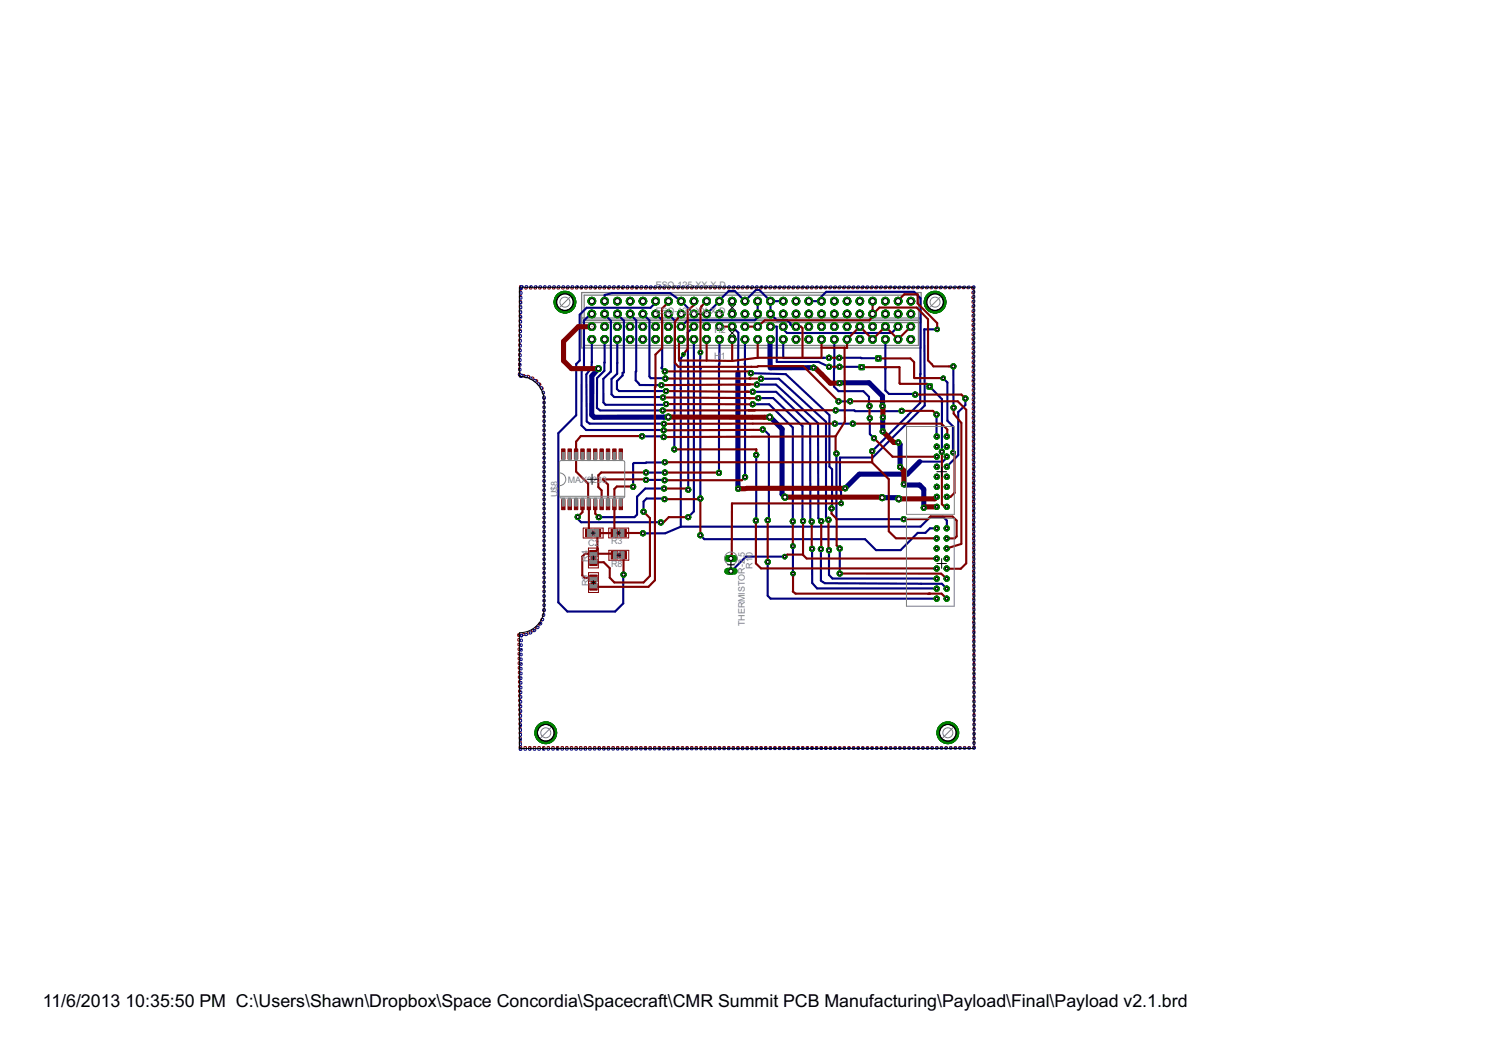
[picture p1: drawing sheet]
<svg xmlns="http://www.w3.org/2000/svg" width="297mm" height="210mm" viewBox="0 0 297 210" stroke-linecap="round" stroke-linejoin="round" font-family="sans-serif">
<defs><g id="words">
<g font-size="4">
<text x="8.5" y="200.4">11/6/2013</text>
<text x="25" y="200.4">10:35:50 PM C:\Users\Shawn\Dropbox\Space Concordia\Spacecraft\CMR Summit PCB Manufacturing\Payload\Final\Payload v2.1.brd</text>
</g>
<g font-size="2" fill="#808080">
<text x="130.5" y="57.4">ESQ-125-XX-X-D</text>
<text x="130.5" y="62.4">ESQ-125-X</text>
<text x="139.6" y="62.4">X-X-D</text>
<text x="142.1" y="71.3">H</text>
<text x="142.1" y="66.3">H2</text>
<text x="143.4" y="71.3">1</text>
<text x="110.9" y="98.9" transform="rotate(-90 110.9 98.9)">U$8</text>
<text x="113" y="96.1">MAX3</text>
<text x="117.8" y="96.1">233</text>
<text x="117" y="108.6">C2</text>
<text x="117" y="111.8" transform="rotate(-90 117 111.8)">R4</text>
<text x="121.6" y="108.3">R3</text>
<text x="121.6" y="112.8">R8</text>
<text x="149.7" y="113.1" transform="rotate(-90 149.7 113.1)">R10</text>
<text x="117.1" y="116.7" transform="rotate(-90 117.1 116.7)">R9</text>
<text x="148.2" y="124.6" transform="rotate(-90 148.2 124.6)">THERMISTOR-2,5</text>
</g>
</g></defs>
<path d="M115.7 58.2h67.6l-.1 11h-67.5zM116.2 58.7h66.6v5h-66.6zM115.7 64.2h67.6M115.7 63.3h67.5M116.2 63.8h66.5v4.9h-66.5z" fill="none" stroke="#808080" stroke-width=".25"/>
<g fill="none" stroke="#000080" stroke-width=".42">
<path d="M120.3 59.9v-1.2l1.5-.4h11.5l2.2 1.6 2.6 2.6h2.5l4.4-4.6h1.2l2 2 2.2-2.2h.7l2.2 2.2M130.5 59.9v.3l-1.1 1h-12.7l-1.4 1.4v9.1l-.7 .7v10.2l-3.5 3.6v33.6l1.8 1.9h9.5l1.6-1.6 .1-5.8M150.7 59.9v3.2l-.5 .6h-13.4l-1.3 1.3M153.3 59.9h2.5M153.3 59.9v2.6l1.3 1.3h2.1l1 1.2h.7M160.9 59.9h2.5v-.9l1-.9h17.5l1.2 1.2v20.8l-9.6 9.7M117.8 62.5h-.3l-1.3 1.3v9.4l-.5 .5v10.9l.9 1h15.4M117.8 67.5l-.1 5.7-1.1 1.3 .1 9.4 .6 .4h14.8M119.1 73.3l-.2 .1v.2M120.3 62.5l1.2 1.3v10.1l-1.5 1.5 .1 4.7 .4 .4h11.5l.5-.1M120.3 67.5l-.1 6.3-1.4 1.4v6l.6 .5h12.4M120.3 72.1h-.1"/>
<path d="M122.8 67.5v6.9l-1.1 1v3.1l.5 .5h9.8l-.1 .1M122.8 62.5l1.3 1.3v10.3l-.2 .1v.5l-1.2 1.1v1.6l.5 .4h9.3M125.4 62.5l1.2 1.3-.1 11.9 .8 .9h4.3M127.9 62.5l1.3 1.2v11.2l.3 .3 2.9 .1M130.5 62.5l1.2 1.2v9.3l-.1 .2 .7 .7M133 62.5l1.3 1.2-.1 25.7M136 70.5l-.6 .9v33.4M138 65l-1.2 1.1 .1 31.3M138 67.5v34.2l-1.1 1.2M138 72.5h.1M139.4 70.1l-.1 3 .1 .2-.1 25.9M143.1 67.5l-.1 26.6"/>
<path d="M145.7 65l1.2 1.2-.1 7.9M148.2 67.5v27.4M149.4 74.3l6.9 .1 8.7 8.2v10.2l.5 .6v7.6l-.1 .2M149.8 78h4.6l6.8 6.5v19.2l.3 .1M150.6 76.5h3.8l8.4 7.7v18.9l.6 .6M150.9 79.2h2.9l5.9 5.6v18.8l.1 .1M151.4 75.4h3.6l9.3 8.5v19l.5 .5M153.3 65h1.2v7h8.4l2.1 1M153.3 67.5l-.1 .1M155.8 65v.5l.8 .8h20.8l1.3-1.3M155.8 67.5v3.7h9.1M166 67.5l-.1 9.4 .9 .9h5l1.1 1.2v1.7l.1 .1"/>
<path d="M167 71.2l7.8 .1M167 73h4.4M167.2 76.2h-.2M169.1 79.8l-2.3 .1M176.1 67.5v10.2l.8 .7h5.1l.1 .1M183.9 65.5l.1 15.2-10.4 10.3h-6.5v6.5l.2 .2 .1 2.5M183.9 65.5v.1M183.9 65.5h2.6M185 76.9l2.4 2.5v10.5M187.7 75.3l.8 .8v7.6l1.1 1.1v5.2M189.7 72.9v8.2M192.1 79.3v1.3l-1.5 1.4v8.6l-2.2 2.3"/>
<path d="M127.7 86.8h4.4l-.1 .2M128.5 94h3.8M128.5 95.5h3.7M131.8 81.7h.1M132.1 97.2h-3.7l-1.7 1.6v3.6l-.5 .5h-7.1M132.2 99.3l-.1-.1h-3.5l-.6 .6v2M132.3 92l-6.2 .1-.1 .2v4.5M146.8 97.2h.1M149.8 80.4h3.2l4.7 4.7v18.6M150.5 90.5l-.1 13.1M151.7 85.4h.3l1 1.1v16.8l-.3 .2M153.1 83h.1"/>
<path d="M166.1 84.3h3.6M166.3 81.6h3.7l.1 .2 9.3-.1M166.4 90.2l.1 13.1h13.3M173.1 83.2v3.2l.8 .8M175.7 83l-.1 .1M178.6 99l.2 .3M179.8 96.4l.2 .1M186.3 82.5l.1 4.3M188.4 90.8v.3l-.8 .7h-4.6M114.9 102.8v.4l.7 .7h15.9M135.4 104.8l-3.1 1.3h-4.4M135.4 104.8h47.8l1.9-2h2.5l.8 .8v1.5"/>
<path d="M152.7 111.8v6.7l.6 .6h33.1M156.1 110.7h-7.7l-3 2.9M157.8 108.6v5.5M161.6 109.2v6.8l1 1.1h23.8M163.3 109.2v6.3l.8 .5 23.3 .1 .9 1M164.9 109.5v4.9l.7 .7h20.8M167.1 109.1v5M179.8 103.3h.1M186.4 105.1h-1.4l-.9 .9h-1.5l-3.4 3.5h-4.9l-2.2-2.2h-32l-.8-.8M188.4 105.1h-.1"/>
</g>
<path d="M118.9 73.6l-1.1 1.2-.1 7.7 .5 .5h14.7M118.9 73.4h.2M119.1 73.3v.1M146.8 74.1v23.1M153.2 67.6v5.6h8.7M167.2 76.2h5.7l2.7 2.6v2M153.2 83l2.4 2.3v13l.6 .6M175.5 99h3.1M175.6 83.1v2.7M178.7 88l.4 .4v4.5M180 96.5h3l.8 .8v3.7M183 91.8l-2.5 2.5h-9.5l-2.9 2.9" fill="none" stroke="#000080" stroke-width="1"/>
<circle cx="117.8" cy="62.5" r=".76" fill="#008000" stroke="#008000" stroke-width=".2"/>
<circle cx="117.8" cy="62.5" r=".51" fill="#fff" stroke="#000" stroke-width=".2"/>
<circle cx="117.8" cy="59.9" r=".76" fill="#008000" stroke="#008000" stroke-width=".2"/>
<circle cx="117.8" cy="59.9" r=".51" fill="#fff" stroke="#000" stroke-width=".2"/>
<circle cx="120.3" cy="62.5" r=".76" fill="#008000" stroke="#008000" stroke-width=".2"/>
<circle cx="120.3" cy="62.5" r=".51" fill="#fff" stroke="#000" stroke-width=".2"/>
<circle cx="120.3" cy="59.9" r=".76" fill="#008000" stroke="#008000" stroke-width=".2"/>
<circle cx="120.3" cy="59.9" r=".51" fill="#fff" stroke="#000" stroke-width=".2"/>
<circle cx="122.8" cy="62.5" r=".76" fill="#008000" stroke="#008000" stroke-width=".2"/>
<circle cx="122.8" cy="62.5" r=".51" fill="#fff" stroke="#000" stroke-width=".2"/>
<circle cx="122.8" cy="59.9" r=".76" fill="#008000" stroke="#008000" stroke-width=".2"/>
<circle cx="122.8" cy="59.9" r=".51" fill="#fff" stroke="#000" stroke-width=".2"/>
<circle cx="125.4" cy="62.5" r=".76" fill="#008000" stroke="#008000" stroke-width=".2"/>
<circle cx="125.4" cy="62.5" r=".51" fill="#fff" stroke="#000" stroke-width=".2"/>
<circle cx="125.4" cy="59.9" r=".76" fill="#008000" stroke="#008000" stroke-width=".2"/>
<circle cx="125.4" cy="59.9" r=".51" fill="#fff" stroke="#000" stroke-width=".2"/>
<circle cx="127.9" cy="62.5" r=".76" fill="#008000" stroke="#008000" stroke-width=".2"/>
<circle cx="127.9" cy="62.5" r=".51" fill="#fff" stroke="#000" stroke-width=".2"/>
<circle cx="127.9" cy="59.9" r=".76" fill="#008000" stroke="#008000" stroke-width=".2"/>
<circle cx="127.9" cy="59.9" r=".51" fill="#fff" stroke="#000" stroke-width=".2"/>
<circle cx="130.5" cy="62.5" r=".76" fill="#008000" stroke="#008000" stroke-width=".2"/>
<circle cx="130.5" cy="62.5" r=".51" fill="#fff" stroke="#000" stroke-width=".2"/>
<circle cx="130.5" cy="59.9" r=".76" fill="#008000" stroke="#008000" stroke-width=".2"/>
<circle cx="130.5" cy="59.9" r=".51" fill="#fff" stroke="#000" stroke-width=".2"/>
<circle cx="133" cy="62.5" r=".76" fill="#008000" stroke="#008000" stroke-width=".2"/>
<circle cx="133" cy="62.5" r=".51" fill="#fff" stroke="#000" stroke-width=".2"/>
<circle cx="133" cy="59.9" r=".76" fill="#008000" stroke="#008000" stroke-width=".2"/>
<circle cx="133" cy="59.9" r=".51" fill="#fff" stroke="#000" stroke-width=".2"/>
<circle cx="135.5" cy="62.5" r=".76" fill="#008000" stroke="#008000" stroke-width=".2"/>
<circle cx="135.5" cy="62.5" r=".51" fill="#fff" stroke="#000" stroke-width=".2"/>
<circle cx="135.5" cy="59.9" r=".76" fill="#008000" stroke="#008000" stroke-width=".2"/>
<circle cx="135.5" cy="59.9" r=".51" fill="#fff" stroke="#000" stroke-width=".2"/>
<circle cx="138.1" cy="62.5" r=".76" fill="#008000" stroke="#008000" stroke-width=".2"/>
<circle cx="138.1" cy="62.5" r=".51" fill="#fff" stroke="#000" stroke-width=".2"/>
<circle cx="138.1" cy="59.9" r=".76" fill="#008000" stroke="#008000" stroke-width=".2"/>
<circle cx="138.1" cy="59.9" r=".51" fill="#fff" stroke="#000" stroke-width=".2"/>
<circle cx="140.6" cy="62.5" r=".76" fill="#008000" stroke="#008000" stroke-width=".2"/>
<circle cx="140.6" cy="62.5" r=".51" fill="#fff" stroke="#000" stroke-width=".2"/>
<circle cx="140.6" cy="59.9" r=".76" fill="#008000" stroke="#008000" stroke-width=".2"/>
<circle cx="140.6" cy="59.9" r=".51" fill="#fff" stroke="#000" stroke-width=".2"/>
<circle cx="143.1" cy="62.5" r=".76" fill="#008000" stroke="#008000" stroke-width=".2"/>
<circle cx="143.1" cy="62.5" r=".51" fill="#fff" stroke="#000" stroke-width=".2"/>
<circle cx="143.1" cy="59.9" r=".76" fill="#008000" stroke="#008000" stroke-width=".2"/>
<circle cx="143.1" cy="59.9" r=".51" fill="#fff" stroke="#000" stroke-width=".2"/>
<circle cx="145.7" cy="62.5" r=".76" fill="#008000" stroke="#008000" stroke-width=".2"/>
<circle cx="145.7" cy="62.5" r=".51" fill="#fff" stroke="#000" stroke-width=".2"/>
<circle cx="145.7" cy="59.9" r=".76" fill="#008000" stroke="#008000" stroke-width=".2"/>
<circle cx="145.7" cy="59.9" r=".51" fill="#fff" stroke="#000" stroke-width=".2"/>
<circle cx="148.2" cy="62.5" r=".76" fill="#008000" stroke="#008000" stroke-width=".2"/>
<circle cx="148.2" cy="62.5" r=".51" fill="#fff" stroke="#000" stroke-width=".2"/>
<circle cx="148.2" cy="59.9" r=".76" fill="#008000" stroke="#008000" stroke-width=".2"/>
<circle cx="148.2" cy="59.9" r=".51" fill="#fff" stroke="#000" stroke-width=".2"/>
<circle cx="150.7" cy="62.5" r=".76" fill="#008000" stroke="#008000" stroke-width=".2"/>
<circle cx="150.7" cy="62.5" r=".51" fill="#fff" stroke="#000" stroke-width=".2"/>
<circle cx="150.7" cy="59.9" r=".76" fill="#008000" stroke="#008000" stroke-width=".2"/>
<circle cx="150.7" cy="59.9" r=".51" fill="#fff" stroke="#000" stroke-width=".2"/>
<circle cx="153.3" cy="62.5" r=".76" fill="#008000" stroke="#008000" stroke-width=".2"/>
<circle cx="153.3" cy="62.5" r=".51" fill="#fff" stroke="#000" stroke-width=".2"/>
<circle cx="153.3" cy="59.9" r=".76" fill="#008000" stroke="#008000" stroke-width=".2"/>
<circle cx="153.3" cy="59.9" r=".51" fill="#fff" stroke="#000" stroke-width=".2"/>
<circle cx="155.8" cy="62.5" r=".76" fill="#008000" stroke="#008000" stroke-width=".2"/>
<circle cx="155.8" cy="62.5" r=".51" fill="#fff" stroke="#000" stroke-width=".2"/>
<circle cx="155.8" cy="59.9" r=".76" fill="#008000" stroke="#008000" stroke-width=".2"/>
<circle cx="155.8" cy="59.9" r=".51" fill="#fff" stroke="#000" stroke-width=".2"/>
<circle cx="158.4" cy="62.5" r=".76" fill="#008000" stroke="#008000" stroke-width=".2"/>
<circle cx="158.4" cy="62.5" r=".51" fill="#fff" stroke="#000" stroke-width=".2"/>
<circle cx="158.4" cy="59.9" r=".76" fill="#008000" stroke="#008000" stroke-width=".2"/>
<circle cx="158.4" cy="59.9" r=".51" fill="#fff" stroke="#000" stroke-width=".2"/>
<circle cx="160.9" cy="62.5" r=".76" fill="#008000" stroke="#008000" stroke-width=".2"/>
<circle cx="160.9" cy="62.5" r=".51" fill="#fff" stroke="#000" stroke-width=".2"/>
<circle cx="160.9" cy="59.9" r=".76" fill="#008000" stroke="#008000" stroke-width=".2"/>
<circle cx="160.9" cy="59.9" r=".51" fill="#fff" stroke="#000" stroke-width=".2"/>
<circle cx="163.4" cy="62.5" r=".76" fill="#008000" stroke="#008000" stroke-width=".2"/>
<circle cx="163.4" cy="62.5" r=".51" fill="#fff" stroke="#000" stroke-width=".2"/>
<circle cx="163.4" cy="59.9" r=".76" fill="#008000" stroke="#008000" stroke-width=".2"/>
<circle cx="163.4" cy="59.9" r=".51" fill="#fff" stroke="#000" stroke-width=".2"/>
<circle cx="166" cy="62.5" r=".76" fill="#008000" stroke="#008000" stroke-width=".2"/>
<circle cx="166" cy="62.5" r=".51" fill="#fff" stroke="#000" stroke-width=".2"/>
<circle cx="166" cy="59.9" r=".76" fill="#008000" stroke="#008000" stroke-width=".2"/>
<circle cx="166" cy="59.9" r=".51" fill="#fff" stroke="#000" stroke-width=".2"/>
<circle cx="168.5" cy="62.5" r=".76" fill="#008000" stroke="#008000" stroke-width=".2"/>
<circle cx="168.5" cy="62.5" r=".51" fill="#fff" stroke="#000" stroke-width=".2"/>
<circle cx="168.5" cy="59.9" r=".76" fill="#008000" stroke="#008000" stroke-width=".2"/>
<circle cx="168.5" cy="59.9" r=".51" fill="#fff" stroke="#000" stroke-width=".2"/>
<circle cx="171.1" cy="62.5" r=".76" fill="#008000" stroke="#008000" stroke-width=".2"/>
<circle cx="171.1" cy="62.5" r=".51" fill="#fff" stroke="#000" stroke-width=".2"/>
<circle cx="171.1" cy="59.9" r=".76" fill="#008000" stroke="#008000" stroke-width=".2"/>
<circle cx="171.1" cy="59.9" r=".51" fill="#fff" stroke="#000" stroke-width=".2"/>
<circle cx="173.6" cy="62.5" r=".76" fill="#008000" stroke="#008000" stroke-width=".2"/>
<circle cx="173.6" cy="62.5" r=".51" fill="#fff" stroke="#000" stroke-width=".2"/>
<circle cx="173.6" cy="59.9" r=".76" fill="#008000" stroke="#008000" stroke-width=".2"/>
<circle cx="173.6" cy="59.9" r=".51" fill="#fff" stroke="#000" stroke-width=".2"/>
<circle cx="176.1" cy="62.5" r=".76" fill="#008000" stroke="#008000" stroke-width=".2"/>
<circle cx="176.1" cy="62.5" r=".51" fill="#fff" stroke="#000" stroke-width=".2"/>
<circle cx="176.1" cy="59.9" r=".76" fill="#008000" stroke="#008000" stroke-width=".2"/>
<circle cx="176.1" cy="59.9" r=".51" fill="#fff" stroke="#000" stroke-width=".2"/>
<circle cx="178.7" cy="62.5" r=".76" fill="#008000" stroke="#008000" stroke-width=".2"/>
<circle cx="178.7" cy="62.5" r=".51" fill="#fff" stroke="#000" stroke-width=".2"/>
<circle cx="178.7" cy="59.9" r=".76" fill="#008000" stroke="#008000" stroke-width=".2"/>
<circle cx="178.7" cy="59.9" r=".51" fill="#fff" stroke="#000" stroke-width=".2"/>
<circle cx="181.2" cy="62.5" r=".76" fill="#008000" stroke="#008000" stroke-width=".2"/>
<circle cx="181.2" cy="62.5" r=".51" fill="#fff" stroke="#000" stroke-width=".2"/>
<circle cx="181.2" cy="59.9" r=".76" fill="#008000" stroke="#008000" stroke-width=".2"/>
<circle cx="181.2" cy="59.9" r=".51" fill="#fff" stroke="#000" stroke-width=".2"/>
<circle cx="117.8" cy="67.5" r=".76" fill="#008000" stroke="#008000" stroke-width=".2"/>
<circle cx="117.8" cy="67.5" r=".51" fill="#fff" stroke="#000" stroke-width=".2"/>
<circle cx="117.8" cy="65" r=".76" fill="#008000" stroke="#008000" stroke-width=".2"/>
<circle cx="117.8" cy="65" r=".51" fill="#fff" stroke="#000" stroke-width=".2"/>
<circle cx="120.3" cy="67.5" r=".76" fill="#008000" stroke="#008000" stroke-width=".2"/>
<circle cx="120.3" cy="67.5" r=".51" fill="#fff" stroke="#000" stroke-width=".2"/>
<circle cx="120.3" cy="65" r=".76" fill="#008000" stroke="#008000" stroke-width=".2"/>
<circle cx="120.3" cy="65" r=".51" fill="#fff" stroke="#000" stroke-width=".2"/>
<circle cx="122.8" cy="67.5" r=".76" fill="#008000" stroke="#008000" stroke-width=".2"/>
<circle cx="122.8" cy="67.5" r=".51" fill="#fff" stroke="#000" stroke-width=".2"/>
<circle cx="122.8" cy="65" r=".76" fill="#008000" stroke="#008000" stroke-width=".2"/>
<circle cx="122.8" cy="65" r=".51" fill="#fff" stroke="#000" stroke-width=".2"/>
<circle cx="125.3" cy="67.5" r=".76" fill="#008000" stroke="#008000" stroke-width=".2"/>
<circle cx="125.3" cy="67.5" r=".51" fill="#fff" stroke="#000" stroke-width=".2"/>
<circle cx="125.3" cy="65" r=".76" fill="#008000" stroke="#008000" stroke-width=".2"/>
<circle cx="125.3" cy="65" r=".51" fill="#fff" stroke="#000" stroke-width=".2"/>
<circle cx="127.9" cy="67.5" r=".76" fill="#008000" stroke="#008000" stroke-width=".2"/>
<circle cx="127.9" cy="67.5" r=".51" fill="#fff" stroke="#000" stroke-width=".2"/>
<circle cx="127.9" cy="65" r=".76" fill="#008000" stroke="#008000" stroke-width=".2"/>
<circle cx="127.9" cy="65" r=".51" fill="#fff" stroke="#000" stroke-width=".2"/>
<circle cx="130.4" cy="67.5" r=".76" fill="#008000" stroke="#008000" stroke-width=".2"/>
<circle cx="130.4" cy="67.5" r=".51" fill="#fff" stroke="#000" stroke-width=".2"/>
<circle cx="130.4" cy="65" r=".76" fill="#008000" stroke="#008000" stroke-width=".2"/>
<circle cx="130.4" cy="65" r=".51" fill="#fff" stroke="#000" stroke-width=".2"/>
<circle cx="133" cy="67.5" r=".76" fill="#008000" stroke="#008000" stroke-width=".2"/>
<circle cx="133" cy="67.5" r=".51" fill="#fff" stroke="#000" stroke-width=".2"/>
<circle cx="133" cy="65" r=".76" fill="#008000" stroke="#008000" stroke-width=".2"/>
<circle cx="133" cy="65" r=".51" fill="#fff" stroke="#000" stroke-width=".2"/>
<circle cx="135.5" cy="67.5" r=".76" fill="#008000" stroke="#008000" stroke-width=".2"/>
<circle cx="135.5" cy="67.5" r=".51" fill="#fff" stroke="#000" stroke-width=".2"/>
<circle cx="135.5" cy="65" r=".76" fill="#008000" stroke="#008000" stroke-width=".2"/>
<circle cx="135.5" cy="65" r=".51" fill="#fff" stroke="#000" stroke-width=".2"/>
<circle cx="138" cy="67.5" r=".76" fill="#008000" stroke="#008000" stroke-width=".2"/>
<circle cx="138" cy="67.5" r=".51" fill="#fff" stroke="#000" stroke-width=".2"/>
<circle cx="138" cy="65" r=".76" fill="#008000" stroke="#008000" stroke-width=".2"/>
<circle cx="138" cy="65" r=".51" fill="#fff" stroke="#000" stroke-width=".2"/>
<circle cx="140.6" cy="67.5" r=".76" fill="#008000" stroke="#008000" stroke-width=".2"/>
<circle cx="140.6" cy="67.5" r=".51" fill="#fff" stroke="#000" stroke-width=".2"/>
<circle cx="140.6" cy="65" r=".76" fill="#008000" stroke="#008000" stroke-width=".2"/>
<circle cx="140.6" cy="65" r=".51" fill="#fff" stroke="#000" stroke-width=".2"/>
<circle cx="143.1" cy="67.5" r=".76" fill="#008000" stroke="#008000" stroke-width=".2"/>
<circle cx="143.1" cy="67.5" r=".51" fill="#fff" stroke="#000" stroke-width=".2"/>
<circle cx="143.1" cy="65" r=".76" fill="#008000" stroke="#008000" stroke-width=".2"/>
<circle cx="143.1" cy="65" r=".51" fill="#fff" stroke="#000" stroke-width=".2"/>
<circle cx="145.7" cy="67.5" r=".76" fill="#008000" stroke="#008000" stroke-width=".2"/>
<circle cx="145.7" cy="67.5" r=".51" fill="#fff" stroke="#000" stroke-width=".2"/>
<circle cx="145.7" cy="65" r=".76" fill="#008000" stroke="#008000" stroke-width=".2"/>
<circle cx="145.7" cy="65" r=".51" fill="#fff" stroke="#000" stroke-width=".2"/>
<circle cx="148.2" cy="67.5" r=".76" fill="#008000" stroke="#008000" stroke-width=".2"/>
<circle cx="148.2" cy="67.5" r=".51" fill="#fff" stroke="#000" stroke-width=".2"/>
<circle cx="148.2" cy="65" r=".76" fill="#008000" stroke="#008000" stroke-width=".2"/>
<circle cx="148.2" cy="65" r=".51" fill="#fff" stroke="#000" stroke-width=".2"/>
<circle cx="150.7" cy="67.5" r=".76" fill="#008000" stroke="#008000" stroke-width=".2"/>
<circle cx="150.7" cy="67.5" r=".51" fill="#fff" stroke="#000" stroke-width=".2"/>
<circle cx="150.7" cy="65" r=".76" fill="#008000" stroke="#008000" stroke-width=".2"/>
<circle cx="150.7" cy="65" r=".51" fill="#fff" stroke="#000" stroke-width=".2"/>
<circle cx="153.3" cy="67.5" r=".76" fill="#008000" stroke="#008000" stroke-width=".2"/>
<circle cx="153.3" cy="67.5" r=".51" fill="#fff" stroke="#000" stroke-width=".2"/>
<circle cx="153.3" cy="65" r=".76" fill="#008000" stroke="#008000" stroke-width=".2"/>
<circle cx="153.3" cy="65" r=".51" fill="#fff" stroke="#000" stroke-width=".2"/>
<circle cx="155.8" cy="67.5" r=".76" fill="#008000" stroke="#008000" stroke-width=".2"/>
<circle cx="155.8" cy="67.5" r=".51" fill="#fff" stroke="#000" stroke-width=".2"/>
<circle cx="155.8" cy="65" r=".76" fill="#008000" stroke="#008000" stroke-width=".2"/>
<circle cx="155.8" cy="65" r=".51" fill="#fff" stroke="#000" stroke-width=".2"/>
<circle cx="158.4" cy="67.5" r=".76" fill="#008000" stroke="#008000" stroke-width=".2"/>
<circle cx="158.4" cy="67.5" r=".51" fill="#fff" stroke="#000" stroke-width=".2"/>
<circle cx="158.4" cy="65" r=".76" fill="#008000" stroke="#008000" stroke-width=".2"/>
<circle cx="158.4" cy="65" r=".51" fill="#fff" stroke="#000" stroke-width=".2"/>
<circle cx="160.9" cy="67.5" r=".76" fill="#008000" stroke="#008000" stroke-width=".2"/>
<circle cx="160.9" cy="67.5" r=".51" fill="#fff" stroke="#000" stroke-width=".2"/>
<circle cx="160.9" cy="65" r=".76" fill="#008000" stroke="#008000" stroke-width=".2"/>
<circle cx="160.9" cy="65" r=".51" fill="#fff" stroke="#000" stroke-width=".2"/>
<circle cx="163.4" cy="67.5" r=".76" fill="#008000" stroke="#008000" stroke-width=".2"/>
<circle cx="163.4" cy="67.5" r=".51" fill="#fff" stroke="#000" stroke-width=".2"/>
<circle cx="163.4" cy="65" r=".76" fill="#008000" stroke="#008000" stroke-width=".2"/>
<circle cx="163.4" cy="65" r=".51" fill="#fff" stroke="#000" stroke-width=".2"/>
<circle cx="166" cy="67.5" r=".76" fill="#008000" stroke="#008000" stroke-width=".2"/>
<circle cx="166" cy="67.5" r=".51" fill="#fff" stroke="#000" stroke-width=".2"/>
<circle cx="166" cy="65" r=".76" fill="#008000" stroke="#008000" stroke-width=".2"/>
<circle cx="166" cy="65" r=".51" fill="#fff" stroke="#000" stroke-width=".2"/>
<circle cx="168.5" cy="67.5" r=".76" fill="#008000" stroke="#008000" stroke-width=".2"/>
<circle cx="168.5" cy="67.5" r=".51" fill="#fff" stroke="#000" stroke-width=".2"/>
<circle cx="168.5" cy="65" r=".76" fill="#008000" stroke="#008000" stroke-width=".2"/>
<circle cx="168.5" cy="65" r=".51" fill="#fff" stroke="#000" stroke-width=".2"/>
<circle cx="171.1" cy="67.5" r=".76" fill="#008000" stroke="#008000" stroke-width=".2"/>
<circle cx="171.1" cy="67.5" r=".51" fill="#fff" stroke="#000" stroke-width=".2"/>
<circle cx="171.1" cy="65" r=".76" fill="#008000" stroke="#008000" stroke-width=".2"/>
<circle cx="171.1" cy="65" r=".51" fill="#fff" stroke="#000" stroke-width=".2"/>
<circle cx="173.6" cy="67.5" r=".76" fill="#008000" stroke="#008000" stroke-width=".2"/>
<circle cx="173.6" cy="67.5" r=".51" fill="#fff" stroke="#000" stroke-width=".2"/>
<circle cx="173.6" cy="65" r=".76" fill="#008000" stroke="#008000" stroke-width=".2"/>
<circle cx="173.6" cy="65" r=".51" fill="#fff" stroke="#000" stroke-width=".2"/>
<circle cx="176.1" cy="67.5" r=".76" fill="#008000" stroke="#008000" stroke-width=".2"/>
<circle cx="176.1" cy="67.5" r=".51" fill="#fff" stroke="#000" stroke-width=".2"/>
<circle cx="176.1" cy="65" r=".76" fill="#008000" stroke="#008000" stroke-width=".2"/>
<circle cx="176.1" cy="65" r=".51" fill="#fff" stroke="#000" stroke-width=".2"/>
<circle cx="178.7" cy="67.5" r=".76" fill="#008000" stroke="#008000" stroke-width=".2"/>
<circle cx="178.7" cy="67.5" r=".51" fill="#fff" stroke="#000" stroke-width=".2"/>
<circle cx="178.7" cy="65" r=".76" fill="#008000" stroke="#008000" stroke-width=".2"/>
<circle cx="178.7" cy="65" r=".51" fill="#fff" stroke="#000" stroke-width=".2"/>
<circle cx="181.2" cy="67.5" r=".76" fill="#008000" stroke="#008000" stroke-width=".2"/>
<circle cx="181.2" cy="67.5" r=".51" fill="#fff" stroke="#000" stroke-width=".2"/>
<circle cx="181.2" cy="65" r=".76" fill="#008000" stroke="#008000" stroke-width=".2"/>
<circle cx="181.2" cy="65" r=".51" fill="#fff" stroke="#000" stroke-width=".2"/>
<circle cx="186.4" cy="100.8" r=".51" fill="#008000" stroke="#008000" stroke-width=".2"/>
<circle cx="186.4" cy="100.8" r=".25" fill="#fff" stroke="#000" stroke-width=".2"/>
<circle cx="188.4" cy="100.8" r=".51" fill="#008000" stroke="#008000" stroke-width=".2"/>
<circle cx="188.4" cy="100.8" r=".25" fill="#fff" stroke="#000" stroke-width=".2"/>
<circle cx="186.4" cy="98.8" r=".51" fill="#008000" stroke="#008000" stroke-width=".2"/>
<circle cx="186.4" cy="98.8" r=".25" fill="#fff" stroke="#000" stroke-width=".2"/>
<circle cx="188.4" cy="98.8" r=".51" fill="#008000" stroke="#008000" stroke-width=".2"/>
<circle cx="188.4" cy="98.8" r=".25" fill="#fff" stroke="#000" stroke-width=".2"/>
<circle cx="186.4" cy="96.9" r=".51" fill="#008000" stroke="#008000" stroke-width=".2"/>
<circle cx="186.4" cy="96.9" r=".25" fill="#fff" stroke="#000" stroke-width=".2"/>
<circle cx="188.4" cy="96.9" r=".51" fill="#008000" stroke="#008000" stroke-width=".2"/>
<circle cx="188.4" cy="96.9" r=".25" fill="#fff" stroke="#000" stroke-width=".2"/>
<circle cx="186.4" cy="94.8" r=".51" fill="#008000" stroke="#008000" stroke-width=".2"/>
<circle cx="186.4" cy="94.8" r=".25" fill="#fff" stroke="#000" stroke-width=".2"/>
<circle cx="188.4" cy="94.8" r=".51" fill="#008000" stroke="#008000" stroke-width=".2"/>
<circle cx="188.4" cy="94.8" r=".25" fill="#fff" stroke="#000" stroke-width=".2"/>
<circle cx="186.4" cy="92.9" r=".51" fill="#008000" stroke="#008000" stroke-width=".2"/>
<circle cx="186.4" cy="92.9" r=".25" fill="#fff" stroke="#000" stroke-width=".2"/>
<circle cx="188.4" cy="92.9" r=".51" fill="#008000" stroke="#008000" stroke-width=".2"/>
<circle cx="188.4" cy="92.9" r=".25" fill="#fff" stroke="#000" stroke-width=".2"/>
<circle cx="186.4" cy="90.8" r=".51" fill="#008000" stroke="#008000" stroke-width=".2"/>
<circle cx="186.4" cy="90.8" r=".25" fill="#fff" stroke="#000" stroke-width=".2"/>
<circle cx="188.4" cy="90.8" r=".51" fill="#008000" stroke="#008000" stroke-width=".2"/>
<circle cx="188.4" cy="90.8" r=".25" fill="#fff" stroke="#000" stroke-width=".2"/>
<circle cx="186.4" cy="88.9" r=".51" fill="#008000" stroke="#008000" stroke-width=".2"/>
<circle cx="186.4" cy="88.9" r=".25" fill="#fff" stroke="#000" stroke-width=".2"/>
<circle cx="188.4" cy="88.9" r=".51" fill="#008000" stroke="#008000" stroke-width=".2"/>
<circle cx="188.4" cy="88.9" r=".25" fill="#fff" stroke="#000" stroke-width=".2"/>
<circle cx="186.4" cy="86.8" r=".51" fill="#008000" stroke="#008000" stroke-width=".2"/>
<circle cx="186.4" cy="86.8" r=".25" fill="#fff" stroke="#000" stroke-width=".2"/>
<circle cx="188.4" cy="86.8" r=".51" fill="#008000" stroke="#008000" stroke-width=".2"/>
<circle cx="188.4" cy="86.8" r=".25" fill="#fff" stroke="#000" stroke-width=".2"/>
<circle cx="186.4" cy="119.1" r=".51" fill="#008000" stroke="#008000" stroke-width=".2"/>
<circle cx="186.4" cy="119.1" r=".25" fill="#fff" stroke="#000" stroke-width=".2"/>
<circle cx="188.3" cy="119.1" r=".51" fill="#008000" stroke="#008000" stroke-width=".2"/>
<circle cx="188.3" cy="119.1" r=".25" fill="#fff" stroke="#000" stroke-width=".2"/>
<circle cx="186.4" cy="117.1" r=".51" fill="#008000" stroke="#008000" stroke-width=".2"/>
<circle cx="186.4" cy="117.1" r=".25" fill="#fff" stroke="#000" stroke-width=".2"/>
<circle cx="188.3" cy="117.1" r=".51" fill="#008000" stroke="#008000" stroke-width=".2"/>
<circle cx="188.3" cy="117.1" r=".25" fill="#fff" stroke="#000" stroke-width=".2"/>
<circle cx="186.4" cy="115.1" r=".51" fill="#008000" stroke="#008000" stroke-width=".2"/>
<circle cx="186.4" cy="115.1" r=".25" fill="#fff" stroke="#000" stroke-width=".2"/>
<circle cx="188.3" cy="115.1" r=".51" fill="#008000" stroke="#008000" stroke-width=".2"/>
<circle cx="188.3" cy="115.1" r=".25" fill="#fff" stroke="#000" stroke-width=".2"/>
<circle cx="186.4" cy="113.1" r=".51" fill="#008000" stroke="#008000" stroke-width=".2"/>
<circle cx="186.4" cy="113.1" r=".25" fill="#fff" stroke="#000" stroke-width=".2"/>
<circle cx="188.3" cy="113.1" r=".51" fill="#008000" stroke="#008000" stroke-width=".2"/>
<circle cx="188.3" cy="113.1" r=".25" fill="#fff" stroke="#000" stroke-width=".2"/>
<circle cx="186.4" cy="111.1" r=".51" fill="#008000" stroke="#008000" stroke-width=".2"/>
<circle cx="186.4" cy="111.1" r=".25" fill="#fff" stroke="#000" stroke-width=".2"/>
<circle cx="188.3" cy="111.1" r=".51" fill="#008000" stroke="#008000" stroke-width=".2"/>
<circle cx="188.3" cy="111.1" r=".25" fill="#fff" stroke="#000" stroke-width=".2"/>
<circle cx="186.4" cy="109.1" r=".51" fill="#008000" stroke="#008000" stroke-width=".2"/>
<circle cx="186.4" cy="109.1" r=".25" fill="#fff" stroke="#000" stroke-width=".2"/>
<circle cx="188.3" cy="109.1" r=".51" fill="#008000" stroke="#008000" stroke-width=".2"/>
<circle cx="188.3" cy="109.1" r=".25" fill="#fff" stroke="#000" stroke-width=".2"/>
<circle cx="186.4" cy="107.1" r=".51" fill="#008000" stroke="#008000" stroke-width=".2"/>
<circle cx="186.4" cy="107.1" r=".25" fill="#fff" stroke="#000" stroke-width=".2"/>
<circle cx="188.3" cy="107.1" r=".51" fill="#008000" stroke="#008000" stroke-width=".2"/>
<circle cx="188.3" cy="107.1" r=".25" fill="#fff" stroke="#000" stroke-width=".2"/>
<circle cx="186.4" cy="105.1" r=".51" fill="#008000" stroke="#008000" stroke-width=".2"/>
<circle cx="186.4" cy="105.1" r=".25" fill="#fff" stroke="#000" stroke-width=".2"/>
<circle cx="188.3" cy="105.1" r=".51" fill="#008000" stroke="#008000" stroke-width=".2"/>
<circle cx="188.3" cy="105.1" r=".25" fill="#fff" stroke="#000" stroke-width=".2"/>
<path d="M144.8 111.1h1.3" fill="none" stroke="#008000" stroke-width="1.3"/>
<circle cx="145.4" cy="111.1" r=".4" fill="#fff" stroke="#000" stroke-width=".2"/>
<path d="M144.8 113.6h1.3" fill="none" stroke="#008000" stroke-width="1.3"/>
<circle cx="145.4" cy="113.6" r=".4" fill="#fff" stroke="#000" stroke-width=".2"/>
<circle cx="127.7" cy="86.8" r=".51" fill="#008000" stroke="#008000" stroke-width=".2"/>
<circle cx="127.7" cy="86.8" r=".3" fill="#fff" stroke="#000" stroke-width=".2"/>
<circle cx="132" cy="87" r=".51" fill="#008000" stroke="#008000" stroke-width=".2"/>
<circle cx="132" cy="87" r=".3" fill="#fff" stroke="#000" stroke-width=".2"/>
<circle cx="166.4" cy="90.2" r=".51" fill="#008000" stroke="#008000" stroke-width=".2"/>
<circle cx="166.4" cy="90.2" r=".3" fill="#fff" stroke="#000" stroke-width=".2"/>
<circle cx="179.8" cy="103.3" r=".51" fill="#008000" stroke="#008000" stroke-width=".2"/>
<circle cx="179.8" cy="103.3" r=".3" fill="#fff" stroke="#000" stroke-width=".2"/>
<circle cx="132.4" cy="75.3" r=".51" fill="#008000" stroke="#008000" stroke-width=".2"/>
<circle cx="132.4" cy="75.3" r=".3" fill="#fff" stroke="#000" stroke-width=".2"/>
<circle cx="151.4" cy="75.4" r=".51" fill="#008000" stroke="#008000" stroke-width=".2"/>
<circle cx="151.4" cy="75.4" r=".3" fill="#fff" stroke="#000" stroke-width=".2"/>
<circle cx="164.8" cy="103.4" r=".51" fill="#008000" stroke="#008000" stroke-width=".2"/>
<circle cx="164.8" cy="103.4" r=".3" fill="#fff" stroke="#000" stroke-width=".2"/>
<circle cx="164.9" cy="109.5" r=".51" fill="#008000" stroke="#008000" stroke-width=".2"/>
<circle cx="164.9" cy="109.5" r=".3" fill="#fff" stroke="#000" stroke-width=".2"/>
<circle cx="132.3" cy="73.9" r=".51" fill="#008000" stroke="#008000" stroke-width=".2"/>
<circle cx="132.3" cy="73.9" r=".3" fill="#fff" stroke="#000" stroke-width=".2"/>
<circle cx="149.4" cy="74.3" r=".51" fill="#008000" stroke="#008000" stroke-width=".2"/>
<circle cx="149.4" cy="74.3" r=".3" fill="#fff" stroke="#000" stroke-width=".2"/>
<circle cx="165.4" cy="101.2" r=".51" fill="#008000" stroke="#008000" stroke-width=".2"/>
<circle cx="165.4" cy="101.2" r=".3" fill="#fff" stroke="#000" stroke-width=".2"/>
<circle cx="167.1" cy="109.1" r=".51" fill="#008000" stroke="#008000" stroke-width=".2"/>
<circle cx="167.1" cy="109.1" r=".3" fill="#fff" stroke="#000" stroke-width=".2"/>
<circle cx="167.1" cy="114.1" r=".51" fill="#008000" stroke="#008000" stroke-width=".2"/>
<circle cx="167.1" cy="114.1" r=".3" fill="#fff" stroke="#000" stroke-width=".2"/>
<circle cx="166.8" cy="79.9" r=".51" fill="#008000" stroke="#008000" stroke-width=".2"/>
<circle cx="166.8" cy="79.9" r=".3" fill="#fff" stroke="#000" stroke-width=".2"/>
<circle cx="169.1" cy="79.8" r=".51" fill="#008000" stroke="#008000" stroke-width=".2"/>
<circle cx="169.1" cy="79.8" r=".3" fill="#fff" stroke="#000" stroke-width=".2"/>
<circle cx="167.4" cy="100.2" r=".44" fill="#008000" stroke="#008000" stroke-width=".2"/>
<circle cx="167.4" cy="100.2" r=".25" fill="#fff" stroke="#000" stroke-width=".2"/>
<circle cx="186.5" cy="65.5" r=".44" fill="#008000" stroke="#008000" stroke-width=".2"/>
<circle cx="186.5" cy="65.5" r=".25" fill="#fff" stroke="#000" stroke-width=".2"/>
<circle cx="124.1" cy="114.3" r=".51" fill="#008000" stroke="#008000" stroke-width=".2"/>
<circle cx="124.1" cy="114.3" r=".3" fill="#fff" stroke="#000" stroke-width=".2"/>
<circle cx="132.5" cy="80.4" r=".51" fill="#008000" stroke="#008000" stroke-width=".2"/>
<circle cx="132.5" cy="80.4" r=".3" fill="#fff" stroke="#000" stroke-width=".2"/>
<circle cx="149.8" cy="80.4" r=".51" fill="#008000" stroke="#008000" stroke-width=".2"/>
<circle cx="149.8" cy="80.4" r=".3" fill="#fff" stroke="#000" stroke-width=".2"/>
<circle cx="157.7" cy="103.7" r=".51" fill="#008000" stroke="#008000" stroke-width=".2"/>
<circle cx="157.7" cy="103.7" r=".3" fill="#fff" stroke="#000" stroke-width=".2"/>
<circle cx="157.8" cy="114.1" r=".44" fill="#008000" stroke="#008000" stroke-width=".2"/>
<circle cx="157.8" cy="114.1" r=".25" fill="#fff" stroke="#000" stroke-width=".2"/>
<circle cx="157.8" cy="108.6" r=".44" fill="#008000" stroke="#008000" stroke-width=".2"/>
<circle cx="157.8" cy="108.6" r=".25" fill="#fff" stroke="#000" stroke-width=".2"/>
<circle cx="131.6" cy="76.6" r=".51" fill="#008000" stroke="#008000" stroke-width=".2"/>
<circle cx="131.6" cy="76.6" r=".3" fill="#fff" stroke="#000" stroke-width=".2"/>
<circle cx="150.6" cy="76.5" r=".51" fill="#008000" stroke="#008000" stroke-width=".2"/>
<circle cx="150.6" cy="76.5" r=".3" fill="#fff" stroke="#000" stroke-width=".2"/>
<circle cx="163.4" cy="103.7" r=".51" fill="#008000" stroke="#008000" stroke-width=".2"/>
<circle cx="163.4" cy="103.7" r=".3" fill="#fff" stroke="#000" stroke-width=".2"/>
<circle cx="163.3" cy="109.2" r=".51" fill="#008000" stroke="#008000" stroke-width=".2"/>
<circle cx="163.3" cy="109.2" r=".3" fill="#fff" stroke="#000" stroke-width=".2"/>
<circle cx="132.5" cy="77.8" r=".51" fill="#008000" stroke="#008000" stroke-width=".2"/>
<circle cx="132.5" cy="77.8" r=".3" fill="#fff" stroke="#000" stroke-width=".2"/>
<circle cx="149.8" cy="78" r=".51" fill="#008000" stroke="#008000" stroke-width=".2"/>
<circle cx="149.8" cy="78" r=".3" fill="#fff" stroke="#000" stroke-width=".2"/>
<circle cx="161.5" cy="103.8" r=".51" fill="#008000" stroke="#008000" stroke-width=".2"/>
<circle cx="161.5" cy="103.8" r=".3" fill="#fff" stroke="#000" stroke-width=".2"/>
<circle cx="161.6" cy="109.2" r=".51" fill="#008000" stroke="#008000" stroke-width=".2"/>
<circle cx="161.6" cy="109.2" r=".3" fill="#fff" stroke="#000" stroke-width=".2"/>
<circle cx="132" cy="85.6" r=".51" fill="#008000" stroke="#008000" stroke-width=".2"/>
<circle cx="132" cy="85.6" r=".3" fill="#fff" stroke="#000" stroke-width=".2"/>
<circle cx="151.7" cy="85.4" r=".51" fill="#008000" stroke="#008000" stroke-width=".2"/>
<circle cx="151.7" cy="85.4" r=".3" fill="#fff" stroke="#000" stroke-width=".2"/>
<circle cx="152.7" cy="103.5" r=".51" fill="#008000" stroke="#008000" stroke-width=".2"/>
<circle cx="152.7" cy="103.5" r=".3" fill="#fff" stroke="#000" stroke-width=".2"/>
<circle cx="152.7" cy="111.8" r=".51" fill="#008000" stroke="#008000" stroke-width=".2"/>
<circle cx="152.7" cy="111.8" r=".3" fill="#fff" stroke="#000" stroke-width=".2"/>
<circle cx="134.2" cy="89.4" r=".51" fill="#008000" stroke="#008000" stroke-width=".2"/>
<circle cx="134.2" cy="89.4" r=".3" fill="#fff" stroke="#000" stroke-width=".2"/>
<circle cx="150.5" cy="90.5" r=".51" fill="#008000" stroke="#008000" stroke-width=".2"/>
<circle cx="150.5" cy="90.5" r=".3" fill="#fff" stroke="#000" stroke-width=".2"/>
<circle cx="150.4" cy="103.6" r=".51" fill="#008000" stroke="#008000" stroke-width=".2"/>
<circle cx="150.4" cy="103.6" r=".3" fill="#fff" stroke="#000" stroke-width=".2"/>
<circle cx="126" cy="96.8" r=".51" fill="#008000" stroke="#008000" stroke-width=".2"/>
<circle cx="126" cy="96.8" r=".3" fill="#fff" stroke="#000" stroke-width=".2"/>
<circle cx="132.3" cy="92" r=".51" fill="#008000" stroke="#008000" stroke-width=".2"/>
<circle cx="132.3" cy="92" r=".3" fill="#fff" stroke="#000" stroke-width=".2"/>
<circle cx="173.5" cy="89.8" r=".51" fill="#008000" stroke="#008000" stroke-width=".2"/>
<circle cx="173.5" cy="89.8" r=".3" fill="#fff" stroke="#000" stroke-width=".2"/>
<circle cx="189.7" cy="72.9" r=".51" fill="#008000" stroke="#008000" stroke-width=".2"/>
<circle cx="189.7" cy="72.9" r=".3" fill="#fff" stroke="#000" stroke-width=".2"/>
<circle cx="189.7" cy="81.1" r=".51" fill="#008000" stroke="#008000" stroke-width=".2"/>
<circle cx="189.7" cy="81.1" r=".3" fill="#fff" stroke="#000" stroke-width=".2"/>
<circle cx="173" cy="80.8" r=".51" fill="#008000" stroke="#008000" stroke-width=".2"/>
<circle cx="173" cy="80.8" r=".3" fill="#fff" stroke="#000" stroke-width=".2"/>
<circle cx="173.1" cy="83.2" r=".51" fill="#008000" stroke="#008000" stroke-width=".2"/>
<circle cx="173.1" cy="83.2" r=".3" fill="#fff" stroke="#000" stroke-width=".2"/>
<circle cx="173.9" cy="87.2" r=".51" fill="#008000" stroke="#008000" stroke-width=".2"/>
<circle cx="173.9" cy="87.2" r=".3" fill="#fff" stroke="#000" stroke-width=".2"/>
<circle cx="182.1" cy="78.5" r=".51" fill="#008000" stroke="#008000" stroke-width=".2"/>
<circle cx="182.1" cy="78.5" r=".3" fill="#fff" stroke="#000" stroke-width=".2"/>
<circle cx="192.1" cy="79.3" r=".51" fill="#008000" stroke="#008000" stroke-width=".2"/>
<circle cx="192.1" cy="79.3" r=".3" fill="#fff" stroke="#000" stroke-width=".2"/>
<circle cx="136" cy="70.5" r=".34" fill="#008000" stroke="#008000" stroke-width=".2"/>
<circle cx="136" cy="70.5" r=".13" fill="#fff" stroke="#000" stroke-width=".2"/>
<circle cx="127.9" cy="106.1" r=".51" fill="#008000" stroke="#008000" stroke-width=".2"/>
<circle cx="127.9" cy="106.1" r=".3" fill="#fff" stroke="#000" stroke-width=".2"/>
<circle cx="139.4" cy="70.1" r=".44" fill="#008000" stroke="#008000" stroke-width=".2"/>
<circle cx="139.4" cy="70.1" r=".25" fill="#fff" stroke="#000" stroke-width=".2"/>
<circle cx="128" cy="101.8" r=".51" fill="#008000" stroke="#008000" stroke-width=".2"/>
<circle cx="128" cy="101.8" r=".3" fill="#fff" stroke="#000" stroke-width=".2"/>
<circle cx="132.2" cy="99.3" r=".51" fill="#008000" stroke="#008000" stroke-width=".2"/>
<circle cx="132.2" cy="99.3" r=".3" fill="#fff" stroke="#000" stroke-width=".2"/>
<circle cx="139.3" cy="99.2" r=".51" fill="#008000" stroke="#008000" stroke-width=".2"/>
<circle cx="139.3" cy="99.2" r=".3" fill="#fff" stroke="#000" stroke-width=".2"/>
<circle cx="139.3" cy="106.5" r=".51" fill="#008000" stroke="#008000" stroke-width=".2"/>
<circle cx="139.3" cy="106.5" r=".3" fill="#fff" stroke="#000" stroke-width=".2"/>
<circle cx="119.1" cy="102.9" r=".51" fill="#008000" stroke="#008000" stroke-width=".2"/>
<circle cx="119.1" cy="102.9" r=".3" fill="#fff" stroke="#000" stroke-width=".2"/>
<circle cx="132.1" cy="97.2" r=".51" fill="#008000" stroke="#008000" stroke-width=".2"/>
<circle cx="132.1" cy="97.2" r=".3" fill="#fff" stroke="#000" stroke-width=".2"/>
<circle cx="136.9" cy="97.4" r=".51" fill="#008000" stroke="#008000" stroke-width=".2"/>
<circle cx="136.9" cy="97.4" r=".3" fill="#fff" stroke="#000" stroke-width=".2"/>
<circle cx="136.9" cy="102.9" r=".51" fill="#008000" stroke="#008000" stroke-width=".2"/>
<circle cx="136.9" cy="102.9" r=".3" fill="#fff" stroke="#000" stroke-width=".2"/>
<circle cx="114.9" cy="102.8" r=".51" fill="#008000" stroke="#008000" stroke-width=".2"/>
<circle cx="114.9" cy="102.8" r=".3" fill="#fff" stroke="#000" stroke-width=".2"/>
<circle cx="131.5" cy="103.9" r=".51" fill="#008000" stroke="#008000" stroke-width=".2"/>
<circle cx="131.5" cy="103.9" r=".3" fill="#fff" stroke="#000" stroke-width=".2"/>
<circle cx="132.1" cy="84.3" r=".51" fill="#008000" stroke="#008000" stroke-width=".2"/>
<circle cx="132.1" cy="84.3" r=".3" fill="#fff" stroke="#000" stroke-width=".2"/>
<circle cx="166.1" cy="84.3" r=".51" fill="#008000" stroke="#008000" stroke-width=".2"/>
<circle cx="166.1" cy="84.3" r=".3" fill="#fff" stroke="#000" stroke-width=".2"/>
<circle cx="169.7" cy="84.3" r=".51" fill="#008000" stroke="#008000" stroke-width=".2"/>
<circle cx="169.7" cy="84.3" r=".3" fill="#fff" stroke="#000" stroke-width=".2"/>
<circle cx="131.8" cy="81.7" r=".51" fill="#008000" stroke="#008000" stroke-width=".2"/>
<circle cx="131.8" cy="81.7" r=".3" fill="#fff" stroke="#000" stroke-width=".2"/>
<circle cx="166.3" cy="81.6" r=".51" fill="#008000" stroke="#008000" stroke-width=".2"/>
<circle cx="166.3" cy="81.6" r=".3" fill="#fff" stroke="#000" stroke-width=".2"/>
<circle cx="179.4" cy="81.7" r=".51" fill="#008000" stroke="#008000" stroke-width=".2"/>
<circle cx="179.4" cy="81.7" r=".3" fill="#fff" stroke="#000" stroke-width=".2"/>
<circle cx="186.3" cy="82.5" r=".51" fill="#008000" stroke="#008000" stroke-width=".2"/>
<circle cx="186.3" cy="82.5" r=".3" fill="#fff" stroke="#000" stroke-width=".2"/>
<circle cx="183.8" cy="101" r=".51" fill="#008000" stroke="#008000" stroke-width=".2"/>
<circle cx="183.8" cy="101" r=".3" fill="#fff" stroke="#000" stroke-width=".2"/>
<circle cx="179.8" cy="96.4" r=".51" fill="#008000" stroke="#008000" stroke-width=".2"/>
<circle cx="179.8" cy="96.4" r=".3" fill="#fff" stroke="#000" stroke-width=".2"/>
<circle cx="179.1" cy="92.9" r=".51" fill="#008000" stroke="#008000" stroke-width=".2"/>
<circle cx="179.1" cy="92.9" r=".3" fill="#fff" stroke="#000" stroke-width=".2"/>
<circle cx="178.7" cy="88" r=".51" fill="#008000" stroke="#008000" stroke-width=".2"/>
<circle cx="178.7" cy="88" r=".3" fill="#fff" stroke="#000" stroke-width=".2"/>
<circle cx="175.6" cy="85.8" r=".51" fill="#008000" stroke="#008000" stroke-width=".2"/>
<circle cx="175.6" cy="85.8" r=".3" fill="#fff" stroke="#000" stroke-width=".2"/>
<circle cx="175.7" cy="83" r=".51" fill="#008000" stroke="#008000" stroke-width=".2"/>
<circle cx="175.7" cy="83" r=".3" fill="#fff" stroke="#000" stroke-width=".2"/>
<circle cx="175.6" cy="80.8" r=".51" fill="#008000" stroke="#008000" stroke-width=".2"/>
<circle cx="175.6" cy="80.8" r=".3" fill="#fff" stroke="#000" stroke-width=".2"/>
<circle cx="167" cy="76.2" r=".51" fill="#008000" stroke="#008000" stroke-width=".2"/>
<circle cx="167" cy="76.2" r=".3" fill="#fff" stroke="#000" stroke-width=".2"/>
<circle cx="161.9" cy="73.2" r=".51" fill="#008000" stroke="#008000" stroke-width=".2"/>
<circle cx="161.9" cy="73.2" r=".3" fill="#fff" stroke="#000" stroke-width=".2"/>
<circle cx="132.9" cy="83" r=".59" fill="#008000" stroke="#008000" stroke-width=".2"/>
<circle cx="132.9" cy="83" r=".4" fill="#fff" stroke="#000" stroke-width=".2"/>
<circle cx="153.1" cy="83" r=".59" fill="#008000" stroke="#008000" stroke-width=".2"/>
<circle cx="153.1" cy="83" r=".4" fill="#fff" stroke="#000" stroke-width=".2"/>
<circle cx="156.2" cy="98.9" r=".59" fill="#008000" stroke="#008000" stroke-width=".2"/>
<circle cx="156.2" cy="98.9" r=".4" fill="#fff" stroke="#000" stroke-width=".2"/>
<circle cx="175.5" cy="99" r=".59" fill="#008000" stroke="#008000" stroke-width=".2"/>
<circle cx="175.5" cy="99" r=".4" fill="#fff" stroke="#000" stroke-width=".2"/>
<circle cx="178.8" cy="99.3" r=".59" fill="#008000" stroke="#008000" stroke-width=".2"/>
<circle cx="178.8" cy="99.3" r=".4" fill="#fff" stroke="#000" stroke-width=".2"/>
<circle cx="119.1" cy="73.3" r=".59" fill="#008000" stroke="#008000" stroke-width=".2"/>
<circle cx="119.1" cy="73.3" r=".4" fill="#fff" stroke="#000" stroke-width=".2"/>
<circle cx="128.5" cy="94" r=".51" fill="#008000" stroke="#008000" stroke-width=".2"/>
<circle cx="128.5" cy="94" r=".3" fill="#fff" stroke="#000" stroke-width=".2"/>
<circle cx="132.3" cy="94" r=".51" fill="#008000" stroke="#008000" stroke-width=".2"/>
<circle cx="132.3" cy="94" r=".3" fill="#fff" stroke="#000" stroke-width=".2"/>
<circle cx="143" cy="94.1" r=".51" fill="#008000" stroke="#008000" stroke-width=".2"/>
<circle cx="143" cy="94.1" r=".3" fill="#fff" stroke="#000" stroke-width=".2"/>
<circle cx="128.5" cy="95.5" r=".51" fill="#008000" stroke="#008000" stroke-width=".2"/>
<circle cx="128.5" cy="95.5" r=".3" fill="#fff" stroke="#000" stroke-width=".2"/>
<circle cx="132.2" cy="95.5" r=".51" fill="#008000" stroke="#008000" stroke-width=".2"/>
<circle cx="132.2" cy="95.5" r=".3" fill="#fff" stroke="#000" stroke-width=".2"/>
<circle cx="148.2" cy="94.9" r=".51" fill="#008000" stroke="#008000" stroke-width=".2"/>
<circle cx="148.2" cy="94.9" r=".3" fill="#fff" stroke="#000" stroke-width=".2"/>
<circle cx="131.9" cy="79.1" r=".51" fill="#008000" stroke="#008000" stroke-width=".2"/>
<circle cx="131.9" cy="79.1" r=".3" fill="#fff" stroke="#000" stroke-width=".2"/>
<circle cx="150.9" cy="79.2" r=".51" fill="#008000" stroke="#008000" stroke-width=".2"/>
<circle cx="150.9" cy="79.2" r=".3" fill="#fff" stroke="#000" stroke-width=".2"/>
<circle cx="159.8" cy="103.7" r=".51" fill="#008000" stroke="#008000" stroke-width=".2"/>
<circle cx="159.8" cy="103.7" r=".3" fill="#fff" stroke="#000" stroke-width=".2"/>
<circle cx="156.1" cy="110.7" r=".44" fill="#008000" stroke="#008000" stroke-width=".2"/>
<circle cx="156.1" cy="110.7" r=".25" fill="#fff" stroke="#000" stroke-width=".2"/>
<circle cx="112.4" cy="60.1" r="2.16" fill="#008000" stroke="#008000" stroke-width=".2"/>
<circle cx="112.4" cy="60.1" r="1.65" fill="#fff" stroke="#000" stroke-width=".2"/>
<circle cx="186" cy="60.1" r="2.16" fill="#008000" stroke="#008000" stroke-width=".2"/>
<circle cx="186" cy="60.1" r="1.65" fill="#fff" stroke="#000" stroke-width=".2"/>
<circle cx="188.6" cy="145.8" r="2.16" fill="#008000" stroke="#008000" stroke-width=".2"/>
<circle cx="188.6" cy="145.8" r="1.65" fill="#fff" stroke="#000" stroke-width=".2"/>
<circle cx="108.6" cy="145.8" r="2.16" fill="#008000" stroke="#008000" stroke-width=".2"/>
<circle cx="108.6" cy="145.8" r="1.65" fill="#fff" stroke="#000" stroke-width=".2"/>
<circle cx="168.1" cy="97.2" r=".51" fill="#008000" stroke="#008000" stroke-width=".2"/>
<circle cx="168.1" cy="97.2" r=".3" fill="#fff" stroke="#000" stroke-width=".2"/>
<circle cx="146.9" cy="97.2" r=".51" fill="#008000" stroke="#008000" stroke-width=".2"/>
<circle cx="146.9" cy="97.2" r=".3" fill="#fff" stroke="#000" stroke-width=".2"/>
<circle cx="165" cy="73" r=".51" fill="#008000" stroke="#008000" stroke-width=".2"/>
<circle cx="165" cy="73" r=".3" fill="#fff" stroke="#000" stroke-width=".2"/>
<circle cx="167" cy="73" r=".51" fill="#008000" stroke="#008000" stroke-width=".2"/>
<circle cx="167" cy="73" r=".3" fill="#fff" stroke="#000" stroke-width=".2"/>
<path d="M170.9 72.5h1v1.1h-1z" fill="#008000" stroke="#008000" stroke-width=".2"/>
<circle cx="171.4" cy="73" r=".3" fill="#fff" stroke="#000" stroke-width=".2"/>
<path d="M184.4 76.4h1.1v1h-1.1z" fill="#008000" stroke="#008000" stroke-width=".2"/>
<circle cx="185" cy="76.9" r=".3" fill="#fff" stroke="#000" stroke-width=".2"/>
<circle cx="187.4" cy="89.9" r=".51" fill="#008000" stroke="#008000" stroke-width=".2"/>
<circle cx="187.4" cy="89.9" r=".3" fill="#fff" stroke="#000" stroke-width=".2"/>
<circle cx="164.9" cy="71.2" r=".51" fill="#008000" stroke="#008000" stroke-width=".2"/>
<circle cx="164.9" cy="71.2" r=".3" fill="#fff" stroke="#000" stroke-width=".2"/>
<circle cx="167" cy="71.2" r=".51" fill="#008000" stroke="#008000" stroke-width=".2"/>
<circle cx="167" cy="71.2" r=".3" fill="#fff" stroke="#000" stroke-width=".2"/>
<path d="M174.2 70.8h1.1v1h-1.1z" fill="#008000" stroke="#008000" stroke-width=".2"/>
<circle cx="174.8" cy="71.3" r=".3" fill="#fff" stroke="#000" stroke-width=".2"/>
<circle cx="187.7" cy="75.3" r=".44" fill="#008000" stroke="#008000" stroke-width=".2"/>
<circle cx="187.7" cy="75.3" r=".25" fill="#fff" stroke="#000" stroke-width=".2"/>
<circle cx="189.6" cy="90" r=".44" fill="#008000" stroke="#008000" stroke-width=".2"/>
<circle cx="189.6" cy="90" r=".25" fill="#fff" stroke="#000" stroke-width=".2"/>
<g fill="#800000" stroke="#800000" stroke-width=".2">
<path d="M103.3 145.6l.4 .1-.1 .4-.3-.1z"/>
<path d="M103.3 141l.3 .1-.1 .4-.3-.1z"/>
<path d="M103.5 74.6h.7l.1 .3h-.8z"/>
<path d="M103.4 56.9h.3l.2 .5-.3 .1z"/>
<circle cx="103.7" cy="57.4" r=".25"/>
<circle cx="104.7" cy="57.3" r=".23"/>
<circle cx="105.6" cy="57.3" r=".25"/>
<circle cx="106.5" cy="57.3" r=".25"/>
<circle cx="107.4" cy="57.3" r=".25"/>
<circle cx="108.3" cy="57.3" r=".24"/>
<circle cx="109.2" cy="57.3" r=".25"/>
<circle cx="110.2" cy="57.3" r=".25"/>
<circle cx="111.1" cy="57.3" r=".25"/>
<circle cx="112" cy="57.3" r=".25"/>
<circle cx="112.9" cy="57.3" r=".25"/>
<circle cx="113.8" cy="57.3" r=".25"/>
<circle cx="114.7" cy="57.3" r=".24"/>
<circle cx="115.7" cy="57.3" r=".25"/>
<circle cx="116.6" cy="57.3" r=".25"/>
<circle cx="117.5" cy="57.3" r=".25"/>
<circle cx="118.4" cy="57.3" r=".25"/>
<circle cx="119.3" cy="57.3" r=".25"/>
<circle cx="120.2" cy="57.3" r=".25"/>
<circle cx="121.1" cy="57.3" r=".25"/>
<circle cx="122.1" cy="57.3" r=".25"/>
<circle cx="123" cy="57.3" r=".25"/>
<circle cx="123.9" cy="57.3" r=".25"/>
<circle cx="124.8" cy="57.3" r=".24"/>
<circle cx="125.7" cy="57.3" r=".25"/>
<circle cx="126.6" cy="57.3" r=".25"/>
<circle cx="127.6" cy="57.3" r=".25"/>
<circle cx="128.5" cy="57.3" r=".25"/>
<circle cx="129.4" cy="57.3" r=".25"/>
<circle cx="130.3" cy="57.3" r=".25"/>
<circle cx="131.2" cy="57.3" r=".24"/>
<circle cx="132.1" cy="57.3" r=".25"/>
<circle cx="133.1" cy="57.3" r=".25"/>
<circle cx="134" cy="57.3" r=".25"/>
<circle cx="134.9" cy="57.3" r=".24"/>
<circle cx="135.8" cy="57.3" r=".25"/>
<circle cx="136.7" cy="57.3" r=".25"/>
<circle cx="137.6" cy="57.3" r=".25"/>
<circle cx="138.6" cy="57.3" r=".25"/>
<circle cx="139.5" cy="57.3" r=".25"/>
<circle cx="140.4" cy="57.3" r=".25"/>
<circle cx="141.3" cy="57.3" r=".24"/>
<circle cx="142.2" cy="57.3" r=".25"/>
<circle cx="143.1" cy="57.3" r=".25"/>
<circle cx="144" cy="57.3" r=".25"/>
<circle cx="145" cy="57.3" r=".25"/>
<circle cx="145.9" cy="57.3" r=".25"/>
<circle cx="146.8" cy="57.3" r=".25"/>
<circle cx="147.7" cy="57.3" r=".25"/>
<circle cx="148.6" cy="57.3" r=".25"/>
<circle cx="149.5" cy="57.3" r=".25"/>
<circle cx="150.5" cy="57.3" r=".25"/>
<circle cx="151.4" cy="57.3" r=".24"/>
<circle cx="152.3" cy="57.3" r=".25"/>
<circle cx="153.2" cy="57.3" r=".25"/>
<circle cx="154.1" cy="57.3" r=".25"/>
<circle cx="155" cy="57.3" r=".25"/>
<circle cx="156" cy="57.3" r=".25"/>
<circle cx="156.9" cy="57.3" r=".25"/>
<circle cx="157.8" cy="57.3" r=".24"/>
<circle cx="158.7" cy="57.3" r=".25"/>
<circle cx="159.6" cy="57.3" r=".25"/>
<circle cx="160.5" cy="57.3" r=".25"/>
<circle cx="161.5" cy="57.3" r=".25"/>
<circle cx="162.4" cy="57.3" r=".25"/>
<circle cx="163.3" cy="57.3" r=".25"/>
<circle cx="164.2" cy="57.3" r=".25"/>
<circle cx="165.1" cy="57.3" r=".25"/>
<circle cx="166" cy="57.3" r=".25"/>
<circle cx="166.9" cy="57.3" r=".25"/>
<circle cx="167.9" cy="57.3" r=".24"/>
<circle cx="168.8" cy="57.3" r=".25"/>
<circle cx="169.7" cy="57.3" r=".25"/>
<circle cx="170.6" cy="57.3" r=".25"/>
<circle cx="171.5" cy="57.3" r=".25"/>
<circle cx="172.4" cy="57.3" r=".25"/>
<circle cx="173.4" cy="57.3" r=".25"/>
<circle cx="174.3" cy="57.3" r=".25"/>
<circle cx="175.2" cy="57.3" r=".25"/>
<circle cx="176.1" cy="57.3" r=".25"/>
<circle cx="177" cy="57.3" r=".25"/>
<circle cx="177.9" cy="57.3" r=".24"/>
<circle cx="178.9" cy="57.3" r=".25"/>
<circle cx="179.8" cy="57.3" r=".25"/>
<circle cx="180.7" cy="57.3" r=".25"/>
<circle cx="181.6" cy="57.3" r=".25"/>
<circle cx="182.5" cy="57.3" r=".25"/>
<circle cx="183.4" cy="57.3" r=".25"/>
<circle cx="184.4" cy="57.3" r=".24"/>
<circle cx="185.3" cy="57.3" r=".25"/>
<circle cx="186.2" cy="57.3" r=".25"/>
<circle cx="187.1" cy="57.3" r=".25"/>
<circle cx="188" cy="57.3" r=".25"/>
<circle cx="188.9" cy="57.3" r=".25"/>
<circle cx="189.8" cy="57.3" r=".25"/>
<circle cx="190.8" cy="57.3" r=".25"/>
<circle cx="191.7" cy="57.3" r=".25"/>
<circle cx="192.6" cy="57.3" r=".25"/>
<circle cx="193.5" cy="57.3" r=".25"/>
<circle cx="193.5" cy="57.3" r=".26"/>
<circle cx="193.5" cy="58.2" r=".25"/>
<circle cx="193.5" cy="59.2" r=".25"/>
<circle cx="193.5" cy="60.1" r=".25"/>
<circle cx="193.5" cy="61" r=".25"/>
<circle cx="193.5" cy="61.9" r=".26"/>
<circle cx="193.5" cy="62.8" r=".25"/>
<circle cx="193.5" cy="63.8" r=".25"/>
<circle cx="193.5" cy="64.7" r=".26"/>
<circle cx="193.5" cy="65.6" r=".25"/>
<circle cx="193.5" cy="66.5" r=".25"/>
<circle cx="193.5" cy="67.5" r=".25"/>
<circle cx="193.6" cy="68.4" r=".25"/>
<circle cx="193.6" cy="69.3" r=".26"/>
<circle cx="193.6" cy="70.2" r=".25"/>
<circle cx="193.6" cy="71.2" r=".25"/>
<circle cx="193.6" cy="72.1" r=".25"/>
<circle cx="193.6" cy="73" r=".25"/>
<circle cx="193.6" cy="73.9" r=".26"/>
<circle cx="193.6" cy="74.8" r=".25"/>
<circle cx="193.6" cy="75.8" r=".25"/>
<circle cx="193.6" cy="76.7" r=".25"/>
<circle cx="193.6" cy="77.6" r=".25"/>
<circle cx="193.6" cy="78.5" r=".26"/>
<circle cx="193.6" cy="79.5" r=".25"/>
<circle cx="193.6" cy="80.4" r=".25"/>
<circle cx="193.6" cy="81.3" r=".25"/>
<circle cx="193.6" cy="82.2" r=".25"/>
<circle cx="193.6" cy="83.2" r=".26"/>
<circle cx="193.6" cy="84.1" r=".25"/>
<circle cx="193.6" cy="85" r=".25"/>
<circle cx="193.6" cy="85.9" r=".26"/>
<circle cx="193.6" cy="86.8" r=".25"/>
<circle cx="193.6" cy="87.8" r=".25"/>
<circle cx="193.6" cy="88.7" r=".25"/>
<circle cx="193.6" cy="89.6" r=".25"/>
<circle cx="193.6" cy="90.5" r=".26"/>
<circle cx="193.6" cy="91.5" r=".25"/>
<circle cx="193.6" cy="92.4" r=".25"/>
<circle cx="193.6" cy="93.3" r=".25"/>
<circle cx="193.6" cy="94.2" r=".25"/>
<circle cx="193.6" cy="95.2" r=".26"/>
<circle cx="193.6" cy="96.1" r=".25"/>
<circle cx="193.6" cy="97" r=".25"/>
<circle cx="193.6" cy="97.9" r=".25"/>
<circle cx="193.6" cy="98.8" r=".25"/>
<circle cx="193.6" cy="99.8" r=".26"/>
<circle cx="193.7" cy="100.7" r=".25"/>
<circle cx="193.7" cy="101.6" r=".25"/>
<circle cx="193.7" cy="102.5" r=".25"/>
<circle cx="193.7" cy="103.5" r=".25"/>
<circle cx="193.6" cy="104.4" r=".26"/>
<circle cx="193.7" cy="105.3" r=".25"/>
<circle cx="193.7" cy="106.2" r=".25"/>
<circle cx="193.6" cy="107.2" r=".26"/>
<circle cx="193.7" cy="108.1" r=".25"/>
<circle cx="193.7" cy="109" r=".25"/>
<circle cx="193.7" cy="109.9" r=".25"/>
<circle cx="193.7" cy="110.8" r=".25"/>
<circle cx="193.7" cy="111.8" r=".26"/>
<circle cx="193.7" cy="112.7" r=".25"/>
<circle cx="193.7" cy="113.6" r=".25"/>
<circle cx="193.7" cy="114.5" r=".25"/>
<circle cx="193.7" cy="115.5" r=".25"/>
<circle cx="193.7" cy="116.4" r=".26"/>
<circle cx="193.7" cy="117.3" r=".25"/>
<circle cx="193.7" cy="118.2" r=".25"/>
<circle cx="193.7" cy="119.1" r=".25"/>
<circle cx="193.7" cy="120.1" r=".25"/>
<circle cx="193.7" cy="121" r=".26"/>
<circle cx="193.7" cy="121.9" r=".25"/>
<circle cx="193.7" cy="122.9" r=".25"/>
<circle cx="193.7" cy="123.8" r=".26"/>
<circle cx="193.7" cy="124.7" r=".25"/>
<circle cx="193.7" cy="125.6" r=".26"/>
<circle cx="193.7" cy="126.5" r=".25"/>
<circle cx="193.7" cy="127.5" r=".25"/>
<circle cx="193.7" cy="128.4" r=".26"/>
<circle cx="193.7" cy="129.3" r=".25"/>
<circle cx="193.7" cy="130.2" r=".25"/>
<circle cx="193.7" cy="131.1" r=".25"/>
<circle cx="193.7" cy="132.1" r=".25"/>
<circle cx="193.7" cy="133" r=".26"/>
<circle cx="193.7" cy="133.9" r=".25"/>
<circle cx="193.7" cy="134.9" r=".25"/>
<circle cx="193.7" cy="135.8" r=".25"/>
<circle cx="193.7" cy="136.7" r=".25"/>
<circle cx="193.7" cy="137.6" r=".26"/>
<circle cx="193.7" cy="138.5" r=".25"/>
<circle cx="193.7" cy="139.5" r=".25"/>
<circle cx="193.8" cy="140.4" r=".25"/>
<circle cx="193.8" cy="141.3" r=".25"/>
<circle cx="193.8" cy="142.2" r=".26"/>
<circle cx="193.8" cy="143.2" r=".25"/>
<circle cx="193.8" cy="144.1" r=".25"/>
<circle cx="193.8" cy="145" r=".26"/>
<circle cx="193.8" cy="145.9" r=".25"/>
<circle cx="193.8" cy="146.9" r=".25"/>
<circle cx="193.8" cy="147.8" r=".25"/>
<circle cx="193.8" cy="148.7" r=".25"/>
<circle cx="192.8" cy="148.7" r=".25"/>
<circle cx="191.9" cy="148.7" r=".25"/>
<circle cx="191" cy="148.7" r=".25"/>
<circle cx="190.1" cy="148.7" r=".25"/>
<circle cx="189.1" cy="148.7" r=".25"/>
<circle cx="188.2" cy="148.7" r=".25"/>
<circle cx="187.3" cy="148.7" r=".25"/>
<circle cx="186.4" cy="148.7" r=".25"/>
<circle cx="185.5" cy="148.7" r=".25"/>
<circle cx="184.6" cy="148.7" r=".25"/>
<circle cx="183.6" cy="148.7" r=".25"/>
<circle cx="182.7" cy="148.7" r=".25"/>
<circle cx="181.8" cy="148.7" r=".25"/>
<circle cx="180.9" cy="148.7" r=".25"/>
<circle cx="179.9" cy="148.7" r=".26"/>
<circle cx="179" cy="148.7" r=".25"/>
<circle cx="178.1" cy="148.7" r=".25"/>
<circle cx="177.2" cy="148.7" r=".25"/>
<circle cx="176.3" cy="148.7" r=".25"/>
<circle cx="175.3" cy="148.7" r=".25"/>
<circle cx="174.4" cy="148.7" r=".25"/>
<circle cx="173.5" cy="148.7" r=".25"/>
<circle cx="172.6" cy="148.7" r=".25"/>
<circle cx="171.7" cy="148.7" r=".25"/>
<circle cx="170.8" cy="148.7" r=".25"/>
<circle cx="169.8" cy="148.7" r=".25"/>
<circle cx="168.9" cy="148.7" r=".25"/>
<circle cx="168" cy="148.7" r=".25"/>
<circle cx="167.1" cy="148.7" r=".25"/>
<circle cx="166.1" cy="148.7" r=".25"/>
<circle cx="165.2" cy="148.7" r=".25"/>
<circle cx="164.3" cy="148.7" r=".26"/>
<circle cx="163.4" cy="148.7" r=".25"/>
<circle cx="162.5" cy="148.7" r=".26"/>
<circle cx="161.5" cy="148.7" r=".25"/>
<circle cx="160.6" cy="148.7" r=".25"/>
<circle cx="159.7" cy="148.7" r=".25"/>
<circle cx="158.8" cy="148.7" r=".25"/>
<circle cx="157.9" cy="148.7" r=".25"/>
<circle cx="157" cy="148.7" r=".25"/>
<circle cx="156" cy="148.7" r=".25"/>
<circle cx="155.1" cy="148.7" r=".25"/>
<circle cx="154.2" cy="148.7" r=".25"/>
<circle cx="153.3" cy="148.7" r=".25"/>
<circle cx="152.3" cy="148.7" r=".25"/>
<circle cx="151.4" cy="148.7" r=".25"/>
<circle cx="150.5" cy="148.7" r=".25"/>
<circle cx="149.6" cy="148.7" r=".25"/>
<circle cx="148.7" cy="148.7" r=".26"/>
<circle cx="147.7" cy="148.7" r=".25"/>
<circle cx="146.8" cy="148.7" r=".26"/>
<circle cx="145.9" cy="148.7" r=".25"/>
<circle cx="145" cy="148.7" r=".25"/>
<circle cx="144.1" cy="148.7" r=".25"/>
<circle cx="143.2" cy="148.7" r=".25"/>
<circle cx="142.2" cy="148.7" r=".25"/>
<circle cx="141.3" cy="148.7" r=".25"/>
<circle cx="140.4" cy="148.7" r=".25"/>
<circle cx="139.5" cy="148.7" r=".25"/>
<circle cx="138.5" cy="148.7" r=".25"/>
<circle cx="137.6" cy="148.7" r=".25"/>
<circle cx="136.7" cy="148.7" r=".25"/>
<circle cx="135.8" cy="148.7" r=".25"/>
<circle cx="134.9" cy="148.7" r=".25"/>
<circle cx="133.9" cy="148.7" r=".25"/>
<circle cx="133" cy="148.7" r=".26"/>
<circle cx="132.1" cy="148.7" r=".25"/>
<circle cx="131.2" cy="148.7" r=".26"/>
<circle cx="130.3" cy="148.7" r=".25"/>
<circle cx="129.3" cy="148.7" r=".25"/>
<circle cx="128.4" cy="148.7" r=".25"/>
<circle cx="127.5" cy="148.7" r=".25"/>
<circle cx="126.6" cy="148.7" r=".25"/>
<circle cx="125.7" cy="148.7" r=".25"/>
<circle cx="124.7" cy="148.7" r=".25"/>
<circle cx="123.8" cy="148.7" r=".25"/>
<circle cx="122.9" cy="148.7" r=".25"/>
<circle cx="122" cy="148.7" r=".25"/>
<circle cx="121.1" cy="148.7" r=".25"/>
<circle cx="120.1" cy="148.7" r=".25"/>
<circle cx="119.2" cy="148.7" r=".25"/>
<circle cx="118.3" cy="148.7" r=".25"/>
<circle cx="117.4" cy="148.7" r=".25"/>
<circle cx="116.5" cy="148.7" r=".25"/>
<circle cx="115.5" cy="148.7" r=".26"/>
<circle cx="114.6" cy="148.7" r=".25"/>
<circle cx="113.7" cy="148.7" r=".25"/>
<circle cx="112.8" cy="148.7" r=".25"/>
<circle cx="111.9" cy="148.7" r=".25"/>
<circle cx="110.9" cy="148.7" r=".25"/>
<circle cx="110" cy="148.7" r=".25"/>
<circle cx="109.1" cy="148.7" r=".25"/>
<circle cx="108.2" cy="148.7" r=".25"/>
<circle cx="107.3" cy="148.7" r=".25"/>
<circle cx="106.3" cy="148.7" r=".25"/>
<circle cx="105.4" cy="148.7" r=".25"/>
<circle cx="104.5" cy="148.7" r=".25"/>
<circle cx="103.6" cy="148.7" r=".25"/>
<circle cx="103.6" cy="148.7" r=".26"/>
<circle cx="103.6" cy="147.7" r=".26"/>
<circle cx="103.5" cy="146.8" r=".26"/>
<circle cx="103.5" cy="144.9" r=".25"/>
<circle cx="103.5" cy="144" r=".25"/>
<circle cx="103.5" cy="143.1" r=".25"/>
<circle cx="103.5" cy="142.2" r=".25"/>
<circle cx="103.4" cy="140.3" r=".26"/>
<circle cx="103.4" cy="139.4" r=".26"/>
<circle cx="103.4" cy="138.4" r=".26"/>
<circle cx="103.4" cy="137.5" r=".25"/>
<circle cx="103.4" cy="136.6" r=".23"/>
<circle cx="103.4" cy="135.7" r=".25"/>
<circle cx="103.4" cy="134.7" r=".25"/>
<circle cx="103.4" cy="133.8" r=".26"/>
<circle cx="103.3" cy="132.9" r=".26"/>
<circle cx="103.3" cy="131.9" r=".26"/>
<circle cx="103.3" cy="131" r=".26"/>
<circle cx="103.3" cy="130.1" r=".25"/>
<circle cx="103.3" cy="129.2" r=".25"/>
<circle cx="103.3" cy="128.2" r=".25"/>
<circle cx="103.3" cy="127.3" r=".25"/>
<circle cx="103.3" cy="126.4" r=".26"/>
<circle cx="108.3" cy="121.3" r=".25"/>
<circle cx="108.3" cy="120.4" r=".25"/>
<circle cx="108.3" cy="119.5" r=".25"/>
<circle cx="108.3" cy="118.6" r=".25"/>
<circle cx="108.3" cy="117.6" r=".25"/>
<circle cx="108.3" cy="116.7" r=".25"/>
<circle cx="108.3" cy="115.8" r=".25"/>
<circle cx="108.3" cy="114.9" r=".24"/>
<circle cx="108.3" cy="114" r=".25"/>
<circle cx="108.3" cy="113.1" r=".25"/>
<circle cx="108.3" cy="112.2" r=".25"/>
<circle cx="108.3" cy="111.2" r=".25"/>
<circle cx="108.3" cy="110.3" r=".25"/>
<circle cx="108.3" cy="109.4" r=".25"/>
<circle cx="108.3" cy="108.5" r=".25"/>
<circle cx="108.3" cy="107.6" r=".25"/>
<circle cx="108.3" cy="106.7" r=".25"/>
<circle cx="108.3" cy="105.7" r=".25"/>
<circle cx="108.3" cy="104.8" r=".24"/>
<circle cx="108.3" cy="103.9" r=".25"/>
<circle cx="108.3" cy="103" r=".25"/>
<circle cx="108.3" cy="102.1" r=".25"/>
<circle cx="108.3" cy="101.2" r=".24"/>
<circle cx="108.3" cy="100.2" r=".25"/>
<circle cx="108.3" cy="99.3" r=".25"/>
<circle cx="108.3" cy="98.4" r=".25"/>
<circle cx="108.3" cy="97.5" r=".25"/>
<circle cx="108.3" cy="96.6" r=".25"/>
<circle cx="108.3" cy="95.7" r=".25"/>
<circle cx="108.3" cy="94.8" r=".24"/>
<circle cx="108.3" cy="93.8" r=".25"/>
<circle cx="108.3" cy="92.9" r=".25"/>
<circle cx="108.3" cy="92" r=".25"/>
<circle cx="108.3" cy="91.1" r=".24"/>
<circle cx="108.3" cy="90.2" r=".25"/>
<circle cx="108.3" cy="89.3" r=".25"/>
<circle cx="108.3" cy="88.3" r=".25"/>
<circle cx="108.3" cy="87.4" r=".25"/>
<circle cx="108.3" cy="86.5" r=".25"/>
<circle cx="108.3" cy="85.6" r=".25"/>
<circle cx="108.3" cy="84.7" r=".25"/>
<circle cx="108.3" cy="83.8" r=".25"/>
<circle cx="108.3" cy="82.8" r=".25"/>
<circle cx="108.3" cy="81.9" r=".25"/>
<circle cx="108.3" cy="81" r=".24"/>
<circle cx="108.3" cy="80.1" r=".25"/>
<circle cx="108.3" cy="79.2" r=".25"/>
<circle cx="103.4" cy="74.4" r=".26"/>
<circle cx="103.4" cy="73.4" r=".26"/>
<circle cx="103.4" cy="72.5" r=".26"/>
<circle cx="103.4" cy="71.5" r=".26"/>
<circle cx="103.4" cy="70.6" r=".26"/>
<circle cx="103.5" cy="69.6" r=".26"/>
<circle cx="103.5" cy="68.6" r=".26"/>
<circle cx="103.5" cy="67.7" r=".26"/>
<circle cx="103.5" cy="66.7" r=".26"/>
<circle cx="103.5" cy="65.8" r=".26"/>
<circle cx="103.5" cy="64.8" r=".26"/>
<circle cx="103.5" cy="63.9" r=".26"/>
<circle cx="103.5" cy="62.9" r=".26"/>
<circle cx="103.5" cy="61.9" r=".26"/>
<circle cx="103.6" cy="61" r=".26"/>
<circle cx="103.6" cy="60" r=".26"/>
<circle cx="103.6" cy="59.1" r=".26"/>
<circle cx="103.6" cy="58.1" r=".26"/>
<circle cx="103.6" cy="57.1" r=".26"/>
</g>
<g fill="#800000" stroke="#800000" stroke-width=".2">
<path d="M103.2 74.4a.23 .23 0 0 1 .2-.1 .23 .23 0 0 1 .2 .2 .22 .22 0 0 1 .2 .3 .22 .22 0 0 1-.3 .2l-.3-.3z" fill-rule="evenodd"/>
<circle cx="103.3" cy="126.3" r=".25"/>
<circle cx="104.3" cy="126.2" r=".25"/>
<circle cx="105.2" cy="125.9" r=".25"/>
<circle cx="106" cy="125.5" r=".25"/>
<circle cx="106.8" cy="124.8" r=".25"/>
<circle cx="107.4" cy="124.1" r=".24"/>
<circle cx="107.8" cy="123.3" r=".25"/>
<circle cx="108.1" cy="122.3" r=".25"/>
<circle cx="108.2" cy="121.4" r=".25"/>
<circle cx="108.2" cy="79" r=".24"/>
<circle cx="108.1" cy="78.1" r=".24"/>
<circle cx="107.8" cy="77.2" r=".24"/>
<circle cx="107.4" cy="76.4" r=".24"/>
<circle cx="106.7" cy="75.7" r=".24"/>
<circle cx="105.9" cy="75.2" r=".24"/>
<circle cx="105.1" cy="74.9" r=".24"/>
<circle cx="104.1" cy="74.7" r=".24"/>
</g>
<circle cx="117.8" cy="62.5" r=".76" fill="#008000" stroke="#008000" stroke-width=".2"/>
<circle cx="117.8" cy="62.5" r=".51" fill="#fff" stroke="#000" stroke-width=".2"/>
<circle cx="117.8" cy="59.9" r=".76" fill="#008000" stroke="#008000" stroke-width=".2"/>
<circle cx="117.8" cy="59.9" r=".51" fill="#fff" stroke="#000" stroke-width=".2"/>
<circle cx="120.3" cy="62.5" r=".76" fill="#008000" stroke="#008000" stroke-width=".2"/>
<circle cx="120.3" cy="62.5" r=".51" fill="#fff" stroke="#000" stroke-width=".2"/>
<circle cx="120.3" cy="59.9" r=".76" fill="#008000" stroke="#008000" stroke-width=".2"/>
<circle cx="120.3" cy="59.9" r=".51" fill="#fff" stroke="#000" stroke-width=".2"/>
<circle cx="122.8" cy="62.5" r=".76" fill="#008000" stroke="#008000" stroke-width=".2"/>
<circle cx="122.8" cy="62.5" r=".51" fill="#fff" stroke="#000" stroke-width=".2"/>
<circle cx="122.8" cy="59.9" r=".76" fill="#008000" stroke="#008000" stroke-width=".2"/>
<circle cx="122.8" cy="59.9" r=".51" fill="#fff" stroke="#000" stroke-width=".2"/>
<circle cx="125.4" cy="62.5" r=".76" fill="#008000" stroke="#008000" stroke-width=".2"/>
<circle cx="125.4" cy="62.5" r=".51" fill="#fff" stroke="#000" stroke-width=".2"/>
<circle cx="125.4" cy="59.9" r=".76" fill="#008000" stroke="#008000" stroke-width=".2"/>
<circle cx="125.4" cy="59.9" r=".51" fill="#fff" stroke="#000" stroke-width=".2"/>
<circle cx="127.9" cy="62.5" r=".76" fill="#008000" stroke="#008000" stroke-width=".2"/>
<circle cx="127.9" cy="62.5" r=".51" fill="#fff" stroke="#000" stroke-width=".2"/>
<circle cx="127.9" cy="59.9" r=".76" fill="#008000" stroke="#008000" stroke-width=".2"/>
<circle cx="127.9" cy="59.9" r=".51" fill="#fff" stroke="#000" stroke-width=".2"/>
<circle cx="130.5" cy="62.5" r=".76" fill="#008000" stroke="#008000" stroke-width=".2"/>
<circle cx="130.5" cy="62.5" r=".51" fill="#fff" stroke="#000" stroke-width=".2"/>
<circle cx="130.5" cy="59.9" r=".76" fill="#008000" stroke="#008000" stroke-width=".2"/>
<circle cx="130.5" cy="59.9" r=".51" fill="#fff" stroke="#000" stroke-width=".2"/>
<circle cx="133" cy="62.5" r=".76" fill="#008000" stroke="#008000" stroke-width=".2"/>
<circle cx="133" cy="62.5" r=".51" fill="#fff" stroke="#000" stroke-width=".2"/>
<circle cx="133" cy="59.9" r=".76" fill="#008000" stroke="#008000" stroke-width=".2"/>
<circle cx="133" cy="59.9" r=".51" fill="#fff" stroke="#000" stroke-width=".2"/>
<circle cx="135.5" cy="62.5" r=".76" fill="#008000" stroke="#008000" stroke-width=".2"/>
<circle cx="135.5" cy="62.5" r=".51" fill="#fff" stroke="#000" stroke-width=".2"/>
<circle cx="135.5" cy="59.9" r=".76" fill="#008000" stroke="#008000" stroke-width=".2"/>
<circle cx="135.5" cy="59.9" r=".51" fill="#fff" stroke="#000" stroke-width=".2"/>
<circle cx="138.1" cy="62.5" r=".76" fill="#008000" stroke="#008000" stroke-width=".2"/>
<circle cx="138.1" cy="62.5" r=".51" fill="#fff" stroke="#000" stroke-width=".2"/>
<circle cx="138.1" cy="59.9" r=".76" fill="#008000" stroke="#008000" stroke-width=".2"/>
<circle cx="138.1" cy="59.9" r=".51" fill="#fff" stroke="#000" stroke-width=".2"/>
<circle cx="140.6" cy="62.5" r=".76" fill="#008000" stroke="#008000" stroke-width=".2"/>
<circle cx="140.6" cy="62.5" r=".51" fill="#fff" stroke="#000" stroke-width=".2"/>
<circle cx="140.6" cy="59.9" r=".76" fill="#008000" stroke="#008000" stroke-width=".2"/>
<circle cx="140.6" cy="59.9" r=".51" fill="#fff" stroke="#000" stroke-width=".2"/>
<circle cx="143.1" cy="62.5" r=".76" fill="#008000" stroke="#008000" stroke-width=".2"/>
<circle cx="143.1" cy="62.5" r=".51" fill="#fff" stroke="#000" stroke-width=".2"/>
<circle cx="143.1" cy="59.9" r=".76" fill="#008000" stroke="#008000" stroke-width=".2"/>
<circle cx="143.1" cy="59.9" r=".51" fill="#fff" stroke="#000" stroke-width=".2"/>
<circle cx="145.7" cy="62.5" r=".76" fill="#008000" stroke="#008000" stroke-width=".2"/>
<circle cx="145.7" cy="62.5" r=".51" fill="#fff" stroke="#000" stroke-width=".2"/>
<circle cx="145.7" cy="59.9" r=".76" fill="#008000" stroke="#008000" stroke-width=".2"/>
<circle cx="145.7" cy="59.9" r=".51" fill="#fff" stroke="#000" stroke-width=".2"/>
<circle cx="148.2" cy="62.5" r=".76" fill="#008000" stroke="#008000" stroke-width=".2"/>
<circle cx="148.2" cy="62.5" r=".51" fill="#fff" stroke="#000" stroke-width=".2"/>
<circle cx="148.2" cy="59.9" r=".76" fill="#008000" stroke="#008000" stroke-width=".2"/>
<circle cx="148.2" cy="59.9" r=".51" fill="#fff" stroke="#000" stroke-width=".2"/>
<circle cx="150.7" cy="62.5" r=".76" fill="#008000" stroke="#008000" stroke-width=".2"/>
<circle cx="150.7" cy="62.5" r=".51" fill="#fff" stroke="#000" stroke-width=".2"/>
<circle cx="150.7" cy="59.9" r=".76" fill="#008000" stroke="#008000" stroke-width=".2"/>
<circle cx="150.7" cy="59.9" r=".51" fill="#fff" stroke="#000" stroke-width=".2"/>
<circle cx="153.3" cy="62.5" r=".76" fill="#008000" stroke="#008000" stroke-width=".2"/>
<circle cx="153.3" cy="62.5" r=".51" fill="#fff" stroke="#000" stroke-width=".2"/>
<circle cx="153.3" cy="59.9" r=".76" fill="#008000" stroke="#008000" stroke-width=".2"/>
<circle cx="153.3" cy="59.9" r=".51" fill="#fff" stroke="#000" stroke-width=".2"/>
<circle cx="155.8" cy="62.5" r=".76" fill="#008000" stroke="#008000" stroke-width=".2"/>
<circle cx="155.8" cy="62.5" r=".51" fill="#fff" stroke="#000" stroke-width=".2"/>
<circle cx="155.8" cy="59.9" r=".76" fill="#008000" stroke="#008000" stroke-width=".2"/>
<circle cx="155.8" cy="59.9" r=".51" fill="#fff" stroke="#000" stroke-width=".2"/>
<circle cx="158.4" cy="62.5" r=".76" fill="#008000" stroke="#008000" stroke-width=".2"/>
<circle cx="158.4" cy="62.5" r=".51" fill="#fff" stroke="#000" stroke-width=".2"/>
<circle cx="158.4" cy="59.9" r=".76" fill="#008000" stroke="#008000" stroke-width=".2"/>
<circle cx="158.4" cy="59.9" r=".51" fill="#fff" stroke="#000" stroke-width=".2"/>
<circle cx="160.9" cy="62.5" r=".76" fill="#008000" stroke="#008000" stroke-width=".2"/>
<circle cx="160.9" cy="62.5" r=".51" fill="#fff" stroke="#000" stroke-width=".2"/>
<circle cx="160.9" cy="59.9" r=".76" fill="#008000" stroke="#008000" stroke-width=".2"/>
<circle cx="160.9" cy="59.9" r=".51" fill="#fff" stroke="#000" stroke-width=".2"/>
<circle cx="163.4" cy="62.5" r=".76" fill="#008000" stroke="#008000" stroke-width=".2"/>
<circle cx="163.4" cy="62.5" r=".51" fill="#fff" stroke="#000" stroke-width=".2"/>
<circle cx="163.4" cy="59.9" r=".76" fill="#008000" stroke="#008000" stroke-width=".2"/>
<circle cx="163.4" cy="59.9" r=".51" fill="#fff" stroke="#000" stroke-width=".2"/>
<circle cx="166" cy="62.5" r=".76" fill="#008000" stroke="#008000" stroke-width=".2"/>
<circle cx="166" cy="62.5" r=".51" fill="#fff" stroke="#000" stroke-width=".2"/>
<circle cx="166" cy="59.9" r=".76" fill="#008000" stroke="#008000" stroke-width=".2"/>
<circle cx="166" cy="59.9" r=".51" fill="#fff" stroke="#000" stroke-width=".2"/>
<circle cx="168.5" cy="62.5" r=".76" fill="#008000" stroke="#008000" stroke-width=".2"/>
<circle cx="168.5" cy="62.5" r=".51" fill="#fff" stroke="#000" stroke-width=".2"/>
<circle cx="168.5" cy="59.9" r=".76" fill="#008000" stroke="#008000" stroke-width=".2"/>
<circle cx="168.5" cy="59.9" r=".51" fill="#fff" stroke="#000" stroke-width=".2"/>
<circle cx="171.1" cy="62.5" r=".76" fill="#008000" stroke="#008000" stroke-width=".2"/>
<circle cx="171.1" cy="62.5" r=".51" fill="#fff" stroke="#000" stroke-width=".2"/>
<circle cx="171.1" cy="59.9" r=".76" fill="#008000" stroke="#008000" stroke-width=".2"/>
<circle cx="171.1" cy="59.9" r=".51" fill="#fff" stroke="#000" stroke-width=".2"/>
<circle cx="173.6" cy="62.5" r=".76" fill="#008000" stroke="#008000" stroke-width=".2"/>
<circle cx="173.6" cy="62.5" r=".51" fill="#fff" stroke="#000" stroke-width=".2"/>
<circle cx="173.6" cy="59.9" r=".76" fill="#008000" stroke="#008000" stroke-width=".2"/>
<circle cx="173.6" cy="59.9" r=".51" fill="#fff" stroke="#000" stroke-width=".2"/>
<circle cx="176.1" cy="62.5" r=".76" fill="#008000" stroke="#008000" stroke-width=".2"/>
<circle cx="176.1" cy="62.5" r=".51" fill="#fff" stroke="#000" stroke-width=".2"/>
<circle cx="176.1" cy="59.9" r=".76" fill="#008000" stroke="#008000" stroke-width=".2"/>
<circle cx="176.1" cy="59.9" r=".51" fill="#fff" stroke="#000" stroke-width=".2"/>
<circle cx="178.7" cy="62.5" r=".76" fill="#008000" stroke="#008000" stroke-width=".2"/>
<circle cx="178.7" cy="62.5" r=".51" fill="#fff" stroke="#000" stroke-width=".2"/>
<circle cx="178.7" cy="59.9" r=".76" fill="#008000" stroke="#008000" stroke-width=".2"/>
<circle cx="178.7" cy="59.9" r=".51" fill="#fff" stroke="#000" stroke-width=".2"/>
<circle cx="181.2" cy="62.5" r=".76" fill="#008000" stroke="#008000" stroke-width=".2"/>
<circle cx="181.2" cy="62.5" r=".51" fill="#fff" stroke="#000" stroke-width=".2"/>
<circle cx="181.2" cy="59.9" r=".76" fill="#008000" stroke="#008000" stroke-width=".2"/>
<circle cx="181.2" cy="59.9" r=".51" fill="#fff" stroke="#000" stroke-width=".2"/>
<circle cx="117.8" cy="67.5" r=".76" fill="#008000" stroke="#008000" stroke-width=".2"/>
<circle cx="117.8" cy="67.5" r=".51" fill="#fff" stroke="#000" stroke-width=".2"/>
<circle cx="117.8" cy="65" r=".76" fill="#008000" stroke="#008000" stroke-width=".2"/>
<circle cx="117.8" cy="65" r=".51" fill="#fff" stroke="#000" stroke-width=".2"/>
<circle cx="120.3" cy="67.5" r=".76" fill="#008000" stroke="#008000" stroke-width=".2"/>
<circle cx="120.3" cy="67.5" r=".51" fill="#fff" stroke="#000" stroke-width=".2"/>
<circle cx="120.3" cy="65" r=".76" fill="#008000" stroke="#008000" stroke-width=".2"/>
<circle cx="120.3" cy="65" r=".51" fill="#fff" stroke="#000" stroke-width=".2"/>
<circle cx="122.8" cy="67.5" r=".76" fill="#008000" stroke="#008000" stroke-width=".2"/>
<circle cx="122.8" cy="67.5" r=".51" fill="#fff" stroke="#000" stroke-width=".2"/>
<circle cx="122.8" cy="65" r=".76" fill="#008000" stroke="#008000" stroke-width=".2"/>
<circle cx="122.8" cy="65" r=".51" fill="#fff" stroke="#000" stroke-width=".2"/>
<circle cx="125.3" cy="67.5" r=".76" fill="#008000" stroke="#008000" stroke-width=".2"/>
<circle cx="125.3" cy="67.5" r=".51" fill="#fff" stroke="#000" stroke-width=".2"/>
<circle cx="125.3" cy="65" r=".76" fill="#008000" stroke="#008000" stroke-width=".2"/>
<circle cx="125.3" cy="65" r=".51" fill="#fff" stroke="#000" stroke-width=".2"/>
<circle cx="127.9" cy="67.5" r=".76" fill="#008000" stroke="#008000" stroke-width=".2"/>
<circle cx="127.9" cy="67.5" r=".51" fill="#fff" stroke="#000" stroke-width=".2"/>
<circle cx="127.9" cy="65" r=".76" fill="#008000" stroke="#008000" stroke-width=".2"/>
<circle cx="127.9" cy="65" r=".51" fill="#fff" stroke="#000" stroke-width=".2"/>
<circle cx="130.4" cy="67.5" r=".76" fill="#008000" stroke="#008000" stroke-width=".2"/>
<circle cx="130.4" cy="67.5" r=".51" fill="#fff" stroke="#000" stroke-width=".2"/>
<circle cx="130.4" cy="65" r=".76" fill="#008000" stroke="#008000" stroke-width=".2"/>
<circle cx="130.4" cy="65" r=".51" fill="#fff" stroke="#000" stroke-width=".2"/>
<circle cx="133" cy="67.5" r=".76" fill="#008000" stroke="#008000" stroke-width=".2"/>
<circle cx="133" cy="67.5" r=".51" fill="#fff" stroke="#000" stroke-width=".2"/>
<circle cx="133" cy="65" r=".76" fill="#008000" stroke="#008000" stroke-width=".2"/>
<circle cx="133" cy="65" r=".51" fill="#fff" stroke="#000" stroke-width=".2"/>
<circle cx="135.5" cy="67.5" r=".76" fill="#008000" stroke="#008000" stroke-width=".2"/>
<circle cx="135.5" cy="67.5" r=".51" fill="#fff" stroke="#000" stroke-width=".2"/>
<circle cx="135.5" cy="65" r=".76" fill="#008000" stroke="#008000" stroke-width=".2"/>
<circle cx="135.5" cy="65" r=".51" fill="#fff" stroke="#000" stroke-width=".2"/>
<circle cx="138" cy="67.5" r=".76" fill="#008000" stroke="#008000" stroke-width=".2"/>
<circle cx="138" cy="67.5" r=".51" fill="#fff" stroke="#000" stroke-width=".2"/>
<circle cx="138" cy="65" r=".76" fill="#008000" stroke="#008000" stroke-width=".2"/>
<circle cx="138" cy="65" r=".51" fill="#fff" stroke="#000" stroke-width=".2"/>
<circle cx="140.6" cy="67.5" r=".76" fill="#008000" stroke="#008000" stroke-width=".2"/>
<circle cx="140.6" cy="67.5" r=".51" fill="#fff" stroke="#000" stroke-width=".2"/>
<circle cx="140.6" cy="65" r=".76" fill="#008000" stroke="#008000" stroke-width=".2"/>
<circle cx="140.6" cy="65" r=".51" fill="#fff" stroke="#000" stroke-width=".2"/>
<circle cx="143.1" cy="67.5" r=".76" fill="#008000" stroke="#008000" stroke-width=".2"/>
<circle cx="143.1" cy="67.5" r=".51" fill="#fff" stroke="#000" stroke-width=".2"/>
<circle cx="143.1" cy="65" r=".76" fill="#008000" stroke="#008000" stroke-width=".2"/>
<circle cx="143.1" cy="65" r=".51" fill="#fff" stroke="#000" stroke-width=".2"/>
<circle cx="145.7" cy="67.5" r=".76" fill="#008000" stroke="#008000" stroke-width=".2"/>
<circle cx="145.7" cy="67.5" r=".51" fill="#fff" stroke="#000" stroke-width=".2"/>
<circle cx="145.7" cy="65" r=".76" fill="#008000" stroke="#008000" stroke-width=".2"/>
<circle cx="145.7" cy="65" r=".51" fill="#fff" stroke="#000" stroke-width=".2"/>
<circle cx="148.2" cy="67.5" r=".76" fill="#008000" stroke="#008000" stroke-width=".2"/>
<circle cx="148.2" cy="67.5" r=".51" fill="#fff" stroke="#000" stroke-width=".2"/>
<circle cx="148.2" cy="65" r=".76" fill="#008000" stroke="#008000" stroke-width=".2"/>
<circle cx="148.2" cy="65" r=".51" fill="#fff" stroke="#000" stroke-width=".2"/>
<circle cx="150.7" cy="67.5" r=".76" fill="#008000" stroke="#008000" stroke-width=".2"/>
<circle cx="150.7" cy="67.5" r=".51" fill="#fff" stroke="#000" stroke-width=".2"/>
<circle cx="150.7" cy="65" r=".76" fill="#008000" stroke="#008000" stroke-width=".2"/>
<circle cx="150.7" cy="65" r=".51" fill="#fff" stroke="#000" stroke-width=".2"/>
<circle cx="153.3" cy="67.5" r=".76" fill="#008000" stroke="#008000" stroke-width=".2"/>
<circle cx="153.3" cy="67.5" r=".51" fill="#fff" stroke="#000" stroke-width=".2"/>
<circle cx="153.3" cy="65" r=".76" fill="#008000" stroke="#008000" stroke-width=".2"/>
<circle cx="153.3" cy="65" r=".51" fill="#fff" stroke="#000" stroke-width=".2"/>
<circle cx="155.8" cy="67.5" r=".76" fill="#008000" stroke="#008000" stroke-width=".2"/>
<circle cx="155.8" cy="67.5" r=".51" fill="#fff" stroke="#000" stroke-width=".2"/>
<circle cx="155.8" cy="65" r=".76" fill="#008000" stroke="#008000" stroke-width=".2"/>
<circle cx="155.8" cy="65" r=".51" fill="#fff" stroke="#000" stroke-width=".2"/>
<circle cx="158.4" cy="67.5" r=".76" fill="#008000" stroke="#008000" stroke-width=".2"/>
<circle cx="158.4" cy="67.5" r=".51" fill="#fff" stroke="#000" stroke-width=".2"/>
<circle cx="158.4" cy="65" r=".76" fill="#008000" stroke="#008000" stroke-width=".2"/>
<circle cx="158.4" cy="65" r=".51" fill="#fff" stroke="#000" stroke-width=".2"/>
<circle cx="160.9" cy="67.5" r=".76" fill="#008000" stroke="#008000" stroke-width=".2"/>
<circle cx="160.9" cy="67.5" r=".51" fill="#fff" stroke="#000" stroke-width=".2"/>
<circle cx="160.9" cy="65" r=".76" fill="#008000" stroke="#008000" stroke-width=".2"/>
<circle cx="160.9" cy="65" r=".51" fill="#fff" stroke="#000" stroke-width=".2"/>
<circle cx="163.4" cy="67.5" r=".76" fill="#008000" stroke="#008000" stroke-width=".2"/>
<circle cx="163.4" cy="67.5" r=".51" fill="#fff" stroke="#000" stroke-width=".2"/>
<circle cx="163.4" cy="65" r=".76" fill="#008000" stroke="#008000" stroke-width=".2"/>
<circle cx="163.4" cy="65" r=".51" fill="#fff" stroke="#000" stroke-width=".2"/>
<circle cx="166" cy="67.5" r=".76" fill="#008000" stroke="#008000" stroke-width=".2"/>
<circle cx="166" cy="67.5" r=".51" fill="#fff" stroke="#000" stroke-width=".2"/>
<circle cx="166" cy="65" r=".76" fill="#008000" stroke="#008000" stroke-width=".2"/>
<circle cx="166" cy="65" r=".51" fill="#fff" stroke="#000" stroke-width=".2"/>
<circle cx="168.5" cy="67.5" r=".76" fill="#008000" stroke="#008000" stroke-width=".2"/>
<circle cx="168.5" cy="67.5" r=".51" fill="#fff" stroke="#000" stroke-width=".2"/>
<circle cx="168.5" cy="65" r=".76" fill="#008000" stroke="#008000" stroke-width=".2"/>
<circle cx="168.5" cy="65" r=".51" fill="#fff" stroke="#000" stroke-width=".2"/>
<circle cx="171.1" cy="67.5" r=".76" fill="#008000" stroke="#008000" stroke-width=".2"/>
<circle cx="171.1" cy="67.5" r=".51" fill="#fff" stroke="#000" stroke-width=".2"/>
<circle cx="171.1" cy="65" r=".76" fill="#008000" stroke="#008000" stroke-width=".2"/>
<circle cx="171.1" cy="65" r=".51" fill="#fff" stroke="#000" stroke-width=".2"/>
<circle cx="173.6" cy="67.5" r=".76" fill="#008000" stroke="#008000" stroke-width=".2"/>
<circle cx="173.6" cy="67.5" r=".51" fill="#fff" stroke="#000" stroke-width=".2"/>
<circle cx="173.6" cy="65" r=".76" fill="#008000" stroke="#008000" stroke-width=".2"/>
<circle cx="173.6" cy="65" r=".51" fill="#fff" stroke="#000" stroke-width=".2"/>
<circle cx="176.1" cy="67.5" r=".76" fill="#008000" stroke="#008000" stroke-width=".2"/>
<circle cx="176.1" cy="67.5" r=".51" fill="#fff" stroke="#000" stroke-width=".2"/>
<circle cx="176.1" cy="65" r=".76" fill="#008000" stroke="#008000" stroke-width=".2"/>
<circle cx="176.1" cy="65" r=".51" fill="#fff" stroke="#000" stroke-width=".2"/>
<circle cx="178.7" cy="67.5" r=".76" fill="#008000" stroke="#008000" stroke-width=".2"/>
<circle cx="178.7" cy="67.5" r=".51" fill="#fff" stroke="#000" stroke-width=".2"/>
<circle cx="178.7" cy="65" r=".76" fill="#008000" stroke="#008000" stroke-width=".2"/>
<circle cx="178.7" cy="65" r=".51" fill="#fff" stroke="#000" stroke-width=".2"/>
<circle cx="181.2" cy="67.5" r=".76" fill="#008000" stroke="#008000" stroke-width=".2"/>
<circle cx="181.2" cy="67.5" r=".51" fill="#fff" stroke="#000" stroke-width=".2"/>
<circle cx="181.2" cy="65" r=".76" fill="#008000" stroke="#008000" stroke-width=".2"/>
<circle cx="181.2" cy="65" r=".51" fill="#fff" stroke="#000" stroke-width=".2"/>
<circle cx="186.4" cy="100.8" r=".51" fill="#008000" stroke="#008000" stroke-width=".2"/>
<circle cx="186.4" cy="100.8" r=".25" fill="#fff" stroke="#000" stroke-width=".2"/>
<circle cx="188.4" cy="100.8" r=".51" fill="#008000" stroke="#008000" stroke-width=".2"/>
<circle cx="188.4" cy="100.8" r=".25" fill="#fff" stroke="#000" stroke-width=".2"/>
<circle cx="186.4" cy="98.8" r=".51" fill="#008000" stroke="#008000" stroke-width=".2"/>
<circle cx="186.4" cy="98.8" r=".25" fill="#fff" stroke="#000" stroke-width=".2"/>
<circle cx="188.4" cy="98.8" r=".51" fill="#008000" stroke="#008000" stroke-width=".2"/>
<circle cx="188.4" cy="98.8" r=".25" fill="#fff" stroke="#000" stroke-width=".2"/>
<circle cx="186.4" cy="96.9" r=".51" fill="#008000" stroke="#008000" stroke-width=".2"/>
<circle cx="186.4" cy="96.9" r=".25" fill="#fff" stroke="#000" stroke-width=".2"/>
<circle cx="188.4" cy="96.9" r=".51" fill="#008000" stroke="#008000" stroke-width=".2"/>
<circle cx="188.4" cy="96.9" r=".25" fill="#fff" stroke="#000" stroke-width=".2"/>
<circle cx="186.4" cy="94.8" r=".51" fill="#008000" stroke="#008000" stroke-width=".2"/>
<circle cx="186.4" cy="94.8" r=".25" fill="#fff" stroke="#000" stroke-width=".2"/>
<circle cx="188.4" cy="94.8" r=".51" fill="#008000" stroke="#008000" stroke-width=".2"/>
<circle cx="188.4" cy="94.8" r=".25" fill="#fff" stroke="#000" stroke-width=".2"/>
<circle cx="186.4" cy="92.9" r=".51" fill="#008000" stroke="#008000" stroke-width=".2"/>
<circle cx="186.4" cy="92.9" r=".25" fill="#fff" stroke="#000" stroke-width=".2"/>
<circle cx="188.4" cy="92.9" r=".51" fill="#008000" stroke="#008000" stroke-width=".2"/>
<circle cx="188.4" cy="92.9" r=".25" fill="#fff" stroke="#000" stroke-width=".2"/>
<circle cx="186.4" cy="90.8" r=".51" fill="#008000" stroke="#008000" stroke-width=".2"/>
<circle cx="186.4" cy="90.8" r=".25" fill="#fff" stroke="#000" stroke-width=".2"/>
<circle cx="188.4" cy="90.8" r=".51" fill="#008000" stroke="#008000" stroke-width=".2"/>
<circle cx="188.4" cy="90.8" r=".25" fill="#fff" stroke="#000" stroke-width=".2"/>
<circle cx="186.4" cy="88.9" r=".51" fill="#008000" stroke="#008000" stroke-width=".2"/>
<circle cx="186.4" cy="88.9" r=".25" fill="#fff" stroke="#000" stroke-width=".2"/>
<circle cx="188.4" cy="88.9" r=".51" fill="#008000" stroke="#008000" stroke-width=".2"/>
<circle cx="188.4" cy="88.9" r=".25" fill="#fff" stroke="#000" stroke-width=".2"/>
<circle cx="186.4" cy="86.8" r=".51" fill="#008000" stroke="#008000" stroke-width=".2"/>
<circle cx="186.4" cy="86.8" r=".25" fill="#fff" stroke="#000" stroke-width=".2"/>
<circle cx="188.4" cy="86.8" r=".51" fill="#008000" stroke="#008000" stroke-width=".2"/>
<circle cx="188.4" cy="86.8" r=".25" fill="#fff" stroke="#000" stroke-width=".2"/>
<circle cx="186.4" cy="119.1" r=".51" fill="#008000" stroke="#008000" stroke-width=".2"/>
<circle cx="186.4" cy="119.1" r=".25" fill="#fff" stroke="#000" stroke-width=".2"/>
<circle cx="188.3" cy="119.1" r=".51" fill="#008000" stroke="#008000" stroke-width=".2"/>
<circle cx="188.3" cy="119.1" r=".25" fill="#fff" stroke="#000" stroke-width=".2"/>
<circle cx="186.4" cy="117.1" r=".51" fill="#008000" stroke="#008000" stroke-width=".2"/>
<circle cx="186.4" cy="117.1" r=".25" fill="#fff" stroke="#000" stroke-width=".2"/>
<circle cx="188.3" cy="117.1" r=".51" fill="#008000" stroke="#008000" stroke-width=".2"/>
<circle cx="188.3" cy="117.1" r=".25" fill="#fff" stroke="#000" stroke-width=".2"/>
<circle cx="186.4" cy="115.1" r=".51" fill="#008000" stroke="#008000" stroke-width=".2"/>
<circle cx="186.4" cy="115.1" r=".25" fill="#fff" stroke="#000" stroke-width=".2"/>
<circle cx="188.3" cy="115.1" r=".51" fill="#008000" stroke="#008000" stroke-width=".2"/>
<circle cx="188.3" cy="115.1" r=".25" fill="#fff" stroke="#000" stroke-width=".2"/>
<circle cx="186.4" cy="113.1" r=".51" fill="#008000" stroke="#008000" stroke-width=".2"/>
<circle cx="186.4" cy="113.1" r=".25" fill="#fff" stroke="#000" stroke-width=".2"/>
<circle cx="188.3" cy="113.1" r=".51" fill="#008000" stroke="#008000" stroke-width=".2"/>
<circle cx="188.3" cy="113.1" r=".25" fill="#fff" stroke="#000" stroke-width=".2"/>
<circle cx="186.4" cy="111.1" r=".51" fill="#008000" stroke="#008000" stroke-width=".2"/>
<circle cx="186.4" cy="111.1" r=".25" fill="#fff" stroke="#000" stroke-width=".2"/>
<circle cx="188.3" cy="111.1" r=".51" fill="#008000" stroke="#008000" stroke-width=".2"/>
<circle cx="188.3" cy="111.1" r=".25" fill="#fff" stroke="#000" stroke-width=".2"/>
<circle cx="186.4" cy="109.1" r=".51" fill="#008000" stroke="#008000" stroke-width=".2"/>
<circle cx="186.4" cy="109.1" r=".25" fill="#fff" stroke="#000" stroke-width=".2"/>
<circle cx="188.3" cy="109.1" r=".51" fill="#008000" stroke="#008000" stroke-width=".2"/>
<circle cx="188.3" cy="109.1" r=".25" fill="#fff" stroke="#000" stroke-width=".2"/>
<circle cx="186.4" cy="107.1" r=".51" fill="#008000" stroke="#008000" stroke-width=".2"/>
<circle cx="186.4" cy="107.1" r=".25" fill="#fff" stroke="#000" stroke-width=".2"/>
<circle cx="188.3" cy="107.1" r=".51" fill="#008000" stroke="#008000" stroke-width=".2"/>
<circle cx="188.3" cy="107.1" r=".25" fill="#fff" stroke="#000" stroke-width=".2"/>
<circle cx="186.4" cy="105.1" r=".51" fill="#008000" stroke="#008000" stroke-width=".2"/>
<circle cx="186.4" cy="105.1" r=".25" fill="#fff" stroke="#000" stroke-width=".2"/>
<circle cx="188.3" cy="105.1" r=".51" fill="#008000" stroke="#008000" stroke-width=".2"/>
<circle cx="188.3" cy="105.1" r=".25" fill="#fff" stroke="#000" stroke-width=".2"/>
<circle cx="145.4" cy="111.1" r=".66" fill="#008000" stroke="#008000" stroke-width=".2"/>
<circle cx="145.4" cy="111.1" r=".4" fill="#fff" stroke="#000" stroke-width=".2"/>
<circle cx="145.4" cy="113.6" r=".66" fill="#008000" stroke="#008000" stroke-width=".2"/>
<circle cx="145.4" cy="113.6" r=".4" fill="#fff" stroke="#000" stroke-width=".2"/>
<circle cx="127.7" cy="86.8" r=".51" fill="#008000" stroke="#008000" stroke-width=".2"/>
<circle cx="127.7" cy="86.8" r=".3" fill="#fff" stroke="#000" stroke-width=".2"/>
<circle cx="132" cy="87" r=".51" fill="#008000" stroke="#008000" stroke-width=".2"/>
<circle cx="132" cy="87" r=".3" fill="#fff" stroke="#000" stroke-width=".2"/>
<circle cx="166.4" cy="90.2" r=".51" fill="#008000" stroke="#008000" stroke-width=".2"/>
<circle cx="166.4" cy="90.2" r=".3" fill="#fff" stroke="#000" stroke-width=".2"/>
<circle cx="179.8" cy="103.3" r=".51" fill="#008000" stroke="#008000" stroke-width=".2"/>
<circle cx="179.8" cy="103.3" r=".3" fill="#fff" stroke="#000" stroke-width=".2"/>
<circle cx="132.4" cy="75.3" r=".51" fill="#008000" stroke="#008000" stroke-width=".2"/>
<circle cx="132.4" cy="75.3" r=".3" fill="#fff" stroke="#000" stroke-width=".2"/>
<circle cx="151.4" cy="75.4" r=".51" fill="#008000" stroke="#008000" stroke-width=".2"/>
<circle cx="151.4" cy="75.4" r=".3" fill="#fff" stroke="#000" stroke-width=".2"/>
<circle cx="164.8" cy="103.4" r=".51" fill="#008000" stroke="#008000" stroke-width=".2"/>
<circle cx="164.8" cy="103.4" r=".3" fill="#fff" stroke="#000" stroke-width=".2"/>
<circle cx="164.9" cy="109.5" r=".51" fill="#008000" stroke="#008000" stroke-width=".2"/>
<circle cx="164.9" cy="109.5" r=".3" fill="#fff" stroke="#000" stroke-width=".2"/>
<circle cx="132.3" cy="73.9" r=".51" fill="#008000" stroke="#008000" stroke-width=".2"/>
<circle cx="132.3" cy="73.9" r=".3" fill="#fff" stroke="#000" stroke-width=".2"/>
<circle cx="149.4" cy="74.3" r=".51" fill="#008000" stroke="#008000" stroke-width=".2"/>
<circle cx="149.4" cy="74.3" r=".3" fill="#fff" stroke="#000" stroke-width=".2"/>
<circle cx="165.4" cy="101.2" r=".51" fill="#008000" stroke="#008000" stroke-width=".2"/>
<circle cx="165.4" cy="101.2" r=".3" fill="#fff" stroke="#000" stroke-width=".2"/>
<circle cx="167.1" cy="109.1" r=".51" fill="#008000" stroke="#008000" stroke-width=".2"/>
<circle cx="167.1" cy="109.1" r=".3" fill="#fff" stroke="#000" stroke-width=".2"/>
<circle cx="167.1" cy="114.1" r=".51" fill="#008000" stroke="#008000" stroke-width=".2"/>
<circle cx="167.1" cy="114.1" r=".3" fill="#fff" stroke="#000" stroke-width=".2"/>
<circle cx="166.8" cy="79.9" r=".51" fill="#008000" stroke="#008000" stroke-width=".2"/>
<circle cx="166.8" cy="79.9" r=".3" fill="#fff" stroke="#000" stroke-width=".2"/>
<circle cx="169.1" cy="79.8" r=".51" fill="#008000" stroke="#008000" stroke-width=".2"/>
<circle cx="169.1" cy="79.8" r=".3" fill="#fff" stroke="#000" stroke-width=".2"/>
<circle cx="167.4" cy="100.2" r=".44" fill="#008000" stroke="#008000" stroke-width=".2"/>
<circle cx="167.4" cy="100.2" r=".25" fill="#fff" stroke="#000" stroke-width=".2"/>
<circle cx="186.5" cy="65.5" r=".44" fill="#008000" stroke="#008000" stroke-width=".2"/>
<circle cx="186.5" cy="65.5" r=".25" fill="#fff" stroke="#000" stroke-width=".2"/>
<circle cx="124.1" cy="114.3" r=".51" fill="#008000" stroke="#008000" stroke-width=".2"/>
<circle cx="124.1" cy="114.3" r=".3" fill="#fff" stroke="#000" stroke-width=".2"/>
<circle cx="132.5" cy="80.4" r=".51" fill="#008000" stroke="#008000" stroke-width=".2"/>
<circle cx="132.5" cy="80.4" r=".3" fill="#fff" stroke="#000" stroke-width=".2"/>
<circle cx="149.8" cy="80.4" r=".51" fill="#008000" stroke="#008000" stroke-width=".2"/>
<circle cx="149.8" cy="80.4" r=".3" fill="#fff" stroke="#000" stroke-width=".2"/>
<circle cx="157.7" cy="103.7" r=".51" fill="#008000" stroke="#008000" stroke-width=".2"/>
<circle cx="157.7" cy="103.7" r=".3" fill="#fff" stroke="#000" stroke-width=".2"/>
<circle cx="157.8" cy="114.1" r=".44" fill="#008000" stroke="#008000" stroke-width=".2"/>
<circle cx="157.8" cy="114.1" r=".25" fill="#fff" stroke="#000" stroke-width=".2"/>
<circle cx="157.8" cy="108.6" r=".44" fill="#008000" stroke="#008000" stroke-width=".2"/>
<circle cx="157.8" cy="108.6" r=".25" fill="#fff" stroke="#000" stroke-width=".2"/>
<circle cx="131.6" cy="76.6" r=".51" fill="#008000" stroke="#008000" stroke-width=".2"/>
<circle cx="131.6" cy="76.6" r=".3" fill="#fff" stroke="#000" stroke-width=".2"/>
<circle cx="150.6" cy="76.5" r=".51" fill="#008000" stroke="#008000" stroke-width=".2"/>
<circle cx="150.6" cy="76.5" r=".3" fill="#fff" stroke="#000" stroke-width=".2"/>
<circle cx="163.4" cy="103.7" r=".51" fill="#008000" stroke="#008000" stroke-width=".2"/>
<circle cx="163.4" cy="103.7" r=".3" fill="#fff" stroke="#000" stroke-width=".2"/>
<circle cx="163.3" cy="109.2" r=".51" fill="#008000" stroke="#008000" stroke-width=".2"/>
<circle cx="163.3" cy="109.2" r=".3" fill="#fff" stroke="#000" stroke-width=".2"/>
<circle cx="132.5" cy="77.8" r=".51" fill="#008000" stroke="#008000" stroke-width=".2"/>
<circle cx="132.5" cy="77.8" r=".3" fill="#fff" stroke="#000" stroke-width=".2"/>
<circle cx="149.8" cy="78" r=".51" fill="#008000" stroke="#008000" stroke-width=".2"/>
<circle cx="149.8" cy="78" r=".3" fill="#fff" stroke="#000" stroke-width=".2"/>
<circle cx="161.5" cy="103.8" r=".51" fill="#008000" stroke="#008000" stroke-width=".2"/>
<circle cx="161.5" cy="103.8" r=".3" fill="#fff" stroke="#000" stroke-width=".2"/>
<circle cx="161.6" cy="109.2" r=".51" fill="#008000" stroke="#008000" stroke-width=".2"/>
<circle cx="161.6" cy="109.2" r=".3" fill="#fff" stroke="#000" stroke-width=".2"/>
<circle cx="132" cy="85.6" r=".51" fill="#008000" stroke="#008000" stroke-width=".2"/>
<circle cx="132" cy="85.6" r=".3" fill="#fff" stroke="#000" stroke-width=".2"/>
<circle cx="151.7" cy="85.4" r=".51" fill="#008000" stroke="#008000" stroke-width=".2"/>
<circle cx="151.7" cy="85.4" r=".3" fill="#fff" stroke="#000" stroke-width=".2"/>
<circle cx="152.7" cy="103.5" r=".51" fill="#008000" stroke="#008000" stroke-width=".2"/>
<circle cx="152.7" cy="103.5" r=".3" fill="#fff" stroke="#000" stroke-width=".2"/>
<circle cx="152.7" cy="111.8" r=".51" fill="#008000" stroke="#008000" stroke-width=".2"/>
<circle cx="152.7" cy="111.8" r=".3" fill="#fff" stroke="#000" stroke-width=".2"/>
<circle cx="134.2" cy="89.4" r=".51" fill="#008000" stroke="#008000" stroke-width=".2"/>
<circle cx="134.2" cy="89.4" r=".3" fill="#fff" stroke="#000" stroke-width=".2"/>
<circle cx="150.5" cy="90.5" r=".51" fill="#008000" stroke="#008000" stroke-width=".2"/>
<circle cx="150.5" cy="90.5" r=".3" fill="#fff" stroke="#000" stroke-width=".2"/>
<circle cx="150.4" cy="103.6" r=".51" fill="#008000" stroke="#008000" stroke-width=".2"/>
<circle cx="150.4" cy="103.6" r=".3" fill="#fff" stroke="#000" stroke-width=".2"/>
<circle cx="126" cy="96.8" r=".51" fill="#008000" stroke="#008000" stroke-width=".2"/>
<circle cx="126" cy="96.8" r=".3" fill="#fff" stroke="#000" stroke-width=".2"/>
<circle cx="132.3" cy="92" r=".51" fill="#008000" stroke="#008000" stroke-width=".2"/>
<circle cx="132.3" cy="92" r=".3" fill="#fff" stroke="#000" stroke-width=".2"/>
<circle cx="173.5" cy="89.8" r=".51" fill="#008000" stroke="#008000" stroke-width=".2"/>
<circle cx="173.5" cy="89.8" r=".3" fill="#fff" stroke="#000" stroke-width=".2"/>
<circle cx="189.7" cy="72.9" r=".51" fill="#008000" stroke="#008000" stroke-width=".2"/>
<circle cx="189.7" cy="72.9" r=".3" fill="#fff" stroke="#000" stroke-width=".2"/>
<circle cx="189.7" cy="81.1" r=".51" fill="#008000" stroke="#008000" stroke-width=".2"/>
<circle cx="189.7" cy="81.1" r=".3" fill="#fff" stroke="#000" stroke-width=".2"/>
<circle cx="173" cy="80.8" r=".51" fill="#008000" stroke="#008000" stroke-width=".2"/>
<circle cx="173" cy="80.8" r=".3" fill="#fff" stroke="#000" stroke-width=".2"/>
<circle cx="173.1" cy="83.2" r=".51" fill="#008000" stroke="#008000" stroke-width=".2"/>
<circle cx="173.1" cy="83.2" r=".3" fill="#fff" stroke="#000" stroke-width=".2"/>
<circle cx="173.9" cy="87.2" r=".51" fill="#008000" stroke="#008000" stroke-width=".2"/>
<circle cx="173.9" cy="87.2" r=".3" fill="#fff" stroke="#000" stroke-width=".2"/>
<circle cx="182.1" cy="78.5" r=".51" fill="#008000" stroke="#008000" stroke-width=".2"/>
<circle cx="182.1" cy="78.5" r=".3" fill="#fff" stroke="#000" stroke-width=".2"/>
<circle cx="192.1" cy="79.3" r=".51" fill="#008000" stroke="#008000" stroke-width=".2"/>
<circle cx="192.1" cy="79.3" r=".3" fill="#fff" stroke="#000" stroke-width=".2"/>
<circle cx="136" cy="70.5" r=".34" fill="#008000" stroke="#008000" stroke-width=".2"/>
<circle cx="136" cy="70.5" r=".13" fill="#fff" stroke="#000" stroke-width=".2"/>
<circle cx="127.9" cy="106.1" r=".51" fill="#008000" stroke="#008000" stroke-width=".2"/>
<circle cx="127.9" cy="106.1" r=".3" fill="#fff" stroke="#000" stroke-width=".2"/>
<circle cx="139.4" cy="70.1" r=".44" fill="#008000" stroke="#008000" stroke-width=".2"/>
<circle cx="139.4" cy="70.1" r=".25" fill="#fff" stroke="#000" stroke-width=".2"/>
<circle cx="128" cy="101.8" r=".51" fill="#008000" stroke="#008000" stroke-width=".2"/>
<circle cx="128" cy="101.8" r=".3" fill="#fff" stroke="#000" stroke-width=".2"/>
<circle cx="132.2" cy="99.3" r=".51" fill="#008000" stroke="#008000" stroke-width=".2"/>
<circle cx="132.2" cy="99.3" r=".3" fill="#fff" stroke="#000" stroke-width=".2"/>
<circle cx="139.3" cy="99.2" r=".51" fill="#008000" stroke="#008000" stroke-width=".2"/>
<circle cx="139.3" cy="99.2" r=".3" fill="#fff" stroke="#000" stroke-width=".2"/>
<circle cx="139.3" cy="106.5" r=".51" fill="#008000" stroke="#008000" stroke-width=".2"/>
<circle cx="139.3" cy="106.5" r=".3" fill="#fff" stroke="#000" stroke-width=".2"/>
<circle cx="119.1" cy="102.9" r=".51" fill="#008000" stroke="#008000" stroke-width=".2"/>
<circle cx="119.1" cy="102.9" r=".3" fill="#fff" stroke="#000" stroke-width=".2"/>
<circle cx="132.1" cy="97.2" r=".51" fill="#008000" stroke="#008000" stroke-width=".2"/>
<circle cx="132.1" cy="97.2" r=".3" fill="#fff" stroke="#000" stroke-width=".2"/>
<circle cx="136.9" cy="97.4" r=".51" fill="#008000" stroke="#008000" stroke-width=".2"/>
<circle cx="136.9" cy="97.4" r=".3" fill="#fff" stroke="#000" stroke-width=".2"/>
<circle cx="136.9" cy="102.9" r=".51" fill="#008000" stroke="#008000" stroke-width=".2"/>
<circle cx="136.9" cy="102.9" r=".3" fill="#fff" stroke="#000" stroke-width=".2"/>
<circle cx="114.9" cy="102.8" r=".51" fill="#008000" stroke="#008000" stroke-width=".2"/>
<circle cx="114.9" cy="102.8" r=".3" fill="#fff" stroke="#000" stroke-width=".2"/>
<circle cx="131.5" cy="103.9" r=".51" fill="#008000" stroke="#008000" stroke-width=".2"/>
<circle cx="131.5" cy="103.9" r=".3" fill="#fff" stroke="#000" stroke-width=".2"/>
<circle cx="132.1" cy="84.3" r=".51" fill="#008000" stroke="#008000" stroke-width=".2"/>
<circle cx="132.1" cy="84.3" r=".3" fill="#fff" stroke="#000" stroke-width=".2"/>
<circle cx="166.1" cy="84.3" r=".51" fill="#008000" stroke="#008000" stroke-width=".2"/>
<circle cx="166.1" cy="84.3" r=".3" fill="#fff" stroke="#000" stroke-width=".2"/>
<circle cx="169.7" cy="84.3" r=".51" fill="#008000" stroke="#008000" stroke-width=".2"/>
<circle cx="169.7" cy="84.3" r=".3" fill="#fff" stroke="#000" stroke-width=".2"/>
<circle cx="131.8" cy="81.7" r=".51" fill="#008000" stroke="#008000" stroke-width=".2"/>
<circle cx="131.8" cy="81.7" r=".3" fill="#fff" stroke="#000" stroke-width=".2"/>
<circle cx="166.3" cy="81.6" r=".51" fill="#008000" stroke="#008000" stroke-width=".2"/>
<circle cx="166.3" cy="81.6" r=".3" fill="#fff" stroke="#000" stroke-width=".2"/>
<circle cx="179.4" cy="81.7" r=".51" fill="#008000" stroke="#008000" stroke-width=".2"/>
<circle cx="179.4" cy="81.7" r=".3" fill="#fff" stroke="#000" stroke-width=".2"/>
<circle cx="186.3" cy="82.5" r=".51" fill="#008000" stroke="#008000" stroke-width=".2"/>
<circle cx="186.3" cy="82.5" r=".3" fill="#fff" stroke="#000" stroke-width=".2"/>
<circle cx="183.8" cy="101" r=".51" fill="#008000" stroke="#008000" stroke-width=".2"/>
<circle cx="183.8" cy="101" r=".3" fill="#fff" stroke="#000" stroke-width=".2"/>
<circle cx="179.8" cy="96.4" r=".51" fill="#008000" stroke="#008000" stroke-width=".2"/>
<circle cx="179.8" cy="96.4" r=".3" fill="#fff" stroke="#000" stroke-width=".2"/>
<circle cx="179.1" cy="92.9" r=".51" fill="#008000" stroke="#008000" stroke-width=".2"/>
<circle cx="179.1" cy="92.9" r=".3" fill="#fff" stroke="#000" stroke-width=".2"/>
<circle cx="178.7" cy="88" r=".51" fill="#008000" stroke="#008000" stroke-width=".2"/>
<circle cx="178.7" cy="88" r=".3" fill="#fff" stroke="#000" stroke-width=".2"/>
<circle cx="175.6" cy="85.8" r=".51" fill="#008000" stroke="#008000" stroke-width=".2"/>
<circle cx="175.6" cy="85.8" r=".3" fill="#fff" stroke="#000" stroke-width=".2"/>
<circle cx="175.7" cy="83" r=".51" fill="#008000" stroke="#008000" stroke-width=".2"/>
<circle cx="175.7" cy="83" r=".3" fill="#fff" stroke="#000" stroke-width=".2"/>
<circle cx="175.6" cy="80.8" r=".51" fill="#008000" stroke="#008000" stroke-width=".2"/>
<circle cx="175.6" cy="80.8" r=".3" fill="#fff" stroke="#000" stroke-width=".2"/>
<circle cx="167" cy="76.2" r=".51" fill="#008000" stroke="#008000" stroke-width=".2"/>
<circle cx="167" cy="76.2" r=".3" fill="#fff" stroke="#000" stroke-width=".2"/>
<circle cx="161.9" cy="73.2" r=".51" fill="#008000" stroke="#008000" stroke-width=".2"/>
<circle cx="161.9" cy="73.2" r=".3" fill="#fff" stroke="#000" stroke-width=".2"/>
<circle cx="132.9" cy="83" r=".59" fill="#008000" stroke="#008000" stroke-width=".2"/>
<circle cx="132.9" cy="83" r=".4" fill="#fff" stroke="#000" stroke-width=".2"/>
<circle cx="153.1" cy="83" r=".59" fill="#008000" stroke="#008000" stroke-width=".2"/>
<circle cx="153.1" cy="83" r=".4" fill="#fff" stroke="#000" stroke-width=".2"/>
<circle cx="156.2" cy="98.9" r=".59" fill="#008000" stroke="#008000" stroke-width=".2"/>
<circle cx="156.2" cy="98.9" r=".4" fill="#fff" stroke="#000" stroke-width=".2"/>
<circle cx="175.5" cy="99" r=".59" fill="#008000" stroke="#008000" stroke-width=".2"/>
<circle cx="175.5" cy="99" r=".4" fill="#fff" stroke="#000" stroke-width=".2"/>
<circle cx="178.8" cy="99.3" r=".59" fill="#008000" stroke="#008000" stroke-width=".2"/>
<circle cx="178.8" cy="99.3" r=".4" fill="#fff" stroke="#000" stroke-width=".2"/>
<circle cx="119.1" cy="73.3" r=".59" fill="#008000" stroke="#008000" stroke-width=".2"/>
<circle cx="119.1" cy="73.3" r=".4" fill="#fff" stroke="#000" stroke-width=".2"/>
<circle cx="128.5" cy="94" r=".51" fill="#008000" stroke="#008000" stroke-width=".2"/>
<circle cx="128.5" cy="94" r=".3" fill="#fff" stroke="#000" stroke-width=".2"/>
<circle cx="132.3" cy="94" r=".51" fill="#008000" stroke="#008000" stroke-width=".2"/>
<circle cx="132.3" cy="94" r=".3" fill="#fff" stroke="#000" stroke-width=".2"/>
<circle cx="143" cy="94.1" r=".51" fill="#008000" stroke="#008000" stroke-width=".2"/>
<circle cx="143" cy="94.1" r=".3" fill="#fff" stroke="#000" stroke-width=".2"/>
<circle cx="128.5" cy="95.5" r=".51" fill="#008000" stroke="#008000" stroke-width=".2"/>
<circle cx="128.5" cy="95.5" r=".3" fill="#fff" stroke="#000" stroke-width=".2"/>
<circle cx="132.2" cy="95.5" r=".51" fill="#008000" stroke="#008000" stroke-width=".2"/>
<circle cx="132.2" cy="95.5" r=".3" fill="#fff" stroke="#000" stroke-width=".2"/>
<circle cx="148.2" cy="94.9" r=".51" fill="#008000" stroke="#008000" stroke-width=".2"/>
<circle cx="148.2" cy="94.9" r=".3" fill="#fff" stroke="#000" stroke-width=".2"/>
<circle cx="131.9" cy="79.1" r=".51" fill="#008000" stroke="#008000" stroke-width=".2"/>
<circle cx="131.9" cy="79.1" r=".3" fill="#fff" stroke="#000" stroke-width=".2"/>
<circle cx="150.9" cy="79.2" r=".51" fill="#008000" stroke="#008000" stroke-width=".2"/>
<circle cx="150.9" cy="79.2" r=".3" fill="#fff" stroke="#000" stroke-width=".2"/>
<circle cx="159.8" cy="103.7" r=".51" fill="#008000" stroke="#008000" stroke-width=".2"/>
<circle cx="159.8" cy="103.7" r=".3" fill="#fff" stroke="#000" stroke-width=".2"/>
<circle cx="156.1" cy="110.7" r=".44" fill="#008000" stroke="#008000" stroke-width=".2"/>
<circle cx="156.1" cy="110.7" r=".25" fill="#fff" stroke="#000" stroke-width=".2"/>
<circle cx="112.4" cy="60.1" r="2.16" fill="#008000" stroke="#008000" stroke-width=".2"/>
<circle cx="112.4" cy="60.1" r="1.65" fill="#fff" stroke="#000" stroke-width=".2"/>
<circle cx="186" cy="60.1" r="2.16" fill="#008000" stroke="#008000" stroke-width=".2"/>
<circle cx="186" cy="60.1" r="1.65" fill="#fff" stroke="#000" stroke-width=".2"/>
<circle cx="188.6" cy="145.8" r="2.16" fill="#008000" stroke="#008000" stroke-width=".2"/>
<circle cx="188.6" cy="145.8" r="1.65" fill="#fff" stroke="#000" stroke-width=".2"/>
<circle cx="108.6" cy="145.8" r="2.16" fill="#008000" stroke="#008000" stroke-width=".2"/>
<circle cx="108.6" cy="145.8" r="1.65" fill="#fff" stroke="#000" stroke-width=".2"/>
<circle cx="168.1" cy="97.2" r=".51" fill="#008000" stroke="#008000" stroke-width=".2"/>
<circle cx="168.1" cy="97.2" r=".3" fill="#fff" stroke="#000" stroke-width=".2"/>
<circle cx="146.9" cy="97.2" r=".51" fill="#008000" stroke="#008000" stroke-width=".2"/>
<circle cx="146.9" cy="97.2" r=".3" fill="#fff" stroke="#000" stroke-width=".2"/>
<circle cx="165" cy="73" r=".51" fill="#008000" stroke="#008000" stroke-width=".2"/>
<circle cx="165" cy="73" r=".3" fill="#fff" stroke="#000" stroke-width=".2"/>
<circle cx="167" cy="73" r=".51" fill="#008000" stroke="#008000" stroke-width=".2"/>
<circle cx="167" cy="73" r=".3" fill="#fff" stroke="#000" stroke-width=".2"/>
<circle cx="171.4" cy="73" r=".51" fill="#008000" stroke="#008000" stroke-width=".2"/>
<circle cx="171.4" cy="73" r=".3" fill="#fff" stroke="#000" stroke-width=".2"/>
<circle cx="185" cy="76.9" r=".51" fill="#008000" stroke="#008000" stroke-width=".2"/>
<circle cx="185" cy="76.9" r=".3" fill="#fff" stroke="#000" stroke-width=".2"/>
<circle cx="187.4" cy="89.9" r=".51" fill="#008000" stroke="#008000" stroke-width=".2"/>
<circle cx="187.4" cy="89.9" r=".3" fill="#fff" stroke="#000" stroke-width=".2"/>
<circle cx="164.9" cy="71.2" r=".51" fill="#008000" stroke="#008000" stroke-width=".2"/>
<circle cx="164.9" cy="71.2" r=".3" fill="#fff" stroke="#000" stroke-width=".2"/>
<circle cx="167" cy="71.2" r=".51" fill="#008000" stroke="#008000" stroke-width=".2"/>
<circle cx="167" cy="71.2" r=".3" fill="#fff" stroke="#000" stroke-width=".2"/>
<circle cx="174.8" cy="71.3" r=".51" fill="#008000" stroke="#008000" stroke-width=".2"/>
<circle cx="174.8" cy="71.3" r=".3" fill="#fff" stroke="#000" stroke-width=".2"/>
<circle cx="187.7" cy="75.3" r=".44" fill="#008000" stroke="#008000" stroke-width=".2"/>
<circle cx="187.7" cy="75.3" r=".25" fill="#fff" stroke="#000" stroke-width=".2"/>
<circle cx="189.6" cy="90" r=".44" fill="#008000" stroke="#008000" stroke-width=".2"/>
<circle cx="189.6" cy="90" r=".25" fill="#fff" stroke="#000" stroke-width=".2"/>
<g fill="#000080" stroke="#000080" stroke-width=".2">
<path d="M103.4 148.8h.3v.4h-.3z"/>
<path d="M103.4 74.7l.4-.2 .3 .2-.5 .4-.2-.1z"/>
<path d="M103.3 72.4h.4l-.2 .5-.2-.1z"/>
<path d="M103.4 67.6h.3v.4l-.3 .1z"/>
<path d="M103.7 56.9h.2l.1 .2-.2 .3-.2 .1-.1-.3z"/>
<circle cx="103.8" cy="57.1" r=".25"/>
<circle cx="104.7" cy="57.1" r=".25"/>
<circle cx="105.7" cy="57.1" r=".24"/>
<circle cx="106.6" cy="57.1" r=".25"/>
<circle cx="107.5" cy="57.1" r=".25"/>
<circle cx="108.4" cy="57.1" r=".24"/>
<circle cx="109.3" cy="57.1" r=".25"/>
<circle cx="110.2" cy="57.1" r=".25"/>
<circle cx="111.2" cy="57.1" r=".24"/>
<circle cx="112.1" cy="57.1" r=".25"/>
<circle cx="113" cy="57.1" r=".25"/>
<circle cx="113.9" cy="57.1" r=".25"/>
<circle cx="114.8" cy="57.1" r=".25"/>
<circle cx="115.7" cy="57.1" r=".25"/>
<circle cx="116.6" cy="57.1" r=".25"/>
<circle cx="117.6" cy="57.1" r=".25"/>
<circle cx="118.5" cy="57.1" r=".25"/>
<circle cx="119.4" cy="57.1" r=".25"/>
<circle cx="120.3" cy="57.1" r=".25"/>
<circle cx="121.2" cy="57.1" r=".25"/>
<circle cx="122.2" cy="57.1" r=".25"/>
<circle cx="123.1" cy="57.1" r=".25"/>
<circle cx="124" cy="57.1" r=".25"/>
<circle cx="124.9" cy="57.1" r=".25"/>
<circle cx="125.8" cy="57.1" r=".25"/>
<circle cx="126.7" cy="57.1" r=".25"/>
<circle cx="127.7" cy="57.1" r=".25"/>
<circle cx="128.6" cy="57.1" r=".25"/>
<circle cx="129.5" cy="57.1" r=".25"/>
<circle cx="130.4" cy="57.1" r=".25"/>
<circle cx="131.3" cy="57.1" r=".25"/>
<circle cx="132.2" cy="57.1" r=".25"/>
<circle cx="133.2" cy="57.1" r=".25"/>
<circle cx="134.1" cy="57.1" r=".25"/>
<circle cx="135" cy="57.1" r=".25"/>
<circle cx="135.9" cy="57.1" r=".25"/>
<circle cx="136.8" cy="57.1" r=".25"/>
<circle cx="137.8" cy="57.1" r=".25"/>
<circle cx="138.7" cy="57.1" r=".25"/>
<circle cx="139.6" cy="57.1" r=".24"/>
<circle cx="140.5" cy="57.1" r=".25"/>
<circle cx="141.4" cy="57.1" r=".25"/>
<circle cx="142.3" cy="57.1" r=".24"/>
<circle cx="143.3" cy="57.1" r=".25"/>
<circle cx="144.2" cy="57.1" r=".25"/>
<circle cx="145.1" cy="57.1" r=".25"/>
<circle cx="146" cy="57.1" r=".25"/>
<circle cx="146.9" cy="57.1" r=".25"/>
<circle cx="147.8" cy="57.1" r=".25"/>
<circle cx="148.8" cy="57.1" r=".25"/>
<circle cx="149.7" cy="57.1" r=".25"/>
<circle cx="150.6" cy="57.1" r=".25"/>
<circle cx="151.5" cy="57.1" r=".25"/>
<circle cx="152.4" cy="57.1" r=".25"/>
<circle cx="153.3" cy="57.1" r=".25"/>
<circle cx="154.3" cy="57.1" r=".25"/>
<circle cx="155.2" cy="57.1" r=".25"/>
<circle cx="156.1" cy="57.1" r=".25"/>
<circle cx="157" cy="57.1" r=".25"/>
<circle cx="157.9" cy="57.1" r=".25"/>
<circle cx="158.8" cy="57.1" r=".25"/>
<circle cx="159.8" cy="57.1" r=".25"/>
<circle cx="160.7" cy="57.1" r=".25"/>
<circle cx="161.6" cy="57.1" r=".25"/>
<circle cx="162.5" cy="57.1" r=".25"/>
<circle cx="163.4" cy="57.1" r=".25"/>
<circle cx="164.3" cy="57.1" r=".25"/>
<circle cx="165.3" cy="57.1" r=".25"/>
<circle cx="166.2" cy="57.1" r=".25"/>
<circle cx="167.1" cy="57.1" r=".25"/>
<circle cx="168" cy="57.1" r=".25"/>
<circle cx="168.9" cy="57.1" r=".25"/>
<circle cx="169.8" cy="57.1" r=".25"/>
<circle cx="170.8" cy="57.1" r=".24"/>
<circle cx="171.7" cy="57.1" r=".25"/>
<circle cx="172.6" cy="57.1" r=".25"/>
<circle cx="173.5" cy="57.1" r=".24"/>
<circle cx="174.4" cy="57.1" r=".25"/>
<circle cx="175.3" cy="57.1" r=".25"/>
<circle cx="176.3" cy="57.1" r=".24"/>
<circle cx="177.2" cy="57.1" r=".25"/>
<circle cx="178.1" cy="57.1" r=".25"/>
<circle cx="179" cy="57.1" r=".25"/>
<circle cx="179.9" cy="57.1" r=".25"/>
<circle cx="180.8" cy="57.1" r=".25"/>
<circle cx="181.8" cy="57.1" r=".25"/>
<circle cx="182.7" cy="57.1" r=".25"/>
<circle cx="183.6" cy="57.1" r=".25"/>
<circle cx="184.5" cy="57.1" r=".25"/>
<circle cx="185.4" cy="57.1" r=".25"/>
<circle cx="186.4" cy="57.1" r=".25"/>
<circle cx="187.3" cy="57.1" r=".25"/>
<circle cx="188.2" cy="57.1" r=".25"/>
<circle cx="189.1" cy="57.1" r=".25"/>
<circle cx="190" cy="57.1" r=".25"/>
<circle cx="190.9" cy="57.1" r=".25"/>
<circle cx="191.9" cy="57.1" r=".25"/>
<circle cx="192.8" cy="57.1" r=".25"/>
<circle cx="193.7" cy="57.1" r=".25"/>
<circle cx="193.7" cy="57.2" r=".25"/>
<circle cx="193.7" cy="58.1" r=".25"/>
<circle cx="193.7" cy="59" r=".25"/>
<circle cx="193.7" cy="59.9" r=".25"/>
<circle cx="193.7" cy="60.8" r=".25"/>
<circle cx="193.7" cy="61.8" r=".24"/>
<circle cx="193.7" cy="62.7" r=".25"/>
<circle cx="193.7" cy="63.6" r=".25"/>
<circle cx="193.7" cy="64.5" r=".25"/>
<circle cx="193.7" cy="65.4" r=".25"/>
<circle cx="193.7" cy="66.3" r=".25"/>
<circle cx="193.7" cy="67.2" r=".25"/>
<circle cx="193.7" cy="68.2" r=".24"/>
<circle cx="193.7" cy="69.1" r=".25"/>
<circle cx="193.7" cy="70" r=".25"/>
<circle cx="193.7" cy="70.9" r=".25"/>
<circle cx="193.7" cy="71.8" r=".25"/>
<circle cx="193.7" cy="72.7" r=".25"/>
<circle cx="193.7" cy="73.7" r=".25"/>
<circle cx="193.7" cy="74.6" r=".24"/>
<circle cx="193.7" cy="75.5" r=".25"/>
<circle cx="193.7" cy="76.4" r=".25"/>
<circle cx="193.7" cy="77.3" r=".25"/>
<circle cx="193.7" cy="78.3" r=".25"/>
<circle cx="193.7" cy="79.2" r=".25"/>
<circle cx="193.7" cy="80.1" r=".25"/>
<circle cx="193.7" cy="81" r=".24"/>
<circle cx="193.7" cy="81.9" r=".25"/>
<circle cx="193.7" cy="82.8" r=".25"/>
<circle cx="193.7" cy="83.7" r=".25"/>
<circle cx="193.7" cy="84.7" r=".25"/>
<circle cx="193.7" cy="85.6" r=".25"/>
<circle cx="193.7" cy="86.5" r=".25"/>
<circle cx="193.7" cy="87.4" r=".24"/>
<circle cx="193.7" cy="88.3" r=".25"/>
<circle cx="193.7" cy="89.2" r=".25"/>
<circle cx="193.7" cy="90.1" r=".25"/>
<circle cx="193.7" cy="91.1" r=".25"/>
<circle cx="193.7" cy="92" r=".25"/>
<circle cx="193.7" cy="92.9" r=".25"/>
<circle cx="193.7" cy="93.8" r=".24"/>
<circle cx="193.7" cy="94.7" r=".25"/>
<circle cx="193.7" cy="95.7" r=".25"/>
<circle cx="193.7" cy="96.6" r=".25"/>
<circle cx="193.7" cy="97.5" r=".25"/>
<circle cx="193.7" cy="98.4" r=".25"/>
<circle cx="193.7" cy="99.3" r=".25"/>
<circle cx="193.7" cy="100.2" r=".24"/>
<circle cx="193.7" cy="101.2" r=".25"/>
<circle cx="193.7" cy="102.1" r=".25"/>
<circle cx="193.7" cy="103" r=".25"/>
<circle cx="193.7" cy="103.9" r=".25"/>
<circle cx="193.7" cy="104.8" r=".25"/>
<circle cx="193.7" cy="105.7" r=".25"/>
<circle cx="193.7" cy="106.6" r=".25"/>
<circle cx="193.7" cy="107.6" r=".25"/>
<circle cx="193.7" cy="108.5" r=".25"/>
<circle cx="193.7" cy="109.4" r=".25"/>
<circle cx="193.7" cy="110.3" r=".25"/>
<circle cx="193.7" cy="111.2" r=".25"/>
<circle cx="193.7" cy="112.1" r=".25"/>
<circle cx="193.7" cy="113.1" r=".25"/>
<circle cx="193.7" cy="114" r=".25"/>
<circle cx="193.7" cy="114.9" r=".25"/>
<circle cx="193.7" cy="115.8" r=".25"/>
<circle cx="193.7" cy="116.7" r=".25"/>
<circle cx="193.7" cy="117.6" r=".25"/>
<circle cx="193.7" cy="118.6" r=".25"/>
<circle cx="193.7" cy="119.5" r=".25"/>
<circle cx="193.7" cy="120.4" r=".25"/>
<circle cx="193.7" cy="121.3" r=".25"/>
<circle cx="193.7" cy="122.2" r=".25"/>
<circle cx="193.7" cy="123.1" r=".24"/>
<circle cx="193.7" cy="124.1" r=".25"/>
<circle cx="193.7" cy="125" r=".25"/>
<circle cx="193.7" cy="125.9" r=".25"/>
<circle cx="193.7" cy="126.8" r=".25"/>
<circle cx="193.7" cy="127.7" r=".25"/>
<circle cx="193.7" cy="128.6" r=".25"/>
<circle cx="193.8" cy="129.6" r=".24"/>
<circle cx="193.8" cy="130.5" r=".25"/>
<circle cx="193.8" cy="131.4" r=".25"/>
<circle cx="193.8" cy="132.3" r=".25"/>
<circle cx="193.8" cy="133.2" r=".25"/>
<circle cx="193.8" cy="134.1" r=".25"/>
<circle cx="193.8" cy="135" r=".25"/>
<circle cx="193.8" cy="136" r=".24"/>
<circle cx="193.8" cy="136.9" r=".25"/>
<circle cx="193.8" cy="137.8" r=".25"/>
<circle cx="193.8" cy="138.7" r=".25"/>
<circle cx="193.8" cy="139.6" r=".25"/>
<circle cx="193.8" cy="140.5" r=".25"/>
<circle cx="193.8" cy="141.5" r=".25"/>
<circle cx="193.8" cy="142.4" r=".24"/>
<circle cx="193.8" cy="143.3" r=".25"/>
<circle cx="193.8" cy="144.2" r=".25"/>
<circle cx="193.8" cy="145.1" r=".25"/>
<circle cx="193.8" cy="146" r=".25"/>
<circle cx="193.8" cy="147" r=".25"/>
<circle cx="193.8" cy="147.9" r=".25"/>
<circle cx="193.8" cy="148.8" r=".24"/>
<circle cx="193.7" cy="148.8" r=".25"/>
<circle cx="192.8" cy="148.8" r=".26"/>
<circle cx="191.9" cy="148.8" r=".25"/>
<circle cx="191" cy="148.8" r=".25"/>
<circle cx="190.1" cy="148.8" r=".25"/>
<circle cx="189.1" cy="148.8" r=".25"/>
<circle cx="188.2" cy="148.8" r=".25"/>
<circle cx="187.3" cy="148.8" r=".25"/>
<circle cx="186.4" cy="148.8" r=".25"/>
<circle cx="185.5" cy="148.8" r=".25"/>
<circle cx="184.5" cy="148.8" r=".25"/>
<circle cx="183.6" cy="148.8" r=".25"/>
<circle cx="182.7" cy="148.8" r=".25"/>
<circle cx="181.8" cy="148.8" r=".25"/>
<circle cx="180.9" cy="148.8" r=".26"/>
<circle cx="179.9" cy="148.8" r=".25"/>
<circle cx="179" cy="148.8" r=".25"/>
<circle cx="178.1" cy="148.8" r=".25"/>
<circle cx="177.2" cy="148.8" r=".25"/>
<circle cx="176.3" cy="148.9" r=".25"/>
<circle cx="175.3" cy="148.9" r=".25"/>
<circle cx="174.4" cy="148.9" r=".25"/>
<circle cx="173.5" cy="148.9" r=".25"/>
<circle cx="172.6" cy="148.9" r=".25"/>
<circle cx="171.7" cy="148.9" r=".25"/>
<circle cx="170.7" cy="148.9" r=".25"/>
<circle cx="169.8" cy="148.9" r=".25"/>
<circle cx="168.9" cy="148.9" r=".25"/>
<circle cx="168" cy="148.9" r=".23"/>
<circle cx="167.1" cy="148.9" r=".26"/>
<circle cx="166.1" cy="148.9" r=".25"/>
<circle cx="165.2" cy="148.9" r=".25"/>
<circle cx="164.3" cy="148.9" r=".25"/>
<circle cx="163.4" cy="148.9" r=".25"/>
<circle cx="162.5" cy="148.9" r=".25"/>
<circle cx="161.5" cy="148.9" r=".25"/>
<circle cx="160.6" cy="148.9" r=".25"/>
<circle cx="159.7" cy="148.9" r=".25"/>
<circle cx="158.8" cy="148.9" r=".25"/>
<circle cx="157.9" cy="148.9" r=".25"/>
<circle cx="156.9" cy="148.9" r=".25"/>
<circle cx="156" cy="148.9" r=".25"/>
<circle cx="155.1" cy="148.9" r=".26"/>
<circle cx="154.2" cy="148.9" r=".25"/>
<circle cx="153.3" cy="148.9" r=".25"/>
<circle cx="152.3" cy="148.9" r=".25"/>
<circle cx="151.4" cy="148.9" r=".25"/>
<circle cx="150.5" cy="148.9" r=".25"/>
<circle cx="149.6" cy="148.9" r=".25"/>
<circle cx="148.7" cy="148.9" r=".25"/>
<circle cx="147.7" cy="148.9" r=".25"/>
<circle cx="146.8" cy="148.9" r=".25"/>
<circle cx="145.9" cy="148.9" r=".25"/>
<circle cx="145" cy="148.9" r=".25"/>
<circle cx="144.1" cy="148.9" r=".25"/>
<circle cx="143.1" cy="148.9" r=".25"/>
<circle cx="142.2" cy="148.9" r=".25"/>
<circle cx="141.3" cy="148.9" r=".26"/>
<circle cx="140.4" cy="148.9" r=".25"/>
<circle cx="139.5" cy="148.9" r=".25"/>
<circle cx="138.5" cy="148.9" r=".25"/>
<circle cx="137.6" cy="148.9" r=".25"/>
<circle cx="136.7" cy="148.9" r=".25"/>
<circle cx="135.8" cy="148.9" r=".25"/>
<circle cx="134.9" cy="148.9" r=".25"/>
<circle cx="133.9" cy="149" r=".25"/>
<circle cx="133" cy="149" r=".25"/>
<circle cx="132.1" cy="149" r=".25"/>
<circle cx="131.2" cy="149" r=".25"/>
<circle cx="130.3" cy="149" r=".25"/>
<circle cx="129.3" cy="149" r=".26"/>
<circle cx="128.4" cy="149" r=".25"/>
<circle cx="127.5" cy="149" r=".25"/>
<circle cx="126.6" cy="149" r=".25"/>
<circle cx="125.7" cy="149" r=".25"/>
<circle cx="124.7" cy="149" r=".25"/>
<circle cx="123.8" cy="149" r=".25"/>
<circle cx="122.9" cy="149" r=".25"/>
<circle cx="122" cy="149" r=".25"/>
<circle cx="121.1" cy="149" r=".25"/>
<circle cx="120.1" cy="149" r=".25"/>
<circle cx="119.2" cy="149" r=".25"/>
<circle cx="118.3" cy="149" r=".25"/>
<circle cx="117.4" cy="149" r=".25"/>
<circle cx="116.5" cy="149" r=".25"/>
<circle cx="115.5" cy="149" r=".26"/>
<circle cx="114.6" cy="149" r=".25"/>
<circle cx="113.7" cy="149" r=".25"/>
<circle cx="112.8" cy="149" r=".25"/>
<circle cx="111.9" cy="149" r=".25"/>
<circle cx="110.9" cy="149" r=".25"/>
<circle cx="110" cy="149" r=".25"/>
<circle cx="109.1" cy="149" r=".23"/>
<circle cx="108.2" cy="149" r=".25"/>
<circle cx="107.3" cy="149" r=".25"/>
<circle cx="106.3" cy="149" r=".25"/>
<circle cx="105.4" cy="149" r=".25"/>
<circle cx="104.5" cy="149" r=".25"/>
<circle cx="103.6" cy="149" r=".26"/>
<circle cx="103.6" cy="148.1" r=".26"/>
<circle cx="103.6" cy="147.1" r=".26"/>
<circle cx="103.6" cy="146.2" r=".26"/>
<circle cx="103.6" cy="145.3" r=".26"/>
<circle cx="103.6" cy="144.3" r=".26"/>
<circle cx="103.6" cy="143.4" r=".26"/>
<circle cx="103.6" cy="142.4" r=".26"/>
<circle cx="103.6" cy="141.5" r=".26"/>
<circle cx="103.6" cy="140.6" r=".26"/>
<circle cx="103.6" cy="139.6" r=".26"/>
<circle cx="103.7" cy="138.7" r=".26"/>
<circle cx="103.7" cy="137.7" r=".26"/>
<circle cx="103.7" cy="136.8" r=".26"/>
<circle cx="103.7" cy="135.9" r=".26"/>
<circle cx="103.7" cy="134.9" r=".26"/>
<circle cx="103.7" cy="134" r=".26"/>
<circle cx="103.7" cy="133" r=".26"/>
<circle cx="103.7" cy="132.1" r=".26"/>
<circle cx="103.7" cy="131.2" r=".26"/>
<circle cx="103.7" cy="130.2" r=".26"/>
<circle cx="103.7" cy="129.3" r=".26"/>
<circle cx="103.7" cy="128.4" r=".26"/>
<circle cx="103.8" cy="127.4" r=".26"/>
<circle cx="103.8" cy="126.5" r=".26"/>
<circle cx="108.3" cy="121.3" r=".25"/>
<circle cx="108.3" cy="120.4" r=".25"/>
<circle cx="108.3" cy="119.5" r=".25"/>
<circle cx="108.3" cy="118.6" r=".25"/>
<circle cx="108.3" cy="117.7" r=".24"/>
<circle cx="108.3" cy="116.8" r=".25"/>
<circle cx="108.3" cy="115.8" r=".25"/>
<circle cx="108.3" cy="114.9" r=".25"/>
<circle cx="108.3" cy="114" r=".25"/>
<circle cx="108.3" cy="113.1" r=".25"/>
<circle cx="108.3" cy="112.2" r=".25"/>
<circle cx="108.3" cy="111.3" r=".25"/>
<circle cx="108.3" cy="110.3" r=".25"/>
<circle cx="108.3" cy="109.4" r=".25"/>
<circle cx="108.3" cy="108.5" r=".25"/>
<circle cx="108.3" cy="107.6" r=".24"/>
<circle cx="108.3" cy="106.7" r=".25"/>
<circle cx="108.3" cy="105.8" r=".25"/>
<circle cx="108.3" cy="104.9" r=".25"/>
<circle cx="108.3" cy="103.9" r=".25"/>
<circle cx="108.3" cy="103" r=".25"/>
<circle cx="108.3" cy="102.1" r=".25"/>
<circle cx="108.3" cy="101.2" r=".25"/>
<circle cx="108.3" cy="100.3" r=".25"/>
<circle cx="108.3" cy="99.4" r=".25"/>
<circle cx="108.3" cy="98.4" r=".25"/>
<circle cx="108.3" cy="97.5" r=".24"/>
<circle cx="108.3" cy="96.6" r=".25"/>
<circle cx="108.3" cy="95.7" r=".25"/>
<circle cx="108.3" cy="94.8" r=".25"/>
<circle cx="108.3" cy="93.9" r=".25"/>
<circle cx="108.3" cy="92.9" r=".25"/>
<circle cx="108.3" cy="92" r=".25"/>
<circle cx="108.3" cy="91.1" r=".25"/>
<circle cx="108.3" cy="90.2" r=".25"/>
<circle cx="108.3" cy="89.3" r=".25"/>
<circle cx="108.3" cy="88.4" r=".25"/>
<circle cx="108.3" cy="87.5" r=".24"/>
<circle cx="108.3" cy="86.5" r=".25"/>
<circle cx="108.3" cy="85.6" r=".25"/>
<circle cx="108.3" cy="84.7" r=".25"/>
<circle cx="108.3" cy="83.8" r=".24"/>
<circle cx="108.3" cy="82.9" r=".25"/>
<circle cx="108.3" cy="82" r=".25"/>
<circle cx="108.3" cy="81" r=".25"/>
<circle cx="108.3" cy="80.1" r=".25"/>
<circle cx="108.3" cy="79.2" r=".25"/>
<circle cx="103.5" cy="74.5" r=".26"/>
<circle cx="103.5" cy="73.6" r=".26"/>
<circle cx="103.5" cy="71.6" r=".26"/>
<circle cx="103.5" cy="70.7" r=".26"/>
<circle cx="103.5" cy="69.7" r=".26"/>
<circle cx="103.6" cy="68.8" r=".26"/>
<circle cx="103.6" cy="66.9" r=".26"/>
<circle cx="103.6" cy="65.9" r=".26"/>
<circle cx="103.6" cy="65" r=".26"/>
<circle cx="103.6" cy="64" r=".26"/>
<circle cx="103.6" cy="63.1" r=".26"/>
<circle cx="103.6" cy="62.1" r=".26"/>
<circle cx="103.7" cy="61.2" r=".26"/>
<circle cx="103.7" cy="60.2" r=".26"/>
<circle cx="103.7" cy="59.2" r=".26"/>
<circle cx="103.7" cy="58.3" r=".26"/>
<circle cx="103.7" cy="57.3" r=".26"/>
</g>
<g fill="#000080" stroke="#000080" stroke-width=".2">
<path d="M103.2 74.5l.2-.1 .3 .1a.23 .23 0 0 1 .3 .1 .23 .23 0 0 1-.2 .3l-.5-.1z" fill-rule="evenodd"/>
<circle cx="103.8" cy="126.4" r=".24"/>
<circle cx="104.7" cy="126.2" r=".23"/>
<circle cx="105.6" cy="125.9" r=".23"/>
<circle cx="106.4" cy="125.4" r=".24"/>
<circle cx="107" cy="124.8" r=".23"/>
<circle cx="107.6" cy="124.1" r=".24"/>
<circle cx="108" cy="123.2" r=".24"/>
<circle cx="108.2" cy="122.3" r=".24"/>
<circle cx="108.2" cy="121.4" r=".23"/>
<circle cx="108.2" cy="79" r=".25"/>
<circle cx="108.1" cy="78.1" r=".26"/>
<circle cx="107.7" cy="77.2" r=".26"/>
<circle cx="107.1" cy="76.4" r=".26"/>
<circle cx="106.4" cy="75.7" r=".25"/>
<circle cx="105.5" cy="75.2" r=".25"/>
<circle cx="104.6" cy="75" r=".26"/>
<circle cx="103.6" cy="74.9" r=".26"/>
</g>
<circle cx="117.8" cy="62.5" r=".76" fill="#008000" stroke="#008000" stroke-width=".2"/>
<circle cx="117.8" cy="62.5" r=".51" fill="#fff" stroke="#000" stroke-width=".2"/>
<circle cx="117.8" cy="59.9" r=".76" fill="#008000" stroke="#008000" stroke-width=".2"/>
<circle cx="117.8" cy="59.9" r=".51" fill="#fff" stroke="#000" stroke-width=".2"/>
<circle cx="120.3" cy="62.5" r=".76" fill="#008000" stroke="#008000" stroke-width=".2"/>
<circle cx="120.3" cy="62.5" r=".51" fill="#fff" stroke="#000" stroke-width=".2"/>
<circle cx="120.3" cy="59.9" r=".76" fill="#008000" stroke="#008000" stroke-width=".2"/>
<circle cx="120.3" cy="59.9" r=".51" fill="#fff" stroke="#000" stroke-width=".2"/>
<circle cx="122.8" cy="62.5" r=".76" fill="#008000" stroke="#008000" stroke-width=".2"/>
<circle cx="122.8" cy="62.5" r=".51" fill="#fff" stroke="#000" stroke-width=".2"/>
<circle cx="122.8" cy="59.9" r=".76" fill="#008000" stroke="#008000" stroke-width=".2"/>
<circle cx="122.8" cy="59.9" r=".51" fill="#fff" stroke="#000" stroke-width=".2"/>
<circle cx="125.4" cy="62.5" r=".76" fill="#008000" stroke="#008000" stroke-width=".2"/>
<circle cx="125.4" cy="62.5" r=".51" fill="#fff" stroke="#000" stroke-width=".2"/>
<circle cx="125.4" cy="59.9" r=".76" fill="#008000" stroke="#008000" stroke-width=".2"/>
<circle cx="125.4" cy="59.9" r=".51" fill="#fff" stroke="#000" stroke-width=".2"/>
<circle cx="127.9" cy="62.5" r=".76" fill="#008000" stroke="#008000" stroke-width=".2"/>
<circle cx="127.9" cy="62.5" r=".51" fill="#fff" stroke="#000" stroke-width=".2"/>
<circle cx="127.9" cy="59.9" r=".76" fill="#008000" stroke="#008000" stroke-width=".2"/>
<circle cx="127.9" cy="59.9" r=".51" fill="#fff" stroke="#000" stroke-width=".2"/>
<circle cx="130.5" cy="62.5" r=".76" fill="#008000" stroke="#008000" stroke-width=".2"/>
<circle cx="130.5" cy="62.5" r=".51" fill="#fff" stroke="#000" stroke-width=".2"/>
<circle cx="130.5" cy="59.9" r=".76" fill="#008000" stroke="#008000" stroke-width=".2"/>
<circle cx="130.5" cy="59.9" r=".51" fill="#fff" stroke="#000" stroke-width=".2"/>
<circle cx="133" cy="62.5" r=".76" fill="#008000" stroke="#008000" stroke-width=".2"/>
<circle cx="133" cy="62.5" r=".51" fill="#fff" stroke="#000" stroke-width=".2"/>
<circle cx="133" cy="59.9" r=".76" fill="#008000" stroke="#008000" stroke-width=".2"/>
<circle cx="133" cy="59.9" r=".51" fill="#fff" stroke="#000" stroke-width=".2"/>
<circle cx="135.5" cy="62.5" r=".76" fill="#008000" stroke="#008000" stroke-width=".2"/>
<circle cx="135.5" cy="62.5" r=".51" fill="#fff" stroke="#000" stroke-width=".2"/>
<circle cx="135.5" cy="59.9" r=".76" fill="#008000" stroke="#008000" stroke-width=".2"/>
<circle cx="135.5" cy="59.9" r=".51" fill="#fff" stroke="#000" stroke-width=".2"/>
<circle cx="138.1" cy="62.5" r=".76" fill="#008000" stroke="#008000" stroke-width=".2"/>
<circle cx="138.1" cy="62.5" r=".51" fill="#fff" stroke="#000" stroke-width=".2"/>
<circle cx="138.1" cy="59.9" r=".76" fill="#008000" stroke="#008000" stroke-width=".2"/>
<circle cx="138.1" cy="59.9" r=".51" fill="#fff" stroke="#000" stroke-width=".2"/>
<circle cx="140.6" cy="62.5" r=".76" fill="#008000" stroke="#008000" stroke-width=".2"/>
<circle cx="140.6" cy="62.5" r=".51" fill="#fff" stroke="#000" stroke-width=".2"/>
<circle cx="140.6" cy="59.9" r=".76" fill="#008000" stroke="#008000" stroke-width=".2"/>
<circle cx="140.6" cy="59.9" r=".51" fill="#fff" stroke="#000" stroke-width=".2"/>
<circle cx="143.1" cy="62.5" r=".76" fill="#008000" stroke="#008000" stroke-width=".2"/>
<circle cx="143.1" cy="62.5" r=".51" fill="#fff" stroke="#000" stroke-width=".2"/>
<circle cx="143.1" cy="59.9" r=".76" fill="#008000" stroke="#008000" stroke-width=".2"/>
<circle cx="143.1" cy="59.9" r=".51" fill="#fff" stroke="#000" stroke-width=".2"/>
<circle cx="145.7" cy="62.5" r=".76" fill="#008000" stroke="#008000" stroke-width=".2"/>
<circle cx="145.7" cy="62.5" r=".51" fill="#fff" stroke="#000" stroke-width=".2"/>
<circle cx="145.7" cy="59.9" r=".76" fill="#008000" stroke="#008000" stroke-width=".2"/>
<circle cx="145.7" cy="59.9" r=".51" fill="#fff" stroke="#000" stroke-width=".2"/>
<circle cx="148.2" cy="62.5" r=".76" fill="#008000" stroke="#008000" stroke-width=".2"/>
<circle cx="148.2" cy="62.5" r=".51" fill="#fff" stroke="#000" stroke-width=".2"/>
<circle cx="148.2" cy="59.9" r=".76" fill="#008000" stroke="#008000" stroke-width=".2"/>
<circle cx="148.2" cy="59.9" r=".51" fill="#fff" stroke="#000" stroke-width=".2"/>
<circle cx="150.7" cy="62.5" r=".76" fill="#008000" stroke="#008000" stroke-width=".2"/>
<circle cx="150.7" cy="62.5" r=".51" fill="#fff" stroke="#000" stroke-width=".2"/>
<circle cx="150.7" cy="59.9" r=".76" fill="#008000" stroke="#008000" stroke-width=".2"/>
<circle cx="150.7" cy="59.9" r=".51" fill="#fff" stroke="#000" stroke-width=".2"/>
<circle cx="153.3" cy="62.5" r=".76" fill="#008000" stroke="#008000" stroke-width=".2"/>
<circle cx="153.3" cy="62.5" r=".51" fill="#fff" stroke="#000" stroke-width=".2"/>
<circle cx="153.3" cy="59.9" r=".76" fill="#008000" stroke="#008000" stroke-width=".2"/>
<circle cx="153.3" cy="59.9" r=".51" fill="#fff" stroke="#000" stroke-width=".2"/>
<circle cx="155.8" cy="62.5" r=".76" fill="#008000" stroke="#008000" stroke-width=".2"/>
<circle cx="155.8" cy="62.5" r=".51" fill="#fff" stroke="#000" stroke-width=".2"/>
<circle cx="155.8" cy="59.9" r=".76" fill="#008000" stroke="#008000" stroke-width=".2"/>
<circle cx="155.8" cy="59.9" r=".51" fill="#fff" stroke="#000" stroke-width=".2"/>
<circle cx="158.4" cy="62.5" r=".76" fill="#008000" stroke="#008000" stroke-width=".2"/>
<circle cx="158.4" cy="62.5" r=".51" fill="#fff" stroke="#000" stroke-width=".2"/>
<circle cx="158.4" cy="59.9" r=".76" fill="#008000" stroke="#008000" stroke-width=".2"/>
<circle cx="158.4" cy="59.9" r=".51" fill="#fff" stroke="#000" stroke-width=".2"/>
<circle cx="160.9" cy="62.5" r=".76" fill="#008000" stroke="#008000" stroke-width=".2"/>
<circle cx="160.9" cy="62.5" r=".51" fill="#fff" stroke="#000" stroke-width=".2"/>
<circle cx="160.9" cy="59.9" r=".76" fill="#008000" stroke="#008000" stroke-width=".2"/>
<circle cx="160.9" cy="59.9" r=".51" fill="#fff" stroke="#000" stroke-width=".2"/>
<circle cx="163.4" cy="62.5" r=".76" fill="#008000" stroke="#008000" stroke-width=".2"/>
<circle cx="163.4" cy="62.5" r=".51" fill="#fff" stroke="#000" stroke-width=".2"/>
<circle cx="163.4" cy="59.9" r=".76" fill="#008000" stroke="#008000" stroke-width=".2"/>
<circle cx="163.4" cy="59.9" r=".51" fill="#fff" stroke="#000" stroke-width=".2"/>
<circle cx="166" cy="62.5" r=".76" fill="#008000" stroke="#008000" stroke-width=".2"/>
<circle cx="166" cy="62.5" r=".51" fill="#fff" stroke="#000" stroke-width=".2"/>
<circle cx="166" cy="59.9" r=".76" fill="#008000" stroke="#008000" stroke-width=".2"/>
<circle cx="166" cy="59.9" r=".51" fill="#fff" stroke="#000" stroke-width=".2"/>
<circle cx="168.5" cy="62.5" r=".76" fill="#008000" stroke="#008000" stroke-width=".2"/>
<circle cx="168.5" cy="62.5" r=".51" fill="#fff" stroke="#000" stroke-width=".2"/>
<circle cx="168.5" cy="59.9" r=".76" fill="#008000" stroke="#008000" stroke-width=".2"/>
<circle cx="168.5" cy="59.9" r=".51" fill="#fff" stroke="#000" stroke-width=".2"/>
<circle cx="171.1" cy="62.5" r=".76" fill="#008000" stroke="#008000" stroke-width=".2"/>
<circle cx="171.1" cy="62.5" r=".51" fill="#fff" stroke="#000" stroke-width=".2"/>
<circle cx="171.1" cy="59.9" r=".76" fill="#008000" stroke="#008000" stroke-width=".2"/>
<circle cx="171.1" cy="59.9" r=".51" fill="#fff" stroke="#000" stroke-width=".2"/>
<circle cx="173.6" cy="62.5" r=".76" fill="#008000" stroke="#008000" stroke-width=".2"/>
<circle cx="173.6" cy="62.5" r=".51" fill="#fff" stroke="#000" stroke-width=".2"/>
<circle cx="173.6" cy="59.9" r=".76" fill="#008000" stroke="#008000" stroke-width=".2"/>
<circle cx="173.6" cy="59.9" r=".51" fill="#fff" stroke="#000" stroke-width=".2"/>
<circle cx="176.1" cy="62.5" r=".76" fill="#008000" stroke="#008000" stroke-width=".2"/>
<circle cx="176.1" cy="62.5" r=".51" fill="#fff" stroke="#000" stroke-width=".2"/>
<circle cx="176.1" cy="59.9" r=".76" fill="#008000" stroke="#008000" stroke-width=".2"/>
<circle cx="176.1" cy="59.9" r=".51" fill="#fff" stroke="#000" stroke-width=".2"/>
<circle cx="178.7" cy="62.5" r=".76" fill="#008000" stroke="#008000" stroke-width=".2"/>
<circle cx="178.7" cy="62.5" r=".51" fill="#fff" stroke="#000" stroke-width=".2"/>
<circle cx="178.7" cy="59.9" r=".76" fill="#008000" stroke="#008000" stroke-width=".2"/>
<circle cx="178.7" cy="59.9" r=".51" fill="#fff" stroke="#000" stroke-width=".2"/>
<circle cx="181.2" cy="62.5" r=".76" fill="#008000" stroke="#008000" stroke-width=".2"/>
<circle cx="181.2" cy="62.5" r=".51" fill="#fff" stroke="#000" stroke-width=".2"/>
<circle cx="181.2" cy="59.9" r=".76" fill="#008000" stroke="#008000" stroke-width=".2"/>
<circle cx="181.2" cy="59.9" r=".51" fill="#fff" stroke="#000" stroke-width=".2"/>
<circle cx="117.8" cy="67.5" r=".76" fill="#008000" stroke="#008000" stroke-width=".2"/>
<circle cx="117.8" cy="67.5" r=".51" fill="#fff" stroke="#000" stroke-width=".2"/>
<circle cx="117.8" cy="65" r=".76" fill="#008000" stroke="#008000" stroke-width=".2"/>
<circle cx="117.8" cy="65" r=".51" fill="#fff" stroke="#000" stroke-width=".2"/>
<circle cx="120.3" cy="67.5" r=".76" fill="#008000" stroke="#008000" stroke-width=".2"/>
<circle cx="120.3" cy="67.5" r=".51" fill="#fff" stroke="#000" stroke-width=".2"/>
<circle cx="120.3" cy="65" r=".76" fill="#008000" stroke="#008000" stroke-width=".2"/>
<circle cx="120.3" cy="65" r=".51" fill="#fff" stroke="#000" stroke-width=".2"/>
<circle cx="122.8" cy="67.5" r=".76" fill="#008000" stroke="#008000" stroke-width=".2"/>
<circle cx="122.8" cy="67.5" r=".51" fill="#fff" stroke="#000" stroke-width=".2"/>
<circle cx="122.8" cy="65" r=".76" fill="#008000" stroke="#008000" stroke-width=".2"/>
<circle cx="122.8" cy="65" r=".51" fill="#fff" stroke="#000" stroke-width=".2"/>
<circle cx="125.3" cy="67.5" r=".76" fill="#008000" stroke="#008000" stroke-width=".2"/>
<circle cx="125.3" cy="67.5" r=".51" fill="#fff" stroke="#000" stroke-width=".2"/>
<circle cx="125.3" cy="65" r=".76" fill="#008000" stroke="#008000" stroke-width=".2"/>
<circle cx="125.3" cy="65" r=".51" fill="#fff" stroke="#000" stroke-width=".2"/>
<circle cx="127.9" cy="67.5" r=".76" fill="#008000" stroke="#008000" stroke-width=".2"/>
<circle cx="127.9" cy="67.5" r=".51" fill="#fff" stroke="#000" stroke-width=".2"/>
<circle cx="127.9" cy="65" r=".76" fill="#008000" stroke="#008000" stroke-width=".2"/>
<circle cx="127.9" cy="65" r=".51" fill="#fff" stroke="#000" stroke-width=".2"/>
<circle cx="130.4" cy="67.5" r=".76" fill="#008000" stroke="#008000" stroke-width=".2"/>
<circle cx="130.4" cy="67.5" r=".51" fill="#fff" stroke="#000" stroke-width=".2"/>
<circle cx="130.4" cy="65" r=".76" fill="#008000" stroke="#008000" stroke-width=".2"/>
<circle cx="130.4" cy="65" r=".51" fill="#fff" stroke="#000" stroke-width=".2"/>
<circle cx="133" cy="67.5" r=".76" fill="#008000" stroke="#008000" stroke-width=".2"/>
<circle cx="133" cy="67.5" r=".51" fill="#fff" stroke="#000" stroke-width=".2"/>
<circle cx="133" cy="65" r=".76" fill="#008000" stroke="#008000" stroke-width=".2"/>
<circle cx="133" cy="65" r=".51" fill="#fff" stroke="#000" stroke-width=".2"/>
<circle cx="135.5" cy="67.5" r=".76" fill="#008000" stroke="#008000" stroke-width=".2"/>
<circle cx="135.5" cy="67.5" r=".51" fill="#fff" stroke="#000" stroke-width=".2"/>
<circle cx="135.5" cy="65" r=".76" fill="#008000" stroke="#008000" stroke-width=".2"/>
<circle cx="135.5" cy="65" r=".51" fill="#fff" stroke="#000" stroke-width=".2"/>
<circle cx="138" cy="67.5" r=".76" fill="#008000" stroke="#008000" stroke-width=".2"/>
<circle cx="138" cy="67.5" r=".51" fill="#fff" stroke="#000" stroke-width=".2"/>
<circle cx="138" cy="65" r=".76" fill="#008000" stroke="#008000" stroke-width=".2"/>
<circle cx="138" cy="65" r=".51" fill="#fff" stroke="#000" stroke-width=".2"/>
<circle cx="140.6" cy="67.5" r=".76" fill="#008000" stroke="#008000" stroke-width=".2"/>
<circle cx="140.6" cy="67.5" r=".51" fill="#fff" stroke="#000" stroke-width=".2"/>
<circle cx="140.6" cy="65" r=".76" fill="#008000" stroke="#008000" stroke-width=".2"/>
<circle cx="140.6" cy="65" r=".51" fill="#fff" stroke="#000" stroke-width=".2"/>
<circle cx="143.1" cy="67.5" r=".76" fill="#008000" stroke="#008000" stroke-width=".2"/>
<circle cx="143.1" cy="67.5" r=".51" fill="#fff" stroke="#000" stroke-width=".2"/>
<circle cx="143.1" cy="65" r=".76" fill="#008000" stroke="#008000" stroke-width=".2"/>
<circle cx="143.1" cy="65" r=".51" fill="#fff" stroke="#000" stroke-width=".2"/>
<circle cx="145.7" cy="67.5" r=".76" fill="#008000" stroke="#008000" stroke-width=".2"/>
<circle cx="145.7" cy="67.5" r=".51" fill="#fff" stroke="#000" stroke-width=".2"/>
<circle cx="145.7" cy="65" r=".76" fill="#008000" stroke="#008000" stroke-width=".2"/>
<circle cx="145.7" cy="65" r=".51" fill="#fff" stroke="#000" stroke-width=".2"/>
<circle cx="148.2" cy="67.5" r=".76" fill="#008000" stroke="#008000" stroke-width=".2"/>
<circle cx="148.2" cy="67.5" r=".51" fill="#fff" stroke="#000" stroke-width=".2"/>
<circle cx="148.2" cy="65" r=".76" fill="#008000" stroke="#008000" stroke-width=".2"/>
<circle cx="148.2" cy="65" r=".51" fill="#fff" stroke="#000" stroke-width=".2"/>
<circle cx="150.7" cy="67.5" r=".76" fill="#008000" stroke="#008000" stroke-width=".2"/>
<circle cx="150.7" cy="67.5" r=".51" fill="#fff" stroke="#000" stroke-width=".2"/>
<circle cx="150.7" cy="65" r=".76" fill="#008000" stroke="#008000" stroke-width=".2"/>
<circle cx="150.7" cy="65" r=".51" fill="#fff" stroke="#000" stroke-width=".2"/>
<circle cx="153.3" cy="67.5" r=".76" fill="#008000" stroke="#008000" stroke-width=".2"/>
<circle cx="153.3" cy="67.5" r=".51" fill="#fff" stroke="#000" stroke-width=".2"/>
<circle cx="153.3" cy="65" r=".76" fill="#008000" stroke="#008000" stroke-width=".2"/>
<circle cx="153.3" cy="65" r=".51" fill="#fff" stroke="#000" stroke-width=".2"/>
<circle cx="155.8" cy="67.5" r=".76" fill="#008000" stroke="#008000" stroke-width=".2"/>
<circle cx="155.8" cy="67.5" r=".51" fill="#fff" stroke="#000" stroke-width=".2"/>
<circle cx="155.8" cy="65" r=".76" fill="#008000" stroke="#008000" stroke-width=".2"/>
<circle cx="155.8" cy="65" r=".51" fill="#fff" stroke="#000" stroke-width=".2"/>
<circle cx="158.4" cy="67.5" r=".76" fill="#008000" stroke="#008000" stroke-width=".2"/>
<circle cx="158.4" cy="67.5" r=".51" fill="#fff" stroke="#000" stroke-width=".2"/>
<circle cx="158.4" cy="65" r=".76" fill="#008000" stroke="#008000" stroke-width=".2"/>
<circle cx="158.4" cy="65" r=".51" fill="#fff" stroke="#000" stroke-width=".2"/>
<circle cx="160.9" cy="67.5" r=".76" fill="#008000" stroke="#008000" stroke-width=".2"/>
<circle cx="160.9" cy="67.5" r=".51" fill="#fff" stroke="#000" stroke-width=".2"/>
<circle cx="160.9" cy="65" r=".76" fill="#008000" stroke="#008000" stroke-width=".2"/>
<circle cx="160.9" cy="65" r=".51" fill="#fff" stroke="#000" stroke-width=".2"/>
<circle cx="163.4" cy="67.5" r=".76" fill="#008000" stroke="#008000" stroke-width=".2"/>
<circle cx="163.4" cy="67.5" r=".51" fill="#fff" stroke="#000" stroke-width=".2"/>
<circle cx="163.4" cy="65" r=".76" fill="#008000" stroke="#008000" stroke-width=".2"/>
<circle cx="163.4" cy="65" r=".51" fill="#fff" stroke="#000" stroke-width=".2"/>
<circle cx="166" cy="67.5" r=".76" fill="#008000" stroke="#008000" stroke-width=".2"/>
<circle cx="166" cy="67.5" r=".51" fill="#fff" stroke="#000" stroke-width=".2"/>
<circle cx="166" cy="65" r=".76" fill="#008000" stroke="#008000" stroke-width=".2"/>
<circle cx="166" cy="65" r=".51" fill="#fff" stroke="#000" stroke-width=".2"/>
<circle cx="168.5" cy="67.5" r=".76" fill="#008000" stroke="#008000" stroke-width=".2"/>
<circle cx="168.5" cy="67.5" r=".51" fill="#fff" stroke="#000" stroke-width=".2"/>
<circle cx="168.5" cy="65" r=".76" fill="#008000" stroke="#008000" stroke-width=".2"/>
<circle cx="168.5" cy="65" r=".51" fill="#fff" stroke="#000" stroke-width=".2"/>
<circle cx="171.1" cy="67.5" r=".76" fill="#008000" stroke="#008000" stroke-width=".2"/>
<circle cx="171.1" cy="67.5" r=".51" fill="#fff" stroke="#000" stroke-width=".2"/>
<circle cx="171.1" cy="65" r=".76" fill="#008000" stroke="#008000" stroke-width=".2"/>
<circle cx="171.1" cy="65" r=".51" fill="#fff" stroke="#000" stroke-width=".2"/>
<circle cx="173.6" cy="67.5" r=".76" fill="#008000" stroke="#008000" stroke-width=".2"/>
<circle cx="173.6" cy="67.5" r=".51" fill="#fff" stroke="#000" stroke-width=".2"/>
<circle cx="173.6" cy="65" r=".76" fill="#008000" stroke="#008000" stroke-width=".2"/>
<circle cx="173.6" cy="65" r=".51" fill="#fff" stroke="#000" stroke-width=".2"/>
<circle cx="176.1" cy="67.5" r=".76" fill="#008000" stroke="#008000" stroke-width=".2"/>
<circle cx="176.1" cy="67.5" r=".51" fill="#fff" stroke="#000" stroke-width=".2"/>
<circle cx="176.1" cy="65" r=".76" fill="#008000" stroke="#008000" stroke-width=".2"/>
<circle cx="176.1" cy="65" r=".51" fill="#fff" stroke="#000" stroke-width=".2"/>
<circle cx="178.7" cy="67.5" r=".76" fill="#008000" stroke="#008000" stroke-width=".2"/>
<circle cx="178.7" cy="67.5" r=".51" fill="#fff" stroke="#000" stroke-width=".2"/>
<circle cx="178.7" cy="65" r=".76" fill="#008000" stroke="#008000" stroke-width=".2"/>
<circle cx="178.7" cy="65" r=".51" fill="#fff" stroke="#000" stroke-width=".2"/>
<circle cx="181.2" cy="67.5" r=".76" fill="#008000" stroke="#008000" stroke-width=".2"/>
<circle cx="181.2" cy="67.5" r=".51" fill="#fff" stroke="#000" stroke-width=".2"/>
<circle cx="181.2" cy="65" r=".76" fill="#008000" stroke="#008000" stroke-width=".2"/>
<circle cx="181.2" cy="65" r=".51" fill="#fff" stroke="#000" stroke-width=".2"/>
<circle cx="186.4" cy="100.8" r=".51" fill="#008000" stroke="#008000" stroke-width=".2"/>
<circle cx="186.4" cy="100.8" r=".25" fill="#fff" stroke="#000" stroke-width=".2"/>
<circle cx="188.4" cy="100.8" r=".51" fill="#008000" stroke="#008000" stroke-width=".2"/>
<circle cx="188.4" cy="100.8" r=".25" fill="#fff" stroke="#000" stroke-width=".2"/>
<circle cx="186.4" cy="98.8" r=".51" fill="#008000" stroke="#008000" stroke-width=".2"/>
<circle cx="186.4" cy="98.8" r=".25" fill="#fff" stroke="#000" stroke-width=".2"/>
<circle cx="188.4" cy="98.8" r=".51" fill="#008000" stroke="#008000" stroke-width=".2"/>
<circle cx="188.4" cy="98.8" r=".25" fill="#fff" stroke="#000" stroke-width=".2"/>
<circle cx="186.4" cy="96.9" r=".51" fill="#008000" stroke="#008000" stroke-width=".2"/>
<circle cx="186.4" cy="96.9" r=".25" fill="#fff" stroke="#000" stroke-width=".2"/>
<circle cx="188.4" cy="96.9" r=".51" fill="#008000" stroke="#008000" stroke-width=".2"/>
<circle cx="188.4" cy="96.9" r=".25" fill="#fff" stroke="#000" stroke-width=".2"/>
<circle cx="186.4" cy="94.8" r=".51" fill="#008000" stroke="#008000" stroke-width=".2"/>
<circle cx="186.4" cy="94.8" r=".25" fill="#fff" stroke="#000" stroke-width=".2"/>
<circle cx="188.4" cy="94.8" r=".51" fill="#008000" stroke="#008000" stroke-width=".2"/>
<circle cx="188.4" cy="94.8" r=".25" fill="#fff" stroke="#000" stroke-width=".2"/>
<circle cx="186.4" cy="92.9" r=".51" fill="#008000" stroke="#008000" stroke-width=".2"/>
<circle cx="186.4" cy="92.9" r=".25" fill="#fff" stroke="#000" stroke-width=".2"/>
<circle cx="188.4" cy="92.9" r=".51" fill="#008000" stroke="#008000" stroke-width=".2"/>
<circle cx="188.4" cy="92.9" r=".25" fill="#fff" stroke="#000" stroke-width=".2"/>
<circle cx="186.4" cy="90.8" r=".51" fill="#008000" stroke="#008000" stroke-width=".2"/>
<circle cx="186.4" cy="90.8" r=".25" fill="#fff" stroke="#000" stroke-width=".2"/>
<circle cx="188.4" cy="90.8" r=".51" fill="#008000" stroke="#008000" stroke-width=".2"/>
<circle cx="188.4" cy="90.8" r=".25" fill="#fff" stroke="#000" stroke-width=".2"/>
<circle cx="186.4" cy="88.9" r=".51" fill="#008000" stroke="#008000" stroke-width=".2"/>
<circle cx="186.4" cy="88.9" r=".25" fill="#fff" stroke="#000" stroke-width=".2"/>
<circle cx="188.4" cy="88.9" r=".51" fill="#008000" stroke="#008000" stroke-width=".2"/>
<circle cx="188.4" cy="88.9" r=".25" fill="#fff" stroke="#000" stroke-width=".2"/>
<circle cx="186.4" cy="86.8" r=".51" fill="#008000" stroke="#008000" stroke-width=".2"/>
<circle cx="186.4" cy="86.8" r=".25" fill="#fff" stroke="#000" stroke-width=".2"/>
<circle cx="188.4" cy="86.8" r=".51" fill="#008000" stroke="#008000" stroke-width=".2"/>
<circle cx="188.4" cy="86.8" r=".25" fill="#fff" stroke="#000" stroke-width=".2"/>
<circle cx="186.4" cy="119.1" r=".51" fill="#008000" stroke="#008000" stroke-width=".2"/>
<circle cx="186.4" cy="119.1" r=".25" fill="#fff" stroke="#000" stroke-width=".2"/>
<circle cx="188.3" cy="119.1" r=".51" fill="#008000" stroke="#008000" stroke-width=".2"/>
<circle cx="188.3" cy="119.1" r=".25" fill="#fff" stroke="#000" stroke-width=".2"/>
<circle cx="186.4" cy="117.1" r=".51" fill="#008000" stroke="#008000" stroke-width=".2"/>
<circle cx="186.4" cy="117.1" r=".25" fill="#fff" stroke="#000" stroke-width=".2"/>
<circle cx="188.3" cy="117.1" r=".51" fill="#008000" stroke="#008000" stroke-width=".2"/>
<circle cx="188.3" cy="117.1" r=".25" fill="#fff" stroke="#000" stroke-width=".2"/>
<circle cx="186.4" cy="115.1" r=".51" fill="#008000" stroke="#008000" stroke-width=".2"/>
<circle cx="186.4" cy="115.1" r=".25" fill="#fff" stroke="#000" stroke-width=".2"/>
<circle cx="188.3" cy="115.1" r=".51" fill="#008000" stroke="#008000" stroke-width=".2"/>
<circle cx="188.3" cy="115.1" r=".25" fill="#fff" stroke="#000" stroke-width=".2"/>
<circle cx="186.4" cy="113.1" r=".51" fill="#008000" stroke="#008000" stroke-width=".2"/>
<circle cx="186.4" cy="113.1" r=".25" fill="#fff" stroke="#000" stroke-width=".2"/>
<circle cx="188.3" cy="113.1" r=".51" fill="#008000" stroke="#008000" stroke-width=".2"/>
<circle cx="188.3" cy="113.1" r=".25" fill="#fff" stroke="#000" stroke-width=".2"/>
<circle cx="186.4" cy="111.1" r=".51" fill="#008000" stroke="#008000" stroke-width=".2"/>
<circle cx="186.4" cy="111.1" r=".25" fill="#fff" stroke="#000" stroke-width=".2"/>
<circle cx="188.3" cy="111.1" r=".51" fill="#008000" stroke="#008000" stroke-width=".2"/>
<circle cx="188.3" cy="111.1" r=".25" fill="#fff" stroke="#000" stroke-width=".2"/>
<circle cx="186.4" cy="109.1" r=".51" fill="#008000" stroke="#008000" stroke-width=".2"/>
<circle cx="186.4" cy="109.1" r=".25" fill="#fff" stroke="#000" stroke-width=".2"/>
<circle cx="188.3" cy="109.1" r=".51" fill="#008000" stroke="#008000" stroke-width=".2"/>
<circle cx="188.3" cy="109.1" r=".25" fill="#fff" stroke="#000" stroke-width=".2"/>
<circle cx="186.4" cy="107.1" r=".51" fill="#008000" stroke="#008000" stroke-width=".2"/>
<circle cx="186.4" cy="107.1" r=".25" fill="#fff" stroke="#000" stroke-width=".2"/>
<circle cx="188.3" cy="107.1" r=".51" fill="#008000" stroke="#008000" stroke-width=".2"/>
<circle cx="188.3" cy="107.1" r=".25" fill="#fff" stroke="#000" stroke-width=".2"/>
<circle cx="186.4" cy="105.1" r=".51" fill="#008000" stroke="#008000" stroke-width=".2"/>
<circle cx="186.4" cy="105.1" r=".25" fill="#fff" stroke="#000" stroke-width=".2"/>
<circle cx="188.3" cy="105.1" r=".51" fill="#008000" stroke="#008000" stroke-width=".2"/>
<circle cx="188.3" cy="105.1" r=".25" fill="#fff" stroke="#000" stroke-width=".2"/>
<circle cx="145.4" cy="111.1" r=".66" fill="#008000" stroke="#008000" stroke-width=".2"/>
<circle cx="145.4" cy="111.1" r=".4" fill="#fff" stroke="#000" stroke-width=".2"/>
<circle cx="145.4" cy="113.6" r=".66" fill="#008000" stroke="#008000" stroke-width=".2"/>
<circle cx="145.4" cy="113.6" r=".4" fill="#fff" stroke="#000" stroke-width=".2"/>
<circle cx="127.7" cy="86.8" r=".51" fill="#008000" stroke="#008000" stroke-width=".2"/>
<circle cx="127.7" cy="86.8" r=".3" fill="#fff" stroke="#000" stroke-width=".2"/>
<circle cx="132" cy="87" r=".51" fill="#008000" stroke="#008000" stroke-width=".2"/>
<circle cx="132" cy="87" r=".3" fill="#fff" stroke="#000" stroke-width=".2"/>
<circle cx="166.4" cy="90.2" r=".51" fill="#008000" stroke="#008000" stroke-width=".2"/>
<circle cx="166.4" cy="90.2" r=".3" fill="#fff" stroke="#000" stroke-width=".2"/>
<circle cx="179.8" cy="103.3" r=".51" fill="#008000" stroke="#008000" stroke-width=".2"/>
<circle cx="179.8" cy="103.3" r=".3" fill="#fff" stroke="#000" stroke-width=".2"/>
<circle cx="132.4" cy="75.3" r=".51" fill="#008000" stroke="#008000" stroke-width=".2"/>
<circle cx="132.4" cy="75.3" r=".3" fill="#fff" stroke="#000" stroke-width=".2"/>
<circle cx="151.4" cy="75.4" r=".51" fill="#008000" stroke="#008000" stroke-width=".2"/>
<circle cx="151.4" cy="75.4" r=".3" fill="#fff" stroke="#000" stroke-width=".2"/>
<circle cx="164.8" cy="103.4" r=".51" fill="#008000" stroke="#008000" stroke-width=".2"/>
<circle cx="164.8" cy="103.4" r=".3" fill="#fff" stroke="#000" stroke-width=".2"/>
<circle cx="164.9" cy="109.5" r=".51" fill="#008000" stroke="#008000" stroke-width=".2"/>
<circle cx="164.9" cy="109.5" r=".3" fill="#fff" stroke="#000" stroke-width=".2"/>
<circle cx="132.3" cy="73.9" r=".51" fill="#008000" stroke="#008000" stroke-width=".2"/>
<circle cx="132.3" cy="73.9" r=".3" fill="#fff" stroke="#000" stroke-width=".2"/>
<circle cx="149.4" cy="74.3" r=".51" fill="#008000" stroke="#008000" stroke-width=".2"/>
<circle cx="149.4" cy="74.3" r=".3" fill="#fff" stroke="#000" stroke-width=".2"/>
<circle cx="165.4" cy="101.2" r=".51" fill="#008000" stroke="#008000" stroke-width=".2"/>
<circle cx="165.4" cy="101.2" r=".3" fill="#fff" stroke="#000" stroke-width=".2"/>
<circle cx="167.1" cy="109.1" r=".51" fill="#008000" stroke="#008000" stroke-width=".2"/>
<circle cx="167.1" cy="109.1" r=".3" fill="#fff" stroke="#000" stroke-width=".2"/>
<circle cx="167.1" cy="114.1" r=".51" fill="#008000" stroke="#008000" stroke-width=".2"/>
<circle cx="167.1" cy="114.1" r=".3" fill="#fff" stroke="#000" stroke-width=".2"/>
<circle cx="166.8" cy="79.9" r=".51" fill="#008000" stroke="#008000" stroke-width=".2"/>
<circle cx="166.8" cy="79.9" r=".3" fill="#fff" stroke="#000" stroke-width=".2"/>
<circle cx="169.1" cy="79.8" r=".51" fill="#008000" stroke="#008000" stroke-width=".2"/>
<circle cx="169.1" cy="79.8" r=".3" fill="#fff" stroke="#000" stroke-width=".2"/>
<circle cx="167.4" cy="100.2" r=".44" fill="#008000" stroke="#008000" stroke-width=".2"/>
<circle cx="167.4" cy="100.2" r=".25" fill="#fff" stroke="#000" stroke-width=".2"/>
<circle cx="186.5" cy="65.5" r=".44" fill="#008000" stroke="#008000" stroke-width=".2"/>
<circle cx="186.5" cy="65.5" r=".25" fill="#fff" stroke="#000" stroke-width=".2"/>
<circle cx="124.1" cy="114.3" r=".51" fill="#008000" stroke="#008000" stroke-width=".2"/>
<circle cx="124.1" cy="114.3" r=".3" fill="#fff" stroke="#000" stroke-width=".2"/>
<circle cx="132.5" cy="80.4" r=".51" fill="#008000" stroke="#008000" stroke-width=".2"/>
<circle cx="132.5" cy="80.4" r=".3" fill="#fff" stroke="#000" stroke-width=".2"/>
<circle cx="149.8" cy="80.4" r=".51" fill="#008000" stroke="#008000" stroke-width=".2"/>
<circle cx="149.8" cy="80.4" r=".3" fill="#fff" stroke="#000" stroke-width=".2"/>
<circle cx="157.7" cy="103.7" r=".51" fill="#008000" stroke="#008000" stroke-width=".2"/>
<circle cx="157.7" cy="103.7" r=".3" fill="#fff" stroke="#000" stroke-width=".2"/>
<circle cx="157.8" cy="114.1" r=".44" fill="#008000" stroke="#008000" stroke-width=".2"/>
<circle cx="157.8" cy="114.1" r=".25" fill="#fff" stroke="#000" stroke-width=".2"/>
<circle cx="157.8" cy="108.6" r=".44" fill="#008000" stroke="#008000" stroke-width=".2"/>
<circle cx="157.8" cy="108.6" r=".25" fill="#fff" stroke="#000" stroke-width=".2"/>
<circle cx="131.6" cy="76.6" r=".51" fill="#008000" stroke="#008000" stroke-width=".2"/>
<circle cx="131.6" cy="76.6" r=".3" fill="#fff" stroke="#000" stroke-width=".2"/>
<circle cx="150.6" cy="76.5" r=".51" fill="#008000" stroke="#008000" stroke-width=".2"/>
<circle cx="150.6" cy="76.5" r=".3" fill="#fff" stroke="#000" stroke-width=".2"/>
<circle cx="163.4" cy="103.7" r=".51" fill="#008000" stroke="#008000" stroke-width=".2"/>
<circle cx="163.4" cy="103.7" r=".3" fill="#fff" stroke="#000" stroke-width=".2"/>
<circle cx="163.3" cy="109.2" r=".51" fill="#008000" stroke="#008000" stroke-width=".2"/>
<circle cx="163.3" cy="109.2" r=".3" fill="#fff" stroke="#000" stroke-width=".2"/>
<circle cx="132.5" cy="77.8" r=".51" fill="#008000" stroke="#008000" stroke-width=".2"/>
<circle cx="132.5" cy="77.8" r=".3" fill="#fff" stroke="#000" stroke-width=".2"/>
<circle cx="149.8" cy="78" r=".51" fill="#008000" stroke="#008000" stroke-width=".2"/>
<circle cx="149.8" cy="78" r=".3" fill="#fff" stroke="#000" stroke-width=".2"/>
<circle cx="161.5" cy="103.8" r=".51" fill="#008000" stroke="#008000" stroke-width=".2"/>
<circle cx="161.5" cy="103.8" r=".3" fill="#fff" stroke="#000" stroke-width=".2"/>
<circle cx="161.6" cy="109.2" r=".51" fill="#008000" stroke="#008000" stroke-width=".2"/>
<circle cx="161.6" cy="109.2" r=".3" fill="#fff" stroke="#000" stroke-width=".2"/>
<circle cx="132" cy="85.6" r=".51" fill="#008000" stroke="#008000" stroke-width=".2"/>
<circle cx="132" cy="85.6" r=".3" fill="#fff" stroke="#000" stroke-width=".2"/>
<circle cx="151.7" cy="85.4" r=".51" fill="#008000" stroke="#008000" stroke-width=".2"/>
<circle cx="151.7" cy="85.4" r=".3" fill="#fff" stroke="#000" stroke-width=".2"/>
<circle cx="152.7" cy="103.5" r=".51" fill="#008000" stroke="#008000" stroke-width=".2"/>
<circle cx="152.7" cy="103.5" r=".3" fill="#fff" stroke="#000" stroke-width=".2"/>
<circle cx="152.7" cy="111.8" r=".51" fill="#008000" stroke="#008000" stroke-width=".2"/>
<circle cx="152.7" cy="111.8" r=".3" fill="#fff" stroke="#000" stroke-width=".2"/>
<circle cx="134.2" cy="89.4" r=".51" fill="#008000" stroke="#008000" stroke-width=".2"/>
<circle cx="134.2" cy="89.4" r=".3" fill="#fff" stroke="#000" stroke-width=".2"/>
<circle cx="150.5" cy="90.5" r=".51" fill="#008000" stroke="#008000" stroke-width=".2"/>
<circle cx="150.5" cy="90.5" r=".3" fill="#fff" stroke="#000" stroke-width=".2"/>
<circle cx="150.4" cy="103.6" r=".51" fill="#008000" stroke="#008000" stroke-width=".2"/>
<circle cx="150.4" cy="103.6" r=".3" fill="#fff" stroke="#000" stroke-width=".2"/>
<circle cx="126" cy="96.8" r=".51" fill="#008000" stroke="#008000" stroke-width=".2"/>
<circle cx="126" cy="96.8" r=".3" fill="#fff" stroke="#000" stroke-width=".2"/>
<circle cx="132.3" cy="92" r=".51" fill="#008000" stroke="#008000" stroke-width=".2"/>
<circle cx="132.3" cy="92" r=".3" fill="#fff" stroke="#000" stroke-width=".2"/>
<circle cx="173.5" cy="89.8" r=".51" fill="#008000" stroke="#008000" stroke-width=".2"/>
<circle cx="173.5" cy="89.8" r=".3" fill="#fff" stroke="#000" stroke-width=".2"/>
<circle cx="189.7" cy="72.9" r=".51" fill="#008000" stroke="#008000" stroke-width=".2"/>
<circle cx="189.7" cy="72.9" r=".3" fill="#fff" stroke="#000" stroke-width=".2"/>
<circle cx="189.7" cy="81.1" r=".51" fill="#008000" stroke="#008000" stroke-width=".2"/>
<circle cx="189.7" cy="81.1" r=".3" fill="#fff" stroke="#000" stroke-width=".2"/>
<circle cx="173" cy="80.8" r=".51" fill="#008000" stroke="#008000" stroke-width=".2"/>
<circle cx="173" cy="80.8" r=".3" fill="#fff" stroke="#000" stroke-width=".2"/>
<circle cx="173.1" cy="83.2" r=".51" fill="#008000" stroke="#008000" stroke-width=".2"/>
<circle cx="173.1" cy="83.2" r=".3" fill="#fff" stroke="#000" stroke-width=".2"/>
<circle cx="173.9" cy="87.2" r=".51" fill="#008000" stroke="#008000" stroke-width=".2"/>
<circle cx="173.9" cy="87.2" r=".3" fill="#fff" stroke="#000" stroke-width=".2"/>
<circle cx="182.1" cy="78.5" r=".51" fill="#008000" stroke="#008000" stroke-width=".2"/>
<circle cx="182.1" cy="78.5" r=".3" fill="#fff" stroke="#000" stroke-width=".2"/>
<circle cx="192.1" cy="79.3" r=".51" fill="#008000" stroke="#008000" stroke-width=".2"/>
<circle cx="192.1" cy="79.3" r=".3" fill="#fff" stroke="#000" stroke-width=".2"/>
<circle cx="136" cy="70.5" r=".34" fill="#008000" stroke="#008000" stroke-width=".2"/>
<circle cx="136" cy="70.5" r=".13" fill="#fff" stroke="#000" stroke-width=".2"/>
<circle cx="127.9" cy="106.1" r=".51" fill="#008000" stroke="#008000" stroke-width=".2"/>
<circle cx="127.9" cy="106.1" r=".3" fill="#fff" stroke="#000" stroke-width=".2"/>
<circle cx="139.4" cy="70.1" r=".44" fill="#008000" stroke="#008000" stroke-width=".2"/>
<circle cx="139.4" cy="70.1" r=".25" fill="#fff" stroke="#000" stroke-width=".2"/>
<circle cx="128" cy="101.8" r=".51" fill="#008000" stroke="#008000" stroke-width=".2"/>
<circle cx="128" cy="101.8" r=".3" fill="#fff" stroke="#000" stroke-width=".2"/>
<circle cx="132.2" cy="99.3" r=".51" fill="#008000" stroke="#008000" stroke-width=".2"/>
<circle cx="132.2" cy="99.3" r=".3" fill="#fff" stroke="#000" stroke-width=".2"/>
<circle cx="139.3" cy="99.2" r=".51" fill="#008000" stroke="#008000" stroke-width=".2"/>
<circle cx="139.3" cy="99.2" r=".3" fill="#fff" stroke="#000" stroke-width=".2"/>
<circle cx="139.3" cy="106.5" r=".51" fill="#008000" stroke="#008000" stroke-width=".2"/>
<circle cx="139.3" cy="106.5" r=".3" fill="#fff" stroke="#000" stroke-width=".2"/>
<circle cx="119.1" cy="102.9" r=".51" fill="#008000" stroke="#008000" stroke-width=".2"/>
<circle cx="119.1" cy="102.9" r=".3" fill="#fff" stroke="#000" stroke-width=".2"/>
<circle cx="132.1" cy="97.2" r=".51" fill="#008000" stroke="#008000" stroke-width=".2"/>
<circle cx="132.1" cy="97.2" r=".3" fill="#fff" stroke="#000" stroke-width=".2"/>
<circle cx="136.9" cy="97.4" r=".51" fill="#008000" stroke="#008000" stroke-width=".2"/>
<circle cx="136.9" cy="97.4" r=".3" fill="#fff" stroke="#000" stroke-width=".2"/>
<circle cx="136.9" cy="102.9" r=".51" fill="#008000" stroke="#008000" stroke-width=".2"/>
<circle cx="136.9" cy="102.9" r=".3" fill="#fff" stroke="#000" stroke-width=".2"/>
<circle cx="114.9" cy="102.8" r=".51" fill="#008000" stroke="#008000" stroke-width=".2"/>
<circle cx="114.9" cy="102.8" r=".3" fill="#fff" stroke="#000" stroke-width=".2"/>
<circle cx="131.5" cy="103.9" r=".51" fill="#008000" stroke="#008000" stroke-width=".2"/>
<circle cx="131.5" cy="103.9" r=".3" fill="#fff" stroke="#000" stroke-width=".2"/>
<circle cx="132.1" cy="84.3" r=".51" fill="#008000" stroke="#008000" stroke-width=".2"/>
<circle cx="132.1" cy="84.3" r=".3" fill="#fff" stroke="#000" stroke-width=".2"/>
<circle cx="166.1" cy="84.3" r=".51" fill="#008000" stroke="#008000" stroke-width=".2"/>
<circle cx="166.1" cy="84.3" r=".3" fill="#fff" stroke="#000" stroke-width=".2"/>
<circle cx="169.7" cy="84.3" r=".51" fill="#008000" stroke="#008000" stroke-width=".2"/>
<circle cx="169.7" cy="84.3" r=".3" fill="#fff" stroke="#000" stroke-width=".2"/>
<circle cx="131.8" cy="81.7" r=".51" fill="#008000" stroke="#008000" stroke-width=".2"/>
<circle cx="131.8" cy="81.7" r=".3" fill="#fff" stroke="#000" stroke-width=".2"/>
<circle cx="166.3" cy="81.6" r=".51" fill="#008000" stroke="#008000" stroke-width=".2"/>
<circle cx="166.3" cy="81.6" r=".3" fill="#fff" stroke="#000" stroke-width=".2"/>
<circle cx="179.4" cy="81.7" r=".51" fill="#008000" stroke="#008000" stroke-width=".2"/>
<circle cx="179.4" cy="81.7" r=".3" fill="#fff" stroke="#000" stroke-width=".2"/>
<circle cx="186.3" cy="82.5" r=".51" fill="#008000" stroke="#008000" stroke-width=".2"/>
<circle cx="186.3" cy="82.5" r=".3" fill="#fff" stroke="#000" stroke-width=".2"/>
<circle cx="183.8" cy="101" r=".51" fill="#008000" stroke="#008000" stroke-width=".2"/>
<circle cx="183.8" cy="101" r=".3" fill="#fff" stroke="#000" stroke-width=".2"/>
<circle cx="179.8" cy="96.4" r=".51" fill="#008000" stroke="#008000" stroke-width=".2"/>
<circle cx="179.8" cy="96.4" r=".3" fill="#fff" stroke="#000" stroke-width=".2"/>
<circle cx="179.1" cy="92.9" r=".51" fill="#008000" stroke="#008000" stroke-width=".2"/>
<circle cx="179.1" cy="92.9" r=".3" fill="#fff" stroke="#000" stroke-width=".2"/>
<circle cx="178.7" cy="88" r=".51" fill="#008000" stroke="#008000" stroke-width=".2"/>
<circle cx="178.7" cy="88" r=".3" fill="#fff" stroke="#000" stroke-width=".2"/>
<circle cx="175.6" cy="85.8" r=".51" fill="#008000" stroke="#008000" stroke-width=".2"/>
<circle cx="175.6" cy="85.8" r=".3" fill="#fff" stroke="#000" stroke-width=".2"/>
<circle cx="175.7" cy="83" r=".51" fill="#008000" stroke="#008000" stroke-width=".2"/>
<circle cx="175.7" cy="83" r=".3" fill="#fff" stroke="#000" stroke-width=".2"/>
<circle cx="175.6" cy="80.8" r=".51" fill="#008000" stroke="#008000" stroke-width=".2"/>
<circle cx="175.6" cy="80.8" r=".3" fill="#fff" stroke="#000" stroke-width=".2"/>
<circle cx="167" cy="76.2" r=".51" fill="#008000" stroke="#008000" stroke-width=".2"/>
<circle cx="167" cy="76.2" r=".3" fill="#fff" stroke="#000" stroke-width=".2"/>
<circle cx="161.9" cy="73.2" r=".51" fill="#008000" stroke="#008000" stroke-width=".2"/>
<circle cx="161.9" cy="73.2" r=".3" fill="#fff" stroke="#000" stroke-width=".2"/>
<circle cx="132.9" cy="83" r=".59" fill="#008000" stroke="#008000" stroke-width=".2"/>
<circle cx="132.9" cy="83" r=".4" fill="#fff" stroke="#000" stroke-width=".2"/>
<circle cx="153.1" cy="83" r=".59" fill="#008000" stroke="#008000" stroke-width=".2"/>
<circle cx="153.1" cy="83" r=".4" fill="#fff" stroke="#000" stroke-width=".2"/>
<circle cx="156.2" cy="98.9" r=".59" fill="#008000" stroke="#008000" stroke-width=".2"/>
<circle cx="156.2" cy="98.9" r=".4" fill="#fff" stroke="#000" stroke-width=".2"/>
<circle cx="175.5" cy="99" r=".59" fill="#008000" stroke="#008000" stroke-width=".2"/>
<circle cx="175.5" cy="99" r=".4" fill="#fff" stroke="#000" stroke-width=".2"/>
<circle cx="178.8" cy="99.3" r=".59" fill="#008000" stroke="#008000" stroke-width=".2"/>
<circle cx="178.8" cy="99.3" r=".4" fill="#fff" stroke="#000" stroke-width=".2"/>
<circle cx="119.1" cy="73.3" r=".59" fill="#008000" stroke="#008000" stroke-width=".2"/>
<circle cx="119.1" cy="73.3" r=".4" fill="#fff" stroke="#000" stroke-width=".2"/>
<circle cx="128.5" cy="94" r=".51" fill="#008000" stroke="#008000" stroke-width=".2"/>
<circle cx="128.5" cy="94" r=".3" fill="#fff" stroke="#000" stroke-width=".2"/>
<circle cx="132.3" cy="94" r=".51" fill="#008000" stroke="#008000" stroke-width=".2"/>
<circle cx="132.3" cy="94" r=".3" fill="#fff" stroke="#000" stroke-width=".2"/>
<circle cx="143" cy="94.1" r=".51" fill="#008000" stroke="#008000" stroke-width=".2"/>
<circle cx="143" cy="94.1" r=".3" fill="#fff" stroke="#000" stroke-width=".2"/>
<circle cx="128.5" cy="95.5" r=".51" fill="#008000" stroke="#008000" stroke-width=".2"/>
<circle cx="128.5" cy="95.5" r=".3" fill="#fff" stroke="#000" stroke-width=".2"/>
<circle cx="132.2" cy="95.5" r=".51" fill="#008000" stroke="#008000" stroke-width=".2"/>
<circle cx="132.2" cy="95.5" r=".3" fill="#fff" stroke="#000" stroke-width=".2"/>
<circle cx="148.2" cy="94.9" r=".51" fill="#008000" stroke="#008000" stroke-width=".2"/>
<circle cx="148.2" cy="94.9" r=".3" fill="#fff" stroke="#000" stroke-width=".2"/>
<circle cx="131.9" cy="79.1" r=".51" fill="#008000" stroke="#008000" stroke-width=".2"/>
<circle cx="131.9" cy="79.1" r=".3" fill="#fff" stroke="#000" stroke-width=".2"/>
<circle cx="150.9" cy="79.2" r=".51" fill="#008000" stroke="#008000" stroke-width=".2"/>
<circle cx="150.9" cy="79.2" r=".3" fill="#fff" stroke="#000" stroke-width=".2"/>
<circle cx="159.8" cy="103.7" r=".51" fill="#008000" stroke="#008000" stroke-width=".2"/>
<circle cx="159.8" cy="103.7" r=".3" fill="#fff" stroke="#000" stroke-width=".2"/>
<circle cx="156.1" cy="110.7" r=".44" fill="#008000" stroke="#008000" stroke-width=".2"/>
<circle cx="156.1" cy="110.7" r=".25" fill="#fff" stroke="#000" stroke-width=".2"/>
<circle cx="112.4" cy="60.1" r="2.16" fill="#008000" stroke="#008000" stroke-width=".2"/>
<circle cx="112.4" cy="60.1" r="1.65" fill="#fff" stroke="#000" stroke-width=".2"/>
<circle cx="186" cy="60.1" r="2.16" fill="#008000" stroke="#008000" stroke-width=".2"/>
<circle cx="186" cy="60.1" r="1.65" fill="#fff" stroke="#000" stroke-width=".2"/>
<circle cx="188.6" cy="145.8" r="2.16" fill="#008000" stroke="#008000" stroke-width=".2"/>
<circle cx="188.6" cy="145.8" r="1.65" fill="#fff" stroke="#000" stroke-width=".2"/>
<circle cx="108.6" cy="145.8" r="2.16" fill="#008000" stroke="#008000" stroke-width=".2"/>
<circle cx="108.6" cy="145.8" r="1.65" fill="#fff" stroke="#000" stroke-width=".2"/>
<circle cx="168.1" cy="97.2" r=".51" fill="#008000" stroke="#008000" stroke-width=".2"/>
<circle cx="168.1" cy="97.2" r=".3" fill="#fff" stroke="#000" stroke-width=".2"/>
<circle cx="146.9" cy="97.2" r=".51" fill="#008000" stroke="#008000" stroke-width=".2"/>
<circle cx="146.9" cy="97.2" r=".3" fill="#fff" stroke="#000" stroke-width=".2"/>
<circle cx="165" cy="73" r=".51" fill="#008000" stroke="#008000" stroke-width=".2"/>
<circle cx="165" cy="73" r=".3" fill="#fff" stroke="#000" stroke-width=".2"/>
<circle cx="167" cy="73" r=".51" fill="#008000" stroke="#008000" stroke-width=".2"/>
<circle cx="167" cy="73" r=".3" fill="#fff" stroke="#000" stroke-width=".2"/>
<circle cx="171.4" cy="73" r=".51" fill="#008000" stroke="#008000" stroke-width=".2"/>
<circle cx="171.4" cy="73" r=".3" fill="#fff" stroke="#000" stroke-width=".2"/>
<circle cx="185" cy="76.9" r=".51" fill="#008000" stroke="#008000" stroke-width=".2"/>
<circle cx="185" cy="76.9" r=".3" fill="#fff" stroke="#000" stroke-width=".2"/>
<circle cx="187.4" cy="89.9" r=".51" fill="#008000" stroke="#008000" stroke-width=".2"/>
<circle cx="187.4" cy="89.9" r=".3" fill="#fff" stroke="#000" stroke-width=".2"/>
<circle cx="164.9" cy="71.2" r=".51" fill="#008000" stroke="#008000" stroke-width=".2"/>
<circle cx="164.9" cy="71.2" r=".3" fill="#fff" stroke="#000" stroke-width=".2"/>
<circle cx="167" cy="71.2" r=".51" fill="#008000" stroke="#008000" stroke-width=".2"/>
<circle cx="167" cy="71.2" r=".3" fill="#fff" stroke="#000" stroke-width=".2"/>
<circle cx="174.8" cy="71.3" r=".51" fill="#008000" stroke="#008000" stroke-width=".2"/>
<circle cx="174.8" cy="71.3" r=".3" fill="#fff" stroke="#000" stroke-width=".2"/>
<circle cx="187.7" cy="75.3" r=".44" fill="#008000" stroke="#008000" stroke-width=".2"/>
<circle cx="187.7" cy="75.3" r=".25" fill="#fff" stroke="#000" stroke-width=".2"/>
<circle cx="189.6" cy="90" r=".44" fill="#008000" stroke="#008000" stroke-width=".2"/>
<circle cx="189.6" cy="90" r=".25" fill="#fff" stroke="#000" stroke-width=".2"/>
<g fill="#800000" stroke="#800000" stroke-width=".2">
<path d="M111.7 99.4h.7v2h-.7z"/>
<path d="M113 99.4h.7v2h-.7z"/>
<path d="M114.3 99.4h.7v2h-.7z"/>
<path d="M115.5 99.4h.7v2h-.7z"/>
<path d="M116.8 99.4h.7v2h-.7z"/>
<path d="M118.1 99.4h.7v2h-.7z"/>
<path d="M119.4 99.4h.6v2h-.6z"/>
<path d="M120.6 99.4h.7v2h-.7z"/>
<path d="M120.6 89.3h.7v2.1h-.7z"/>
<path d="M119.4 89.3h.6v2.1h-.6z"/>
<path d="M118.1 89.3h.7v2.1h-.7z"/>
<path d="M116.8 89.3h.7v2.1h-.7z"/>
<path d="M115.5 89.3h.7v2.1h-.7z"/>
<path d="M114.3 89.3h.7v2.1h-.7z"/>
<path d="M113 89.3h.7v2.1h-.7z"/>
<path d="M111.7 89.3h.7v2.1h-.7z"/>
<path d="M121.9 99.4h.7v2h-.7z"/>
<path d="M123.2 99.4h.6v2h-.6z"/>
<path d="M121.9 89.3h.7v2.1h-.7z"/>
<path d="M123.2 89.3h.6v2.1h-.6z"/>
<path d="M123.3 109.7h1.3v1.5h-1.3z"/>
<path d="M121.6 109.7h1.3v1.5h-1.3z"/>
<path d="M117.3 116.1h1.5v1.3h-1.5z"/>
<path d="M117.3 114.4h1.5v1.3h-1.5z"/>
<path d="M118.2 105.3h1.3v1.5h-1.3z"/>
<path d="M116.5 105.3h1.3v1.5h-1.3z"/>
<path d="M123.3 105.3h1.3v1.5h-1.3z"/>
<path d="M121.6 105.3h1.3v1.5h-1.3z"/>
<path d="M117.3 111.2h1.5v1.3h-1.5z"/>
<path d="M117.3 109.5h1.5v1.3h-1.5z"/>
</g>
<g fill="none" stroke="#800000" stroke-width=".42">
<path d="M133 59.9v.2l-1.3 1.3v7.9l-1.3 1.2-.1 44.9-1.3 1.4h-10.9M138.1 59.9v.8l-1.3 1v7.7l-.8 1.1M140.6 59.9l-1 1-.2 .5v8.7M173.6 59.9v3l-.6 .8h-20.9l-1.4 1.3h-2.5M178.7 59.9l1.2-1.4h2.7v1.9l3.9 3.9v1.2M131.9 79.1l19 .1M132.3 73.9h17.1v.4M132.4 75.3h19.3l-.3 .1M132.5 77.8l16.4 .2-.3-.1M135.5 67.5l-.4 .4v3.8h5.5M135.5 62.5l-1.2 1.5v8.2l.7 .8 24.8-.1 7 7M140.6 71.7l5.1 .1"/>
<path d="M140.7 67.6l-.1 4.1M143.1 65h2.6M145.7 67.5h.1M145.7 67.5v4.3M148.6 77.9h.1M148.6 77.9l1.2 .1M150.6 76.5l-19 .1M150.7 67.5v3.7M150.7 71.2l-5 .6M158.4 65h1l.3 .3v5.9M163.4 67.5v3.7h-12.7M163.4 69.2h4.6"/>
<path d="M164.9 71.2h2.1M165 73h2.3h-.3M168 69.2l.1 14.7-1.9 2.9M169.1 79.8h21.4l1.7 1.7v30.6l-1 1.1-2.9-.1M171.4 73h7.5l.1 3.2 .1 .2h5.3l.6 .5M173.6 62.5h.2l1.2-1.3h7.4l2.2 2.3v8.2l1.1 1.2h4M174.8 71.3h6.3l.8 .8v3.1l5.8 .1M181.2 65l-2.5 2.5-2.6-2.5-2.5 2.5-2.5-2.5-2.6 2.5v1.7h-.5M182.1 78.5h9.2l.8 .8M126 96.8h-3.3l-.5 .5v8.8h-3.3v3.3l-.8 .8M127.7 86.8h-12.2l-.9 1.1v5.9l2.4 2.4 .2 9.9M128.5 94h-8.9l-.6 .6v2.3l.7 .7v2.8"/>
<path d="M128.5 95.5l-.1-.1h-8.5l1.1 1v4M132.1 97.2h4.6l.2 .2M132.3 92h41.2M132.3 94l10.7 .1M132.5 80.4h17.4h-.1M134.2 89.4h16.3M139.3 99.2l-.1 .1h-7M139.3 99.2v7.3M139.3 99.2h.1M148.2 94.9l-.6 .6h-15.4M148.5 97.2h-.2M148.9 81.6h17.4"/>
<path d="M148.9 81.6h.1M150.2 81.6l-18.4 .1M150.5 89.4h.1M150.5 89.4v1.1M151.7 85.4l-19.7 .2M166.1 84.3h-34M166.2 86.8l-34.2 .2M166.2 86.8v3.3l.2 .1M169.7 84.3h17.6l1.2 1.1-.1 1.4M173 80.8l.1 2.4M173.5 92l3.3 3.3v10.4l1.4 1.4h8.2M173.5 89.8v2.2"/>
<path d="M173.9 87.2h.1M173.9 87.2l3.7 3.7 8.8-.1M175.6 80.8l.1 .1M179.4 81.7h6.2l.7 .8M187.4 89.9v10.4l.6 .5h.4M189.6 90l.3 .4v7.7l-.8 .7h-.7M189.7 81.1v1.2l1.6 1.8v24.1l-3 .9M115.9 100.4v1.5l-1 .9M118.4 100.4v1.8l.7 .7M122.2 100.4h.1M122.3 110.5l-.3-.3h-5.6l-.6 .5v3.8l.6 .5 1.7 .1M124 106l3.9 .1"/>
<path d="M124 110.5l.1 3.8M128 101.8l1.3 1.3v11.5l-1.3 1.3h-5.8l-.9-1v-1.8l-1.2-1.2h-2M136.9 102.9h-3.8l-1.1 1h-.5M150.4 103.6v8.5l1 1h35M152.7 103.5v8.3M157.7 103.7l.1 4.9M157.8 114.1l-.1 3.6 .6 .4h29l1 1M159.8 103.7v6.7l.7 .7h25.9M159.8 110.3h-3.2l-.5 .4M161.5 103.8l.1 5.4M163.4 103.7l-.1 5.5M164.8 103.4v6l.1 .1"/>
<path d="M165.4 101.2v1l1.1 1v5.3l.6 .6M167.1 114.1h20.1l1.1 1M167.4 100.2h-21.8v10.8l-.2 .1M179.8 103.3h4.8l.5-.5h4.4l.8 .8v3.1l-.4 .4h-1.6M184 100.8l-.2 .2M184.8 118.1l-.1 .1 .3-.1M188.3 107.1h.1"/>
</g>
<path d="M117.8 65h-2.8l-2.9 2.9v3.9l1.6 1.5h5.4M161.9 73.2l.4 .2 2.9 2.8h1.8M132.9 83h20.2M146.9 97.2h1.4M148.5 97.2h19.6M156.2 98.9h19.2l.1 .1M175.6 85.8l2.2 2.2h.9M175.7 80.9v2.1M179.1 92.9l.7 .7v2.8M186.4 98.8l-.4 .5h-7.2M184 100.8h2.4" fill="none" stroke="#800000" stroke-width="1"/>
<circle cx="117.8" cy="62.5" r=".76" fill="#008000" stroke="#008000" stroke-width=".2"/>
<circle cx="117.8" cy="62.5" r=".51" fill="#fff" stroke="#000" stroke-width=".2"/>
<circle cx="117.8" cy="59.9" r=".76" fill="#008000" stroke="#008000" stroke-width=".2"/>
<circle cx="117.8" cy="59.9" r=".51" fill="#fff" stroke="#000" stroke-width=".2"/>
<circle cx="120.3" cy="62.5" r=".76" fill="#008000" stroke="#008000" stroke-width=".2"/>
<circle cx="120.3" cy="62.5" r=".51" fill="#fff" stroke="#000" stroke-width=".2"/>
<circle cx="120.3" cy="59.9" r=".76" fill="#008000" stroke="#008000" stroke-width=".2"/>
<circle cx="120.3" cy="59.9" r=".51" fill="#fff" stroke="#000" stroke-width=".2"/>
<circle cx="122.8" cy="62.5" r=".76" fill="#008000" stroke="#008000" stroke-width=".2"/>
<circle cx="122.8" cy="62.5" r=".51" fill="#fff" stroke="#000" stroke-width=".2"/>
<circle cx="122.8" cy="59.9" r=".76" fill="#008000" stroke="#008000" stroke-width=".2"/>
<circle cx="122.8" cy="59.9" r=".51" fill="#fff" stroke="#000" stroke-width=".2"/>
<circle cx="125.4" cy="62.5" r=".76" fill="#008000" stroke="#008000" stroke-width=".2"/>
<circle cx="125.4" cy="62.5" r=".51" fill="#fff" stroke="#000" stroke-width=".2"/>
<circle cx="125.4" cy="59.9" r=".76" fill="#008000" stroke="#008000" stroke-width=".2"/>
<circle cx="125.4" cy="59.9" r=".51" fill="#fff" stroke="#000" stroke-width=".2"/>
<circle cx="127.9" cy="62.5" r=".76" fill="#008000" stroke="#008000" stroke-width=".2"/>
<circle cx="127.9" cy="62.5" r=".51" fill="#fff" stroke="#000" stroke-width=".2"/>
<circle cx="127.9" cy="59.9" r=".76" fill="#008000" stroke="#008000" stroke-width=".2"/>
<circle cx="127.9" cy="59.9" r=".51" fill="#fff" stroke="#000" stroke-width=".2"/>
<circle cx="130.5" cy="62.5" r=".76" fill="#008000" stroke="#008000" stroke-width=".2"/>
<circle cx="130.5" cy="62.5" r=".51" fill="#fff" stroke="#000" stroke-width=".2"/>
<circle cx="130.5" cy="59.9" r=".76" fill="#008000" stroke="#008000" stroke-width=".2"/>
<circle cx="130.5" cy="59.9" r=".51" fill="#fff" stroke="#000" stroke-width=".2"/>
<circle cx="133" cy="62.5" r=".76" fill="#008000" stroke="#008000" stroke-width=".2"/>
<circle cx="133" cy="62.5" r=".51" fill="#fff" stroke="#000" stroke-width=".2"/>
<circle cx="133" cy="59.9" r=".76" fill="#008000" stroke="#008000" stroke-width=".2"/>
<circle cx="133" cy="59.9" r=".51" fill="#fff" stroke="#000" stroke-width=".2"/>
<circle cx="135.5" cy="62.5" r=".76" fill="#008000" stroke="#008000" stroke-width=".2"/>
<circle cx="135.5" cy="62.5" r=".51" fill="#fff" stroke="#000" stroke-width=".2"/>
<circle cx="135.5" cy="59.9" r=".76" fill="#008000" stroke="#008000" stroke-width=".2"/>
<circle cx="135.5" cy="59.9" r=".51" fill="#fff" stroke="#000" stroke-width=".2"/>
<circle cx="138.1" cy="62.5" r=".76" fill="#008000" stroke="#008000" stroke-width=".2"/>
<circle cx="138.1" cy="62.5" r=".51" fill="#fff" stroke="#000" stroke-width=".2"/>
<circle cx="138.1" cy="59.9" r=".76" fill="#008000" stroke="#008000" stroke-width=".2"/>
<circle cx="138.1" cy="59.9" r=".51" fill="#fff" stroke="#000" stroke-width=".2"/>
<circle cx="140.6" cy="62.5" r=".76" fill="#008000" stroke="#008000" stroke-width=".2"/>
<circle cx="140.6" cy="62.5" r=".51" fill="#fff" stroke="#000" stroke-width=".2"/>
<circle cx="140.6" cy="59.9" r=".76" fill="#008000" stroke="#008000" stroke-width=".2"/>
<circle cx="140.6" cy="59.9" r=".51" fill="#fff" stroke="#000" stroke-width=".2"/>
<circle cx="143.1" cy="62.5" r=".76" fill="#008000" stroke="#008000" stroke-width=".2"/>
<circle cx="143.1" cy="62.5" r=".51" fill="#fff" stroke="#000" stroke-width=".2"/>
<circle cx="143.1" cy="59.9" r=".76" fill="#008000" stroke="#008000" stroke-width=".2"/>
<circle cx="143.1" cy="59.9" r=".51" fill="#fff" stroke="#000" stroke-width=".2"/>
<circle cx="145.7" cy="62.5" r=".76" fill="#008000" stroke="#008000" stroke-width=".2"/>
<circle cx="145.7" cy="62.5" r=".51" fill="#fff" stroke="#000" stroke-width=".2"/>
<circle cx="145.7" cy="59.9" r=".76" fill="#008000" stroke="#008000" stroke-width=".2"/>
<circle cx="145.7" cy="59.9" r=".51" fill="#fff" stroke="#000" stroke-width=".2"/>
<circle cx="148.2" cy="62.5" r=".76" fill="#008000" stroke="#008000" stroke-width=".2"/>
<circle cx="148.2" cy="62.5" r=".51" fill="#fff" stroke="#000" stroke-width=".2"/>
<circle cx="148.2" cy="59.9" r=".76" fill="#008000" stroke="#008000" stroke-width=".2"/>
<circle cx="148.2" cy="59.9" r=".51" fill="#fff" stroke="#000" stroke-width=".2"/>
<circle cx="150.7" cy="62.5" r=".76" fill="#008000" stroke="#008000" stroke-width=".2"/>
<circle cx="150.7" cy="62.5" r=".51" fill="#fff" stroke="#000" stroke-width=".2"/>
<circle cx="150.7" cy="59.9" r=".76" fill="#008000" stroke="#008000" stroke-width=".2"/>
<circle cx="150.7" cy="59.9" r=".51" fill="#fff" stroke="#000" stroke-width=".2"/>
<circle cx="153.3" cy="62.5" r=".76" fill="#008000" stroke="#008000" stroke-width=".2"/>
<circle cx="153.3" cy="62.5" r=".51" fill="#fff" stroke="#000" stroke-width=".2"/>
<circle cx="153.3" cy="59.9" r=".76" fill="#008000" stroke="#008000" stroke-width=".2"/>
<circle cx="153.3" cy="59.9" r=".51" fill="#fff" stroke="#000" stroke-width=".2"/>
<circle cx="155.8" cy="62.5" r=".76" fill="#008000" stroke="#008000" stroke-width=".2"/>
<circle cx="155.8" cy="62.5" r=".51" fill="#fff" stroke="#000" stroke-width=".2"/>
<circle cx="155.8" cy="59.9" r=".76" fill="#008000" stroke="#008000" stroke-width=".2"/>
<circle cx="155.8" cy="59.9" r=".51" fill="#fff" stroke="#000" stroke-width=".2"/>
<circle cx="158.4" cy="62.5" r=".76" fill="#008000" stroke="#008000" stroke-width=".2"/>
<circle cx="158.4" cy="62.5" r=".51" fill="#fff" stroke="#000" stroke-width=".2"/>
<circle cx="158.4" cy="59.9" r=".76" fill="#008000" stroke="#008000" stroke-width=".2"/>
<circle cx="158.4" cy="59.9" r=".51" fill="#fff" stroke="#000" stroke-width=".2"/>
<circle cx="160.9" cy="62.5" r=".76" fill="#008000" stroke="#008000" stroke-width=".2"/>
<circle cx="160.9" cy="62.5" r=".51" fill="#fff" stroke="#000" stroke-width=".2"/>
<circle cx="160.9" cy="59.9" r=".76" fill="#008000" stroke="#008000" stroke-width=".2"/>
<circle cx="160.9" cy="59.9" r=".51" fill="#fff" stroke="#000" stroke-width=".2"/>
<circle cx="163.4" cy="62.5" r=".76" fill="#008000" stroke="#008000" stroke-width=".2"/>
<circle cx="163.4" cy="62.5" r=".51" fill="#fff" stroke="#000" stroke-width=".2"/>
<circle cx="163.4" cy="59.9" r=".76" fill="#008000" stroke="#008000" stroke-width=".2"/>
<circle cx="163.4" cy="59.9" r=".51" fill="#fff" stroke="#000" stroke-width=".2"/>
<circle cx="166" cy="62.5" r=".76" fill="#008000" stroke="#008000" stroke-width=".2"/>
<circle cx="166" cy="62.5" r=".51" fill="#fff" stroke="#000" stroke-width=".2"/>
<circle cx="166" cy="59.9" r=".76" fill="#008000" stroke="#008000" stroke-width=".2"/>
<circle cx="166" cy="59.9" r=".51" fill="#fff" stroke="#000" stroke-width=".2"/>
<circle cx="168.5" cy="62.5" r=".76" fill="#008000" stroke="#008000" stroke-width=".2"/>
<circle cx="168.5" cy="62.5" r=".51" fill="#fff" stroke="#000" stroke-width=".2"/>
<circle cx="168.5" cy="59.9" r=".76" fill="#008000" stroke="#008000" stroke-width=".2"/>
<circle cx="168.5" cy="59.9" r=".51" fill="#fff" stroke="#000" stroke-width=".2"/>
<circle cx="171.1" cy="62.5" r=".76" fill="#008000" stroke="#008000" stroke-width=".2"/>
<circle cx="171.1" cy="62.5" r=".51" fill="#fff" stroke="#000" stroke-width=".2"/>
<circle cx="171.1" cy="59.9" r=".76" fill="#008000" stroke="#008000" stroke-width=".2"/>
<circle cx="171.1" cy="59.9" r=".51" fill="#fff" stroke="#000" stroke-width=".2"/>
<circle cx="173.6" cy="62.5" r=".76" fill="#008000" stroke="#008000" stroke-width=".2"/>
<circle cx="173.6" cy="62.5" r=".51" fill="#fff" stroke="#000" stroke-width=".2"/>
<circle cx="173.6" cy="59.9" r=".76" fill="#008000" stroke="#008000" stroke-width=".2"/>
<circle cx="173.6" cy="59.9" r=".51" fill="#fff" stroke="#000" stroke-width=".2"/>
<circle cx="176.1" cy="62.5" r=".76" fill="#008000" stroke="#008000" stroke-width=".2"/>
<circle cx="176.1" cy="62.5" r=".51" fill="#fff" stroke="#000" stroke-width=".2"/>
<circle cx="176.1" cy="59.9" r=".76" fill="#008000" stroke="#008000" stroke-width=".2"/>
<circle cx="176.1" cy="59.9" r=".51" fill="#fff" stroke="#000" stroke-width=".2"/>
<circle cx="178.7" cy="62.5" r=".76" fill="#008000" stroke="#008000" stroke-width=".2"/>
<circle cx="178.7" cy="62.5" r=".51" fill="#fff" stroke="#000" stroke-width=".2"/>
<circle cx="178.7" cy="59.9" r=".76" fill="#008000" stroke="#008000" stroke-width=".2"/>
<circle cx="178.7" cy="59.9" r=".51" fill="#fff" stroke="#000" stroke-width=".2"/>
<circle cx="181.2" cy="62.5" r=".76" fill="#008000" stroke="#008000" stroke-width=".2"/>
<circle cx="181.2" cy="62.5" r=".51" fill="#fff" stroke="#000" stroke-width=".2"/>
<circle cx="181.2" cy="59.9" r=".76" fill="#008000" stroke="#008000" stroke-width=".2"/>
<circle cx="181.2" cy="59.9" r=".51" fill="#fff" stroke="#000" stroke-width=".2"/>
<circle cx="117.8" cy="67.5" r=".76" fill="#008000" stroke="#008000" stroke-width=".2"/>
<circle cx="117.8" cy="67.5" r=".51" fill="#fff" stroke="#000" stroke-width=".2"/>
<circle cx="117.8" cy="65" r=".76" fill="#008000" stroke="#008000" stroke-width=".2"/>
<circle cx="117.8" cy="65" r=".51" fill="#fff" stroke="#000" stroke-width=".2"/>
<circle cx="120.3" cy="67.5" r=".76" fill="#008000" stroke="#008000" stroke-width=".2"/>
<circle cx="120.3" cy="67.5" r=".51" fill="#fff" stroke="#000" stroke-width=".2"/>
<circle cx="120.3" cy="65" r=".76" fill="#008000" stroke="#008000" stroke-width=".2"/>
<circle cx="120.3" cy="65" r=".51" fill="#fff" stroke="#000" stroke-width=".2"/>
<circle cx="122.8" cy="67.5" r=".76" fill="#008000" stroke="#008000" stroke-width=".2"/>
<circle cx="122.8" cy="67.5" r=".51" fill="#fff" stroke="#000" stroke-width=".2"/>
<circle cx="122.8" cy="65" r=".76" fill="#008000" stroke="#008000" stroke-width=".2"/>
<circle cx="122.8" cy="65" r=".51" fill="#fff" stroke="#000" stroke-width=".2"/>
<circle cx="125.3" cy="67.5" r=".76" fill="#008000" stroke="#008000" stroke-width=".2"/>
<circle cx="125.3" cy="67.5" r=".51" fill="#fff" stroke="#000" stroke-width=".2"/>
<circle cx="125.3" cy="65" r=".76" fill="#008000" stroke="#008000" stroke-width=".2"/>
<circle cx="125.3" cy="65" r=".51" fill="#fff" stroke="#000" stroke-width=".2"/>
<circle cx="127.9" cy="67.5" r=".76" fill="#008000" stroke="#008000" stroke-width=".2"/>
<circle cx="127.9" cy="67.5" r=".51" fill="#fff" stroke="#000" stroke-width=".2"/>
<circle cx="127.9" cy="65" r=".76" fill="#008000" stroke="#008000" stroke-width=".2"/>
<circle cx="127.9" cy="65" r=".51" fill="#fff" stroke="#000" stroke-width=".2"/>
<circle cx="130.4" cy="67.5" r=".76" fill="#008000" stroke="#008000" stroke-width=".2"/>
<circle cx="130.4" cy="67.5" r=".51" fill="#fff" stroke="#000" stroke-width=".2"/>
<circle cx="130.4" cy="65" r=".76" fill="#008000" stroke="#008000" stroke-width=".2"/>
<circle cx="130.4" cy="65" r=".51" fill="#fff" stroke="#000" stroke-width=".2"/>
<circle cx="133" cy="67.5" r=".76" fill="#008000" stroke="#008000" stroke-width=".2"/>
<circle cx="133" cy="67.5" r=".51" fill="#fff" stroke="#000" stroke-width=".2"/>
<circle cx="133" cy="65" r=".76" fill="#008000" stroke="#008000" stroke-width=".2"/>
<circle cx="133" cy="65" r=".51" fill="#fff" stroke="#000" stroke-width=".2"/>
<circle cx="135.5" cy="67.5" r=".76" fill="#008000" stroke="#008000" stroke-width=".2"/>
<circle cx="135.5" cy="67.5" r=".51" fill="#fff" stroke="#000" stroke-width=".2"/>
<circle cx="135.5" cy="65" r=".76" fill="#008000" stroke="#008000" stroke-width=".2"/>
<circle cx="135.5" cy="65" r=".51" fill="#fff" stroke="#000" stroke-width=".2"/>
<circle cx="138" cy="67.5" r=".76" fill="#008000" stroke="#008000" stroke-width=".2"/>
<circle cx="138" cy="67.5" r=".51" fill="#fff" stroke="#000" stroke-width=".2"/>
<circle cx="138" cy="65" r=".76" fill="#008000" stroke="#008000" stroke-width=".2"/>
<circle cx="138" cy="65" r=".51" fill="#fff" stroke="#000" stroke-width=".2"/>
<circle cx="140.6" cy="67.5" r=".76" fill="#008000" stroke="#008000" stroke-width=".2"/>
<circle cx="140.6" cy="67.5" r=".51" fill="#fff" stroke="#000" stroke-width=".2"/>
<circle cx="140.6" cy="65" r=".76" fill="#008000" stroke="#008000" stroke-width=".2"/>
<circle cx="140.6" cy="65" r=".51" fill="#fff" stroke="#000" stroke-width=".2"/>
<circle cx="143.1" cy="67.5" r=".76" fill="#008000" stroke="#008000" stroke-width=".2"/>
<circle cx="143.1" cy="67.5" r=".51" fill="#fff" stroke="#000" stroke-width=".2"/>
<circle cx="143.1" cy="65" r=".76" fill="#008000" stroke="#008000" stroke-width=".2"/>
<circle cx="143.1" cy="65" r=".51" fill="#fff" stroke="#000" stroke-width=".2"/>
<circle cx="145.7" cy="67.5" r=".76" fill="#008000" stroke="#008000" stroke-width=".2"/>
<circle cx="145.7" cy="67.5" r=".51" fill="#fff" stroke="#000" stroke-width=".2"/>
<circle cx="145.7" cy="65" r=".76" fill="#008000" stroke="#008000" stroke-width=".2"/>
<circle cx="145.7" cy="65" r=".51" fill="#fff" stroke="#000" stroke-width=".2"/>
<circle cx="148.2" cy="67.5" r=".76" fill="#008000" stroke="#008000" stroke-width=".2"/>
<circle cx="148.2" cy="67.5" r=".51" fill="#fff" stroke="#000" stroke-width=".2"/>
<circle cx="148.2" cy="65" r=".76" fill="#008000" stroke="#008000" stroke-width=".2"/>
<circle cx="148.2" cy="65" r=".51" fill="#fff" stroke="#000" stroke-width=".2"/>
<circle cx="150.7" cy="67.5" r=".76" fill="#008000" stroke="#008000" stroke-width=".2"/>
<circle cx="150.7" cy="67.5" r=".51" fill="#fff" stroke="#000" stroke-width=".2"/>
<circle cx="150.7" cy="65" r=".76" fill="#008000" stroke="#008000" stroke-width=".2"/>
<circle cx="150.7" cy="65" r=".51" fill="#fff" stroke="#000" stroke-width=".2"/>
<circle cx="153.3" cy="67.5" r=".76" fill="#008000" stroke="#008000" stroke-width=".2"/>
<circle cx="153.3" cy="67.5" r=".51" fill="#fff" stroke="#000" stroke-width=".2"/>
<circle cx="153.3" cy="65" r=".76" fill="#008000" stroke="#008000" stroke-width=".2"/>
<circle cx="153.3" cy="65" r=".51" fill="#fff" stroke="#000" stroke-width=".2"/>
<circle cx="155.8" cy="67.5" r=".76" fill="#008000" stroke="#008000" stroke-width=".2"/>
<circle cx="155.8" cy="67.5" r=".51" fill="#fff" stroke="#000" stroke-width=".2"/>
<circle cx="155.8" cy="65" r=".76" fill="#008000" stroke="#008000" stroke-width=".2"/>
<circle cx="155.8" cy="65" r=".51" fill="#fff" stroke="#000" stroke-width=".2"/>
<circle cx="158.4" cy="67.5" r=".76" fill="#008000" stroke="#008000" stroke-width=".2"/>
<circle cx="158.4" cy="67.5" r=".51" fill="#fff" stroke="#000" stroke-width=".2"/>
<circle cx="158.4" cy="65" r=".76" fill="#008000" stroke="#008000" stroke-width=".2"/>
<circle cx="158.4" cy="65" r=".51" fill="#fff" stroke="#000" stroke-width=".2"/>
<circle cx="160.9" cy="67.5" r=".76" fill="#008000" stroke="#008000" stroke-width=".2"/>
<circle cx="160.9" cy="67.5" r=".51" fill="#fff" stroke="#000" stroke-width=".2"/>
<circle cx="160.9" cy="65" r=".76" fill="#008000" stroke="#008000" stroke-width=".2"/>
<circle cx="160.9" cy="65" r=".51" fill="#fff" stroke="#000" stroke-width=".2"/>
<circle cx="163.4" cy="67.5" r=".76" fill="#008000" stroke="#008000" stroke-width=".2"/>
<circle cx="163.4" cy="67.5" r=".51" fill="#fff" stroke="#000" stroke-width=".2"/>
<circle cx="163.4" cy="65" r=".76" fill="#008000" stroke="#008000" stroke-width=".2"/>
<circle cx="163.4" cy="65" r=".51" fill="#fff" stroke="#000" stroke-width=".2"/>
<circle cx="166" cy="67.5" r=".76" fill="#008000" stroke="#008000" stroke-width=".2"/>
<circle cx="166" cy="67.5" r=".51" fill="#fff" stroke="#000" stroke-width=".2"/>
<circle cx="166" cy="65" r=".76" fill="#008000" stroke="#008000" stroke-width=".2"/>
<circle cx="166" cy="65" r=".51" fill="#fff" stroke="#000" stroke-width=".2"/>
<circle cx="168.5" cy="67.5" r=".76" fill="#008000" stroke="#008000" stroke-width=".2"/>
<circle cx="168.5" cy="67.5" r=".51" fill="#fff" stroke="#000" stroke-width=".2"/>
<circle cx="168.5" cy="65" r=".76" fill="#008000" stroke="#008000" stroke-width=".2"/>
<circle cx="168.5" cy="65" r=".51" fill="#fff" stroke="#000" stroke-width=".2"/>
<circle cx="171.1" cy="67.5" r=".76" fill="#008000" stroke="#008000" stroke-width=".2"/>
<circle cx="171.1" cy="67.5" r=".51" fill="#fff" stroke="#000" stroke-width=".2"/>
<circle cx="171.1" cy="65" r=".76" fill="#008000" stroke="#008000" stroke-width=".2"/>
<circle cx="171.1" cy="65" r=".51" fill="#fff" stroke="#000" stroke-width=".2"/>
<circle cx="173.6" cy="67.5" r=".76" fill="#008000" stroke="#008000" stroke-width=".2"/>
<circle cx="173.6" cy="67.5" r=".51" fill="#fff" stroke="#000" stroke-width=".2"/>
<circle cx="173.6" cy="65" r=".76" fill="#008000" stroke="#008000" stroke-width=".2"/>
<circle cx="173.6" cy="65" r=".51" fill="#fff" stroke="#000" stroke-width=".2"/>
<circle cx="176.1" cy="67.5" r=".76" fill="#008000" stroke="#008000" stroke-width=".2"/>
<circle cx="176.1" cy="67.5" r=".51" fill="#fff" stroke="#000" stroke-width=".2"/>
<circle cx="176.1" cy="65" r=".76" fill="#008000" stroke="#008000" stroke-width=".2"/>
<circle cx="176.1" cy="65" r=".51" fill="#fff" stroke="#000" stroke-width=".2"/>
<circle cx="178.7" cy="67.5" r=".76" fill="#008000" stroke="#008000" stroke-width=".2"/>
<circle cx="178.7" cy="67.5" r=".51" fill="#fff" stroke="#000" stroke-width=".2"/>
<circle cx="178.7" cy="65" r=".76" fill="#008000" stroke="#008000" stroke-width=".2"/>
<circle cx="178.7" cy="65" r=".51" fill="#fff" stroke="#000" stroke-width=".2"/>
<circle cx="181.2" cy="67.5" r=".76" fill="#008000" stroke="#008000" stroke-width=".2"/>
<circle cx="181.2" cy="67.5" r=".51" fill="#fff" stroke="#000" stroke-width=".2"/>
<circle cx="181.2" cy="65" r=".76" fill="#008000" stroke="#008000" stroke-width=".2"/>
<circle cx="181.2" cy="65" r=".51" fill="#fff" stroke="#000" stroke-width=".2"/>
<circle cx="186.4" cy="100.8" r=".51" fill="#008000" stroke="#008000" stroke-width=".2"/>
<circle cx="186.4" cy="100.8" r=".25" fill="#fff" stroke="#000" stroke-width=".2"/>
<circle cx="188.4" cy="100.8" r=".51" fill="#008000" stroke="#008000" stroke-width=".2"/>
<circle cx="188.4" cy="100.8" r=".25" fill="#fff" stroke="#000" stroke-width=".2"/>
<circle cx="186.4" cy="98.8" r=".51" fill="#008000" stroke="#008000" stroke-width=".2"/>
<circle cx="186.4" cy="98.8" r=".25" fill="#fff" stroke="#000" stroke-width=".2"/>
<circle cx="188.4" cy="98.8" r=".51" fill="#008000" stroke="#008000" stroke-width=".2"/>
<circle cx="188.4" cy="98.8" r=".25" fill="#fff" stroke="#000" stroke-width=".2"/>
<circle cx="186.4" cy="96.9" r=".51" fill="#008000" stroke="#008000" stroke-width=".2"/>
<circle cx="186.4" cy="96.9" r=".25" fill="#fff" stroke="#000" stroke-width=".2"/>
<circle cx="188.4" cy="96.9" r=".51" fill="#008000" stroke="#008000" stroke-width=".2"/>
<circle cx="188.4" cy="96.9" r=".25" fill="#fff" stroke="#000" stroke-width=".2"/>
<circle cx="186.4" cy="94.8" r=".51" fill="#008000" stroke="#008000" stroke-width=".2"/>
<circle cx="186.4" cy="94.8" r=".25" fill="#fff" stroke="#000" stroke-width=".2"/>
<circle cx="188.4" cy="94.8" r=".51" fill="#008000" stroke="#008000" stroke-width=".2"/>
<circle cx="188.4" cy="94.8" r=".25" fill="#fff" stroke="#000" stroke-width=".2"/>
<circle cx="186.4" cy="92.9" r=".51" fill="#008000" stroke="#008000" stroke-width=".2"/>
<circle cx="186.4" cy="92.9" r=".25" fill="#fff" stroke="#000" stroke-width=".2"/>
<circle cx="188.4" cy="92.9" r=".51" fill="#008000" stroke="#008000" stroke-width=".2"/>
<circle cx="188.4" cy="92.9" r=".25" fill="#fff" stroke="#000" stroke-width=".2"/>
<circle cx="186.4" cy="90.8" r=".51" fill="#008000" stroke="#008000" stroke-width=".2"/>
<circle cx="186.4" cy="90.8" r=".25" fill="#fff" stroke="#000" stroke-width=".2"/>
<circle cx="188.4" cy="90.8" r=".51" fill="#008000" stroke="#008000" stroke-width=".2"/>
<circle cx="188.4" cy="90.8" r=".25" fill="#fff" stroke="#000" stroke-width=".2"/>
<circle cx="186.4" cy="88.9" r=".51" fill="#008000" stroke="#008000" stroke-width=".2"/>
<circle cx="186.4" cy="88.9" r=".25" fill="#fff" stroke="#000" stroke-width=".2"/>
<circle cx="188.4" cy="88.9" r=".51" fill="#008000" stroke="#008000" stroke-width=".2"/>
<circle cx="188.4" cy="88.9" r=".25" fill="#fff" stroke="#000" stroke-width=".2"/>
<circle cx="186.4" cy="86.8" r=".51" fill="#008000" stroke="#008000" stroke-width=".2"/>
<circle cx="186.4" cy="86.8" r=".25" fill="#fff" stroke="#000" stroke-width=".2"/>
<circle cx="188.4" cy="86.8" r=".51" fill="#008000" stroke="#008000" stroke-width=".2"/>
<circle cx="188.4" cy="86.8" r=".25" fill="#fff" stroke="#000" stroke-width=".2"/>
<circle cx="186.4" cy="119.1" r=".51" fill="#008000" stroke="#008000" stroke-width=".2"/>
<circle cx="186.4" cy="119.1" r=".25" fill="#fff" stroke="#000" stroke-width=".2"/>
<circle cx="188.3" cy="119.1" r=".51" fill="#008000" stroke="#008000" stroke-width=".2"/>
<circle cx="188.3" cy="119.1" r=".25" fill="#fff" stroke="#000" stroke-width=".2"/>
<circle cx="186.4" cy="117.1" r=".51" fill="#008000" stroke="#008000" stroke-width=".2"/>
<circle cx="186.4" cy="117.1" r=".25" fill="#fff" stroke="#000" stroke-width=".2"/>
<circle cx="188.3" cy="117.1" r=".51" fill="#008000" stroke="#008000" stroke-width=".2"/>
<circle cx="188.3" cy="117.1" r=".25" fill="#fff" stroke="#000" stroke-width=".2"/>
<circle cx="186.4" cy="115.1" r=".51" fill="#008000" stroke="#008000" stroke-width=".2"/>
<circle cx="186.4" cy="115.1" r=".25" fill="#fff" stroke="#000" stroke-width=".2"/>
<circle cx="188.3" cy="115.1" r=".51" fill="#008000" stroke="#008000" stroke-width=".2"/>
<circle cx="188.3" cy="115.1" r=".25" fill="#fff" stroke="#000" stroke-width=".2"/>
<circle cx="186.4" cy="113.1" r=".51" fill="#008000" stroke="#008000" stroke-width=".2"/>
<circle cx="186.4" cy="113.1" r=".25" fill="#fff" stroke="#000" stroke-width=".2"/>
<circle cx="188.3" cy="113.1" r=".51" fill="#008000" stroke="#008000" stroke-width=".2"/>
<circle cx="188.3" cy="113.1" r=".25" fill="#fff" stroke="#000" stroke-width=".2"/>
<circle cx="186.4" cy="111.1" r=".51" fill="#008000" stroke="#008000" stroke-width=".2"/>
<circle cx="186.4" cy="111.1" r=".25" fill="#fff" stroke="#000" stroke-width=".2"/>
<circle cx="188.3" cy="111.1" r=".51" fill="#008000" stroke="#008000" stroke-width=".2"/>
<circle cx="188.3" cy="111.1" r=".25" fill="#fff" stroke="#000" stroke-width=".2"/>
<circle cx="186.4" cy="109.1" r=".51" fill="#008000" stroke="#008000" stroke-width=".2"/>
<circle cx="186.4" cy="109.1" r=".25" fill="#fff" stroke="#000" stroke-width=".2"/>
<circle cx="188.3" cy="109.1" r=".51" fill="#008000" stroke="#008000" stroke-width=".2"/>
<circle cx="188.3" cy="109.1" r=".25" fill="#fff" stroke="#000" stroke-width=".2"/>
<circle cx="186.4" cy="107.1" r=".51" fill="#008000" stroke="#008000" stroke-width=".2"/>
<circle cx="186.4" cy="107.1" r=".25" fill="#fff" stroke="#000" stroke-width=".2"/>
<circle cx="188.3" cy="107.1" r=".51" fill="#008000" stroke="#008000" stroke-width=".2"/>
<circle cx="188.3" cy="107.1" r=".25" fill="#fff" stroke="#000" stroke-width=".2"/>
<circle cx="186.4" cy="105.1" r=".51" fill="#008000" stroke="#008000" stroke-width=".2"/>
<circle cx="186.4" cy="105.1" r=".25" fill="#fff" stroke="#000" stroke-width=".2"/>
<circle cx="188.3" cy="105.1" r=".51" fill="#008000" stroke="#008000" stroke-width=".2"/>
<circle cx="188.3" cy="105.1" r=".25" fill="#fff" stroke="#000" stroke-width=".2"/>
<path d="M144.8 111.1h1.3" fill="none" stroke="#008000" stroke-width="1.3"/>
<circle cx="145.4" cy="111.1" r=".4" fill="#fff" stroke="#000" stroke-width=".2"/>
<path d="M144.8 113.6h1.3" fill="none" stroke="#008000" stroke-width="1.3"/>
<circle cx="145.4" cy="113.6" r=".4" fill="#fff" stroke="#000" stroke-width=".2"/>
<circle cx="127.7" cy="86.8" r=".51" fill="#008000" stroke="#008000" stroke-width=".2"/>
<circle cx="127.7" cy="86.8" r=".3" fill="#fff" stroke="#000" stroke-width=".2"/>
<circle cx="132" cy="87" r=".51" fill="#008000" stroke="#008000" stroke-width=".2"/>
<circle cx="132" cy="87" r=".3" fill="#fff" stroke="#000" stroke-width=".2"/>
<circle cx="166.4" cy="90.2" r=".51" fill="#008000" stroke="#008000" stroke-width=".2"/>
<circle cx="166.4" cy="90.2" r=".3" fill="#fff" stroke="#000" stroke-width=".2"/>
<circle cx="179.8" cy="103.3" r=".51" fill="#008000" stroke="#008000" stroke-width=".2"/>
<circle cx="179.8" cy="103.3" r=".3" fill="#fff" stroke="#000" stroke-width=".2"/>
<circle cx="132.4" cy="75.3" r=".51" fill="#008000" stroke="#008000" stroke-width=".2"/>
<circle cx="132.4" cy="75.3" r=".3" fill="#fff" stroke="#000" stroke-width=".2"/>
<circle cx="151.4" cy="75.4" r=".51" fill="#008000" stroke="#008000" stroke-width=".2"/>
<circle cx="151.4" cy="75.4" r=".3" fill="#fff" stroke="#000" stroke-width=".2"/>
<circle cx="164.8" cy="103.4" r=".51" fill="#008000" stroke="#008000" stroke-width=".2"/>
<circle cx="164.8" cy="103.4" r=".3" fill="#fff" stroke="#000" stroke-width=".2"/>
<circle cx="164.9" cy="109.5" r=".51" fill="#008000" stroke="#008000" stroke-width=".2"/>
<circle cx="164.9" cy="109.5" r=".3" fill="#fff" stroke="#000" stroke-width=".2"/>
<circle cx="132.3" cy="73.9" r=".51" fill="#008000" stroke="#008000" stroke-width=".2"/>
<circle cx="132.3" cy="73.9" r=".3" fill="#fff" stroke="#000" stroke-width=".2"/>
<circle cx="149.4" cy="74.3" r=".51" fill="#008000" stroke="#008000" stroke-width=".2"/>
<circle cx="149.4" cy="74.3" r=".3" fill="#fff" stroke="#000" stroke-width=".2"/>
<circle cx="165.4" cy="101.2" r=".51" fill="#008000" stroke="#008000" stroke-width=".2"/>
<circle cx="165.4" cy="101.2" r=".3" fill="#fff" stroke="#000" stroke-width=".2"/>
<circle cx="167.1" cy="109.1" r=".51" fill="#008000" stroke="#008000" stroke-width=".2"/>
<circle cx="167.1" cy="109.1" r=".3" fill="#fff" stroke="#000" stroke-width=".2"/>
<circle cx="167.1" cy="114.1" r=".51" fill="#008000" stroke="#008000" stroke-width=".2"/>
<circle cx="167.1" cy="114.1" r=".3" fill="#fff" stroke="#000" stroke-width=".2"/>
<circle cx="166.8" cy="79.9" r=".51" fill="#008000" stroke="#008000" stroke-width=".2"/>
<circle cx="166.8" cy="79.9" r=".3" fill="#fff" stroke="#000" stroke-width=".2"/>
<circle cx="169.1" cy="79.8" r=".51" fill="#008000" stroke="#008000" stroke-width=".2"/>
<circle cx="169.1" cy="79.8" r=".3" fill="#fff" stroke="#000" stroke-width=".2"/>
<circle cx="167.4" cy="100.2" r=".44" fill="#008000" stroke="#008000" stroke-width=".2"/>
<circle cx="167.4" cy="100.2" r=".25" fill="#fff" stroke="#000" stroke-width=".2"/>
<circle cx="186.5" cy="65.5" r=".44" fill="#008000" stroke="#008000" stroke-width=".2"/>
<circle cx="186.5" cy="65.5" r=".25" fill="#fff" stroke="#000" stroke-width=".2"/>
<circle cx="124.1" cy="114.3" r=".51" fill="#008000" stroke="#008000" stroke-width=".2"/>
<circle cx="124.1" cy="114.3" r=".3" fill="#fff" stroke="#000" stroke-width=".2"/>
<circle cx="132.5" cy="80.4" r=".51" fill="#008000" stroke="#008000" stroke-width=".2"/>
<circle cx="132.5" cy="80.4" r=".3" fill="#fff" stroke="#000" stroke-width=".2"/>
<circle cx="149.8" cy="80.4" r=".51" fill="#008000" stroke="#008000" stroke-width=".2"/>
<circle cx="149.8" cy="80.4" r=".3" fill="#fff" stroke="#000" stroke-width=".2"/>
<circle cx="157.7" cy="103.7" r=".51" fill="#008000" stroke="#008000" stroke-width=".2"/>
<circle cx="157.7" cy="103.7" r=".3" fill="#fff" stroke="#000" stroke-width=".2"/>
<circle cx="157.8" cy="114.1" r=".44" fill="#008000" stroke="#008000" stroke-width=".2"/>
<circle cx="157.8" cy="114.1" r=".25" fill="#fff" stroke="#000" stroke-width=".2"/>
<circle cx="157.8" cy="108.6" r=".44" fill="#008000" stroke="#008000" stroke-width=".2"/>
<circle cx="157.8" cy="108.6" r=".25" fill="#fff" stroke="#000" stroke-width=".2"/>
<circle cx="131.6" cy="76.6" r=".51" fill="#008000" stroke="#008000" stroke-width=".2"/>
<circle cx="131.6" cy="76.6" r=".3" fill="#fff" stroke="#000" stroke-width=".2"/>
<circle cx="150.6" cy="76.5" r=".51" fill="#008000" stroke="#008000" stroke-width=".2"/>
<circle cx="150.6" cy="76.5" r=".3" fill="#fff" stroke="#000" stroke-width=".2"/>
<circle cx="163.4" cy="103.7" r=".51" fill="#008000" stroke="#008000" stroke-width=".2"/>
<circle cx="163.4" cy="103.7" r=".3" fill="#fff" stroke="#000" stroke-width=".2"/>
<circle cx="163.3" cy="109.2" r=".51" fill="#008000" stroke="#008000" stroke-width=".2"/>
<circle cx="163.3" cy="109.2" r=".3" fill="#fff" stroke="#000" stroke-width=".2"/>
<circle cx="132.5" cy="77.8" r=".51" fill="#008000" stroke="#008000" stroke-width=".2"/>
<circle cx="132.5" cy="77.8" r=".3" fill="#fff" stroke="#000" stroke-width=".2"/>
<circle cx="149.8" cy="78" r=".51" fill="#008000" stroke="#008000" stroke-width=".2"/>
<circle cx="149.8" cy="78" r=".3" fill="#fff" stroke="#000" stroke-width=".2"/>
<circle cx="161.5" cy="103.8" r=".51" fill="#008000" stroke="#008000" stroke-width=".2"/>
<circle cx="161.5" cy="103.8" r=".3" fill="#fff" stroke="#000" stroke-width=".2"/>
<circle cx="161.6" cy="109.2" r=".51" fill="#008000" stroke="#008000" stroke-width=".2"/>
<circle cx="161.6" cy="109.2" r=".3" fill="#fff" stroke="#000" stroke-width=".2"/>
<circle cx="132" cy="85.6" r=".51" fill="#008000" stroke="#008000" stroke-width=".2"/>
<circle cx="132" cy="85.6" r=".3" fill="#fff" stroke="#000" stroke-width=".2"/>
<circle cx="151.7" cy="85.4" r=".51" fill="#008000" stroke="#008000" stroke-width=".2"/>
<circle cx="151.7" cy="85.4" r=".3" fill="#fff" stroke="#000" stroke-width=".2"/>
<circle cx="152.7" cy="103.5" r=".51" fill="#008000" stroke="#008000" stroke-width=".2"/>
<circle cx="152.7" cy="103.5" r=".3" fill="#fff" stroke="#000" stroke-width=".2"/>
<circle cx="152.7" cy="111.8" r=".51" fill="#008000" stroke="#008000" stroke-width=".2"/>
<circle cx="152.7" cy="111.8" r=".3" fill="#fff" stroke="#000" stroke-width=".2"/>
<circle cx="134.2" cy="89.4" r=".51" fill="#008000" stroke="#008000" stroke-width=".2"/>
<circle cx="134.2" cy="89.4" r=".3" fill="#fff" stroke="#000" stroke-width=".2"/>
<circle cx="150.5" cy="90.5" r=".51" fill="#008000" stroke="#008000" stroke-width=".2"/>
<circle cx="150.5" cy="90.5" r=".3" fill="#fff" stroke="#000" stroke-width=".2"/>
<circle cx="150.4" cy="103.6" r=".51" fill="#008000" stroke="#008000" stroke-width=".2"/>
<circle cx="150.4" cy="103.6" r=".3" fill="#fff" stroke="#000" stroke-width=".2"/>
<circle cx="126" cy="96.8" r=".51" fill="#008000" stroke="#008000" stroke-width=".2"/>
<circle cx="126" cy="96.8" r=".3" fill="#fff" stroke="#000" stroke-width=".2"/>
<circle cx="132.3" cy="92" r=".51" fill="#008000" stroke="#008000" stroke-width=".2"/>
<circle cx="132.3" cy="92" r=".3" fill="#fff" stroke="#000" stroke-width=".2"/>
<circle cx="173.5" cy="89.8" r=".51" fill="#008000" stroke="#008000" stroke-width=".2"/>
<circle cx="173.5" cy="89.8" r=".3" fill="#fff" stroke="#000" stroke-width=".2"/>
<circle cx="189.7" cy="72.9" r=".51" fill="#008000" stroke="#008000" stroke-width=".2"/>
<circle cx="189.7" cy="72.9" r=".3" fill="#fff" stroke="#000" stroke-width=".2"/>
<circle cx="189.7" cy="81.1" r=".51" fill="#008000" stroke="#008000" stroke-width=".2"/>
<circle cx="189.7" cy="81.1" r=".3" fill="#fff" stroke="#000" stroke-width=".2"/>
<circle cx="173" cy="80.8" r=".51" fill="#008000" stroke="#008000" stroke-width=".2"/>
<circle cx="173" cy="80.8" r=".3" fill="#fff" stroke="#000" stroke-width=".2"/>
<circle cx="173.1" cy="83.2" r=".51" fill="#008000" stroke="#008000" stroke-width=".2"/>
<circle cx="173.1" cy="83.2" r=".3" fill="#fff" stroke="#000" stroke-width=".2"/>
<circle cx="173.9" cy="87.2" r=".51" fill="#008000" stroke="#008000" stroke-width=".2"/>
<circle cx="173.9" cy="87.2" r=".3" fill="#fff" stroke="#000" stroke-width=".2"/>
<circle cx="182.1" cy="78.5" r=".51" fill="#008000" stroke="#008000" stroke-width=".2"/>
<circle cx="182.1" cy="78.5" r=".3" fill="#fff" stroke="#000" stroke-width=".2"/>
<circle cx="192.1" cy="79.3" r=".51" fill="#008000" stroke="#008000" stroke-width=".2"/>
<circle cx="192.1" cy="79.3" r=".3" fill="#fff" stroke="#000" stroke-width=".2"/>
<circle cx="136" cy="70.5" r=".34" fill="#008000" stroke="#008000" stroke-width=".2"/>
<circle cx="136" cy="70.5" r=".13" fill="#fff" stroke="#000" stroke-width=".2"/>
<circle cx="127.9" cy="106.1" r=".51" fill="#008000" stroke="#008000" stroke-width=".2"/>
<circle cx="127.9" cy="106.1" r=".3" fill="#fff" stroke="#000" stroke-width=".2"/>
<circle cx="139.4" cy="70.1" r=".44" fill="#008000" stroke="#008000" stroke-width=".2"/>
<circle cx="139.4" cy="70.1" r=".25" fill="#fff" stroke="#000" stroke-width=".2"/>
<circle cx="128" cy="101.8" r=".51" fill="#008000" stroke="#008000" stroke-width=".2"/>
<circle cx="128" cy="101.8" r=".3" fill="#fff" stroke="#000" stroke-width=".2"/>
<circle cx="132.2" cy="99.3" r=".51" fill="#008000" stroke="#008000" stroke-width=".2"/>
<circle cx="132.2" cy="99.3" r=".3" fill="#fff" stroke="#000" stroke-width=".2"/>
<circle cx="139.3" cy="99.2" r=".51" fill="#008000" stroke="#008000" stroke-width=".2"/>
<circle cx="139.3" cy="99.2" r=".3" fill="#fff" stroke="#000" stroke-width=".2"/>
<circle cx="139.3" cy="106.5" r=".51" fill="#008000" stroke="#008000" stroke-width=".2"/>
<circle cx="139.3" cy="106.5" r=".3" fill="#fff" stroke="#000" stroke-width=".2"/>
<circle cx="119.1" cy="102.9" r=".51" fill="#008000" stroke="#008000" stroke-width=".2"/>
<circle cx="119.1" cy="102.9" r=".3" fill="#fff" stroke="#000" stroke-width=".2"/>
<circle cx="132.1" cy="97.2" r=".51" fill="#008000" stroke="#008000" stroke-width=".2"/>
<circle cx="132.1" cy="97.2" r=".3" fill="#fff" stroke="#000" stroke-width=".2"/>
<circle cx="136.9" cy="97.4" r=".51" fill="#008000" stroke="#008000" stroke-width=".2"/>
<circle cx="136.9" cy="97.4" r=".3" fill="#fff" stroke="#000" stroke-width=".2"/>
<circle cx="136.9" cy="102.9" r=".51" fill="#008000" stroke="#008000" stroke-width=".2"/>
<circle cx="136.9" cy="102.9" r=".3" fill="#fff" stroke="#000" stroke-width=".2"/>
<circle cx="114.9" cy="102.8" r=".51" fill="#008000" stroke="#008000" stroke-width=".2"/>
<circle cx="114.9" cy="102.8" r=".3" fill="#fff" stroke="#000" stroke-width=".2"/>
<circle cx="131.5" cy="103.9" r=".51" fill="#008000" stroke="#008000" stroke-width=".2"/>
<circle cx="131.5" cy="103.9" r=".3" fill="#fff" stroke="#000" stroke-width=".2"/>
<circle cx="132.1" cy="84.3" r=".51" fill="#008000" stroke="#008000" stroke-width=".2"/>
<circle cx="132.1" cy="84.3" r=".3" fill="#fff" stroke="#000" stroke-width=".2"/>
<circle cx="166.1" cy="84.3" r=".51" fill="#008000" stroke="#008000" stroke-width=".2"/>
<circle cx="166.1" cy="84.3" r=".3" fill="#fff" stroke="#000" stroke-width=".2"/>
<circle cx="169.7" cy="84.3" r=".51" fill="#008000" stroke="#008000" stroke-width=".2"/>
<circle cx="169.7" cy="84.3" r=".3" fill="#fff" stroke="#000" stroke-width=".2"/>
<circle cx="131.8" cy="81.7" r=".51" fill="#008000" stroke="#008000" stroke-width=".2"/>
<circle cx="131.8" cy="81.7" r=".3" fill="#fff" stroke="#000" stroke-width=".2"/>
<circle cx="166.3" cy="81.6" r=".51" fill="#008000" stroke="#008000" stroke-width=".2"/>
<circle cx="166.3" cy="81.6" r=".3" fill="#fff" stroke="#000" stroke-width=".2"/>
<circle cx="179.4" cy="81.7" r=".51" fill="#008000" stroke="#008000" stroke-width=".2"/>
<circle cx="179.4" cy="81.7" r=".3" fill="#fff" stroke="#000" stroke-width=".2"/>
<circle cx="186.3" cy="82.5" r=".51" fill="#008000" stroke="#008000" stroke-width=".2"/>
<circle cx="186.3" cy="82.5" r=".3" fill="#fff" stroke="#000" stroke-width=".2"/>
<circle cx="183.8" cy="101" r=".51" fill="#008000" stroke="#008000" stroke-width=".2"/>
<circle cx="183.8" cy="101" r=".3" fill="#fff" stroke="#000" stroke-width=".2"/>
<circle cx="179.8" cy="96.4" r=".51" fill="#008000" stroke="#008000" stroke-width=".2"/>
<circle cx="179.8" cy="96.4" r=".3" fill="#fff" stroke="#000" stroke-width=".2"/>
<circle cx="179.1" cy="92.9" r=".51" fill="#008000" stroke="#008000" stroke-width=".2"/>
<circle cx="179.1" cy="92.9" r=".3" fill="#fff" stroke="#000" stroke-width=".2"/>
<circle cx="178.7" cy="88" r=".51" fill="#008000" stroke="#008000" stroke-width=".2"/>
<circle cx="178.7" cy="88" r=".3" fill="#fff" stroke="#000" stroke-width=".2"/>
<circle cx="175.6" cy="85.8" r=".51" fill="#008000" stroke="#008000" stroke-width=".2"/>
<circle cx="175.6" cy="85.8" r=".3" fill="#fff" stroke="#000" stroke-width=".2"/>
<circle cx="175.7" cy="83" r=".51" fill="#008000" stroke="#008000" stroke-width=".2"/>
<circle cx="175.7" cy="83" r=".3" fill="#fff" stroke="#000" stroke-width=".2"/>
<circle cx="175.6" cy="80.8" r=".51" fill="#008000" stroke="#008000" stroke-width=".2"/>
<circle cx="175.6" cy="80.8" r=".3" fill="#fff" stroke="#000" stroke-width=".2"/>
<circle cx="167" cy="76.2" r=".51" fill="#008000" stroke="#008000" stroke-width=".2"/>
<circle cx="167" cy="76.2" r=".3" fill="#fff" stroke="#000" stroke-width=".2"/>
<circle cx="161.9" cy="73.2" r=".51" fill="#008000" stroke="#008000" stroke-width=".2"/>
<circle cx="161.9" cy="73.2" r=".3" fill="#fff" stroke="#000" stroke-width=".2"/>
<circle cx="132.9" cy="83" r=".59" fill="#008000" stroke="#008000" stroke-width=".2"/>
<circle cx="132.9" cy="83" r=".4" fill="#fff" stroke="#000" stroke-width=".2"/>
<circle cx="153.1" cy="83" r=".59" fill="#008000" stroke="#008000" stroke-width=".2"/>
<circle cx="153.1" cy="83" r=".4" fill="#fff" stroke="#000" stroke-width=".2"/>
<circle cx="156.2" cy="98.9" r=".59" fill="#008000" stroke="#008000" stroke-width=".2"/>
<circle cx="156.2" cy="98.9" r=".4" fill="#fff" stroke="#000" stroke-width=".2"/>
<circle cx="175.5" cy="99" r=".59" fill="#008000" stroke="#008000" stroke-width=".2"/>
<circle cx="175.5" cy="99" r=".4" fill="#fff" stroke="#000" stroke-width=".2"/>
<circle cx="178.8" cy="99.3" r=".59" fill="#008000" stroke="#008000" stroke-width=".2"/>
<circle cx="178.8" cy="99.3" r=".4" fill="#fff" stroke="#000" stroke-width=".2"/>
<circle cx="119.1" cy="73.3" r=".59" fill="#008000" stroke="#008000" stroke-width=".2"/>
<circle cx="119.1" cy="73.3" r=".4" fill="#fff" stroke="#000" stroke-width=".2"/>
<circle cx="128.5" cy="94" r=".51" fill="#008000" stroke="#008000" stroke-width=".2"/>
<circle cx="128.5" cy="94" r=".3" fill="#fff" stroke="#000" stroke-width=".2"/>
<circle cx="132.3" cy="94" r=".51" fill="#008000" stroke="#008000" stroke-width=".2"/>
<circle cx="132.3" cy="94" r=".3" fill="#fff" stroke="#000" stroke-width=".2"/>
<circle cx="143" cy="94.1" r=".51" fill="#008000" stroke="#008000" stroke-width=".2"/>
<circle cx="143" cy="94.1" r=".3" fill="#fff" stroke="#000" stroke-width=".2"/>
<circle cx="128.5" cy="95.5" r=".51" fill="#008000" stroke="#008000" stroke-width=".2"/>
<circle cx="128.5" cy="95.5" r=".3" fill="#fff" stroke="#000" stroke-width=".2"/>
<circle cx="132.2" cy="95.5" r=".51" fill="#008000" stroke="#008000" stroke-width=".2"/>
<circle cx="132.2" cy="95.5" r=".3" fill="#fff" stroke="#000" stroke-width=".2"/>
<circle cx="148.2" cy="94.9" r=".51" fill="#008000" stroke="#008000" stroke-width=".2"/>
<circle cx="148.2" cy="94.9" r=".3" fill="#fff" stroke="#000" stroke-width=".2"/>
<circle cx="131.9" cy="79.1" r=".51" fill="#008000" stroke="#008000" stroke-width=".2"/>
<circle cx="131.9" cy="79.1" r=".3" fill="#fff" stroke="#000" stroke-width=".2"/>
<circle cx="150.9" cy="79.2" r=".51" fill="#008000" stroke="#008000" stroke-width=".2"/>
<circle cx="150.9" cy="79.2" r=".3" fill="#fff" stroke="#000" stroke-width=".2"/>
<circle cx="159.8" cy="103.7" r=".51" fill="#008000" stroke="#008000" stroke-width=".2"/>
<circle cx="159.8" cy="103.7" r=".3" fill="#fff" stroke="#000" stroke-width=".2"/>
<circle cx="156.1" cy="110.7" r=".44" fill="#008000" stroke="#008000" stroke-width=".2"/>
<circle cx="156.1" cy="110.7" r=".25" fill="#fff" stroke="#000" stroke-width=".2"/>
<circle cx="112.4" cy="60.1" r="2.16" fill="#008000" stroke="#008000" stroke-width=".2"/>
<circle cx="112.4" cy="60.1" r="1.65" fill="#fff" stroke="#000" stroke-width=".2"/>
<circle cx="186" cy="60.1" r="2.16" fill="#008000" stroke="#008000" stroke-width=".2"/>
<circle cx="186" cy="60.1" r="1.65" fill="#fff" stroke="#000" stroke-width=".2"/>
<circle cx="188.6" cy="145.8" r="2.16" fill="#008000" stroke="#008000" stroke-width=".2"/>
<circle cx="188.6" cy="145.8" r="1.65" fill="#fff" stroke="#000" stroke-width=".2"/>
<circle cx="108.6" cy="145.8" r="2.16" fill="#008000" stroke="#008000" stroke-width=".2"/>
<circle cx="108.6" cy="145.8" r="1.65" fill="#fff" stroke="#000" stroke-width=".2"/>
<circle cx="168.1" cy="97.2" r=".51" fill="#008000" stroke="#008000" stroke-width=".2"/>
<circle cx="168.1" cy="97.2" r=".3" fill="#fff" stroke="#000" stroke-width=".2"/>
<circle cx="146.9" cy="97.2" r=".51" fill="#008000" stroke="#008000" stroke-width=".2"/>
<circle cx="146.9" cy="97.2" r=".3" fill="#fff" stroke="#000" stroke-width=".2"/>
<circle cx="165" cy="73" r=".51" fill="#008000" stroke="#008000" stroke-width=".2"/>
<circle cx="165" cy="73" r=".3" fill="#fff" stroke="#000" stroke-width=".2"/>
<circle cx="167" cy="73" r=".51" fill="#008000" stroke="#008000" stroke-width=".2"/>
<circle cx="167" cy="73" r=".3" fill="#fff" stroke="#000" stroke-width=".2"/>
<path d="M170.9 72.5h1v1.1h-1z" fill="#008000" stroke="#008000" stroke-width=".2"/>
<circle cx="171.4" cy="73" r=".3" fill="#fff" stroke="#000" stroke-width=".2"/>
<path d="M184.4 76.4h1.1v1h-1.1z" fill="#008000" stroke="#008000" stroke-width=".2"/>
<circle cx="185" cy="76.9" r=".3" fill="#fff" stroke="#000" stroke-width=".2"/>
<circle cx="187.4" cy="89.9" r=".51" fill="#008000" stroke="#008000" stroke-width=".2"/>
<circle cx="187.4" cy="89.9" r=".3" fill="#fff" stroke="#000" stroke-width=".2"/>
<circle cx="164.9" cy="71.2" r=".51" fill="#008000" stroke="#008000" stroke-width=".2"/>
<circle cx="164.9" cy="71.2" r=".3" fill="#fff" stroke="#000" stroke-width=".2"/>
<circle cx="167" cy="71.2" r=".51" fill="#008000" stroke="#008000" stroke-width=".2"/>
<circle cx="167" cy="71.2" r=".3" fill="#fff" stroke="#000" stroke-width=".2"/>
<path d="M174.2 70.8h1.1v1h-1.1z" fill="#008000" stroke="#008000" stroke-width=".2"/>
<circle cx="174.8" cy="71.3" r=".3" fill="#fff" stroke="#000" stroke-width=".2"/>
<circle cx="187.7" cy="75.3" r=".44" fill="#008000" stroke="#008000" stroke-width=".2"/>
<circle cx="187.7" cy="75.3" r=".25" fill="#fff" stroke="#000" stroke-width=".2"/>
<circle cx="189.6" cy="90" r=".44" fill="#008000" stroke="#008000" stroke-width=".2"/>
<circle cx="189.6" cy="90" r=".25" fill="#fff" stroke="#000" stroke-width=".2"/>
<path d="M116 105.1h4v1.9h-4zM117.1 109.1h1.9v3.9h-1.9zM117.1 113.9h2v4h-2zM121.1 105.1h4v1.9h-4zM121.1 109.5h4v2h-4z" fill="none" stroke="#800000" stroke-width=".2"/>
<g fill="none" stroke="#808080" stroke-width=".2">
<path d="M113.4 59.1l-2 2M187 59.1l-2 2M111.3 94.1a1.27 1.27 0 0 1 1.3 1.3 1.27 1.27 0 0 1-1.3 1.2M111.3 98.7h13M111.4 91.7l.3-.1 12.4 .1 .2 .3v6.9l-.4 .2h-12.4l-.2-.4v-6.7zM180.4 84.9h9.5v17.4h-9.5zM117.4 110.6v.8M117.4 115.5v.8M117.6 106.7h.8M117.6 105.4h.8M118.7 110.6v.8M118.7 115.5v.8"/>
<path d="M122.7 105.4h.8M122.7 106.7h.8M122.7 111.1h.8M122.7 109.8h.8M145.4 112v.8M180.3 103.1h9.5v17.5h-9.5zM109.6 144.8l-2 2M189.6 144.8l-2 2"/>
<circle cx="112.4" cy="60.1" r=".99"/>
<circle cx="186" cy="60.1" r=".99"/>
<circle cx="145.4" cy="111.1" r="1.27"/>
<circle cx="108.6" cy="145.8" r=".99"/>
<circle cx="188.6" cy="145.8" r=".99"/>
</g>
<g fill="#808080" stroke="#808080" stroke-width=".2">
<path d="M111.8 99.1h.5v.1h-.5z"/>
<path d="M113.1 99.1h.5v.1h-.5z"/>
<path d="M114.4 99.1h.5v.1h-.5z"/>
<path d="M115.6 99.1h.5v.1h-.5z"/>
<path d="M116.9 99.1h.5v.1h-.5z"/>
<path d="M118.2 99.1h.5v.1h-.5z"/>
<path d="M119.4 99.1h.6v.1h-.6z"/>
<path d="M120.7 99.1h.5v.1h-.5z"/>
<path d="M111.8 91.5h.5v.1h-.5z"/>
<path d="M113.1 91.5h.5v.1h-.5z"/>
<path d="M114.4 91.5h.5v.1h-.5z"/>
<path d="M115.6 91.5h.5v.1h-.5z"/>
<path d="M116.9 91.5h.5v.1h-.5z"/>
<path d="M118.2 91.5h.5v.1h-.5z"/>
<path d="M119.4 91.5h.6v.1h-.6z"/>
<path d="M120.7 91.5h.5v.1h-.5z"/>
<path d="M122 91.5h.5v.1h-.5z"/>
<path d="M123.3 91.5h.5v.1h-.5z"/>
<path d="M122 99.1h.5v.1h-.5z"/>
<path d="M123.3 99.1h.5v.1h-.5z"/>
<path d="M111.8 99.2h.5v1.5h-.5z"/>
<path d="M113.1 99.2h.5v1.5h-.5z"/>
<path d="M114.4 99.2h.5v1.5h-.5z"/>
<path d="M115.6 99.2h.5v1.5h-.5z"/>
<path d="M116.9 99.2h.5v1.5h-.5z"/>
<path d="M118.2 99.2h.5v1.5h-.5z"/>
<path d="M119.4 99.2h.6v1.5h-.6z"/>
<path d="M120.7 99.2h.5v1.5h-.5z"/>
<path d="M111.8 90h.5v1.5h-.5z"/>
<path d="M113.1 90h.5v1.5h-.5z"/>
<path d="M114.4 90h.5v1.5h-.5z"/>
<path d="M115.6 90h.5v1.5h-.5z"/>
<path d="M116.9 90h.5v1.5h-.5z"/>
<path d="M118.2 90h.5v1.5h-.5z"/>
<path d="M119.4 90h.6v1.5h-.6z"/>
<path d="M120.7 90h.5v1.5h-.5z"/>
<path d="M122 90h.5v1.5h-.5z"/>
<path d="M123.3 90h.5v1.5h-.5z"/>
<path d="M122 99.2h.5v1.5h-.5z"/>
<path d="M123.3 99.2h.5v1.5h-.5z"/>
<path d="M122.1 109.8h.6v1.4h-.6z"/>
<path d="M123.5 109.8h.7v1.4h-.7z"/>
<path d="M117.4 114.9h1.4v.6h-1.4z"/>
<path d="M117.4 116.3h1.4v.7h-1.4z"/>
<path d="M118.3 105.3h.8v1.5h-.8z"/>
<path d="M116.9 105.3h.8v1.5h-.8z"/>
<path d="M122 105.3h.7v1.4h-.7z"/>
<path d="M123.5 105.3h.6v1.4h-.6z"/>
<path d="M117.3 110h1.4v.6h-1.4z"/>
<path d="M117.3 111.4h1.4v.7h-1.4z"/>
</g>
<g fill="none" stroke="#000" stroke-width=".2">
<path d="M103.3 57.1h90.5v91.8h-90.5v-23a4.9 4.9 0 0 0 5-4.9v-41.2a4.9 4.9 0 0 0-5-4.9zM145 60.5l1.3 1.4M145 65.6l1.3 1.3M146.3 60.5l-1.3 1.4M146.3 65.6l-1.3 1.3M116.8 95.4h2M117.8 94.3v2.1M186.4 93.9h1.9M187.4 92.9v1.9M117.6 106.1h.8M117.7 111h.7M117.7 115.9h.7"/>
<path d="M118 105.7v.7M118.1 110.6v.8M118.1 115.5v.8M122.7 106h.8M122.7 110.5h.8M123.1 105.7v.7M123.1 110.1v.7M144.7 112.4h1.4M145.4 111.7v1.4M186.4 112.1h1.9M187.3 111.1v2"/>
<circle cx="112.4" cy="60.1" r="1.65"/>
<circle cx="186" cy="60.1" r="1.65"/>
<circle cx="108.6" cy="145.8" r="1.65"/>
<circle cx="188.6" cy="145.8" r="1.65"/>
</g>
<path d="M117.8 65h.1" fill="none" stroke="#808000" stroke-width=".2"/>
<use href="#words"/>
</svg>
